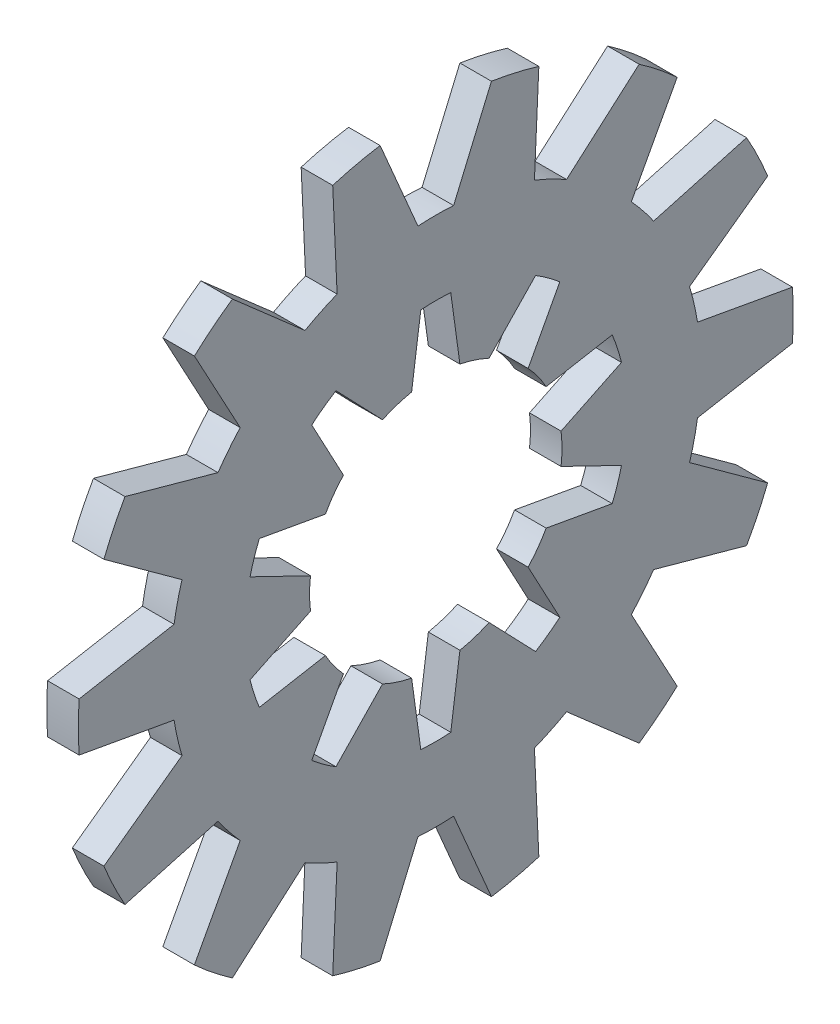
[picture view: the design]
ISO-10303-21;
HEADER;
FILE_DESCRIPTION(('STEP AP214'),'2;1');
FILE_NAME('part.step','',(''),(''),'','','');
FILE_SCHEMA(('AUTOMOTIVE_DESIGN { 1 0 10303 214 1 1 1 1 }'));
ENDSEC;
DATA;
#1=APPLICATION_CONTEXT('core data for automotive mechanical design processes');
#2=APPLICATION_PROTOCOL_DEFINITION('international standard','automotive_design',2000,#1);
#3=PRODUCT_CONTEXT('',#1,'mechanical');
#4=PRODUCT('Part','Part','',(#3));
#5=PRODUCT_RELATED_PRODUCT_CATEGORY('part','',(#4));
#6=PRODUCT_DEFINITION_FORMATION('','',#4);
#7=PRODUCT_DEFINITION_CONTEXT('part definition',#1,'design');
#8=PRODUCT_DEFINITION('design','',#6,#7);
#9=PRODUCT_DEFINITION_SHAPE('','',#8);
#10=(LENGTH_UNIT() NAMED_UNIT(*) SI_UNIT(.MILLI.,.METRE.));
#11=(NAMED_UNIT(*) PLANE_ANGLE_UNIT() SI_UNIT($,.RADIAN.));
#12=(NAMED_UNIT(*) SI_UNIT($,.STERADIAN.) SOLID_ANGLE_UNIT());
#13=UNCERTAINTY_MEASURE_WITH_UNIT(LENGTH_MEASURE(1.E-05),#10,'distance_accuracy_value','');
#14=(GEOMETRIC_REPRESENTATION_CONTEXT(3) GLOBAL_UNCERTAINTY_ASSIGNED_CONTEXT((#13)) GLOBAL_UNIT_ASSIGNED_CONTEXT((#10,
#11,#12)) REPRESENTATION_CONTEXT('',''));
#15=CARTESIAN_POINT('',(0.,0.,0.));
#16=DIRECTION('',(0.,0.,1.));
#17=DIRECTION('',(1.,0.,0.));
#18=AXIS2_PLACEMENT_3D('',#15,#16,#17);
#19=CARTESIAN_POINT('',(-34.9249999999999,0.,0.));
#20=DIRECTION('',(-1.,0.,0.));
#21=DIRECTION('',(0.,0.,1.));
#22=AXIS2_PLACEMENT_3D('',#19,#20,#21);
#23=CYLINDRICAL_SURFACE('',#22,3.2512);
#24=CARTESIAN_POINT('',(-0.812800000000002,0.,0.));
#25=DIRECTION('',(-1.,0.,0.));
#26=DIRECTION('',(0.,0.,1.));
#27=AXIS2_PLACEMENT_3D('',#24,#25,#26);
#28=CIRCLE('',#27,3.2512);
#29=CARTESIAN_POINT('',(-0.812800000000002,-0.394747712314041,3.22714667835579));
#30=VERTEX_POINT('',#29);
#31=CARTESIAN_POINT('',(-0.812800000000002,0.394747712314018,3.2271466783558));
#32=VERTEX_POINT('',#31);
#33=EDGE_CURVE('E1306',#30,#32,#28,.T.);
#34=ORIENTED_EDGE('',*,*,#33,.T.);
#35=DIRECTION('',(-1.,0.,0.));
#36=VECTOR('',#35,1.);
#37=CARTESIAN_POINT('',(-34.9249999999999,0.394747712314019,3.2271466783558));
#38=LINE('',#37,#36);
#39=CARTESIAN_POINT('',(0.,0.394747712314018,3.2271466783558));
#40=VERTEX_POINT('',#39);
#41=EDGE_CURVE('E646',#32,#40,#38,.F.);
#42=ORIENTED_EDGE('',*,*,#41,.T.);
#43=CARTESIAN_POINT('',(0.,0.,0.));
#44=DIRECTION('',(-1.,0.,0.));
#45=DIRECTION('',(0.,0.,1.));
#46=AXIS2_PLACEMENT_3D('',#43,#44,#45);
#47=CIRCLE('',#46,3.2512);
#48=CARTESIAN_POINT('',(0.,-0.394747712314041,3.22714667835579));
#49=VERTEX_POINT('',#48);
#50=EDGE_CURVE('E1313',#49,#40,#47,.T.);
#51=ORIENTED_EDGE('',*,*,#50,.F.);
#52=DIRECTION('',(-1.,0.,0.));
#53=VECTOR('',#52,1.);
#54=CARTESIAN_POINT('',(-34.9249999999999,-0.394747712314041,3.22714667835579));
#55=LINE('',#54,#53);
#56=EDGE_CURVE('E820',#49,#30,#55,.T.);
#57=ORIENTED_EDGE('',*,*,#56,.T.);
#58=EDGE_LOOP('',(#34,#42,#51,#57));
#59=FACE_BOUND('',#58,.T.);
#60=ADVANCED_FACE('F39',(#59),#23,.F.);
#61=CARTESIAN_POINT('',(-0.812800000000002,-2.21622683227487,2.37878962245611));
#62=VERTEX_POINT('',#61);
#63=CARTESIAN_POINT('',(-0.812800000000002,-1.57751161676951,2.84284338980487));
#64=VERTEX_POINT('',#63);
#65=EDGE_CURVE('E1370',#62,#64,#28,.T.);
#66=ORIENTED_EDGE('',*,*,#65,.T.);
#67=DIRECTION('',(-1.,0.,0.));
#68=VECTOR('',#67,1.);
#69=CARTESIAN_POINT('',(-34.9249999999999,-1.57751161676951,2.84284338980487));
#70=LINE('',#69,#68);
#71=CARTESIAN_POINT('',(0.,-1.57751161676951,2.84284338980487));
#72=VERTEX_POINT('',#71);
#73=EDGE_CURVE('E823',#64,#72,#70,.F.);
#74=ORIENTED_EDGE('',*,*,#73,.T.);
#75=CARTESIAN_POINT('',(0.,-2.21622683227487,2.37878962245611));
#76=VERTEX_POINT('',#75);
#77=EDGE_CURVE('E1315',#76,#72,#47,.T.);
#78=ORIENTED_EDGE('',*,*,#77,.F.);
#79=DIRECTION('',(-1.,0.,0.));
#80=VECTOR('',#79,1.);
#81=CARTESIAN_POINT('',(-34.9249999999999,-2.21622683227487,2.37878962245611));
#82=LINE('',#81,#80);
#83=EDGE_CURVE('E814',#76,#62,#82,.T.);
#84=ORIENTED_EDGE('',*,*,#83,.T.);
#85=EDGE_LOOP('',(#66,#74,#78,#84));
#86=FACE_BOUND('',#85,.T.);
#87=ADVANCED_FACE('F1369',(#86),#23,.F.);
#88=CARTESIAN_POINT('',(-0.812800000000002,-3.19118262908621,0.62181578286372));
#89=VERTEX_POINT('',#88);
#90=CARTESIAN_POINT('',(-0.812800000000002,-2.94721512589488,1.37267055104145));
#91=VERTEX_POINT('',#90);
#92=EDGE_CURVE('E1354',#89,#91,#28,.T.);
#93=ORIENTED_EDGE('',*,*,#92,.T.);
#94=DIRECTION('',(-1.,0.,0.));
#95=VECTOR('',#94,1.);
#96=CARTESIAN_POINT('',(-34.9249999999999,-2.94721512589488,1.37267055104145));
#97=LINE('',#96,#95);
#98=CARTESIAN_POINT('',(0.,-2.94721512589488,1.37267055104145));
#99=VERTEX_POINT('',#98);
#100=EDGE_CURVE('E817',#91,#99,#97,.F.);
#101=ORIENTED_EDGE('',*,*,#100,.T.);
#102=CARTESIAN_POINT('',(0.,-3.19118262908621,0.62181578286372));
#103=VERTEX_POINT('',#102);
#104=EDGE_CURVE('E1317',#103,#99,#47,.T.);
#105=ORIENTED_EDGE('',*,*,#104,.F.);
#106=DIRECTION('',(-1.,0.,0.));
#107=VECTOR('',#106,1.);
#108=CARTESIAN_POINT('',(-34.9249999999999,-3.19118262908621,0.62181578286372));
#109=LINE('',#108,#107);
#110=EDGE_CURVE('E808',#103,#89,#109,.T.);
#111=ORIENTED_EDGE('',*,*,#110,.T.);
#112=EDGE_LOOP('',(#93,#101,#105,#111));
#113=FACE_BOUND('',#112,.T.);
#114=ADVANCED_FACE('F1352',(#113),#23,.F.);
#115=CARTESIAN_POINT('',(-0.812800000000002,-2.94721512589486,-1.37267055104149));
#116=VERTEX_POINT('',#115);
#117=CARTESIAN_POINT('',(-0.812800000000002,-3.1911826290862,-0.621815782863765));
#118=VERTEX_POINT('',#117);
#119=EDGE_CURVE('E1374',#116,#118,#28,.T.);
#120=ORIENTED_EDGE('',*,*,#119,.T.);
#121=DIRECTION('',(-1.,0.,0.));
#122=VECTOR('',#121,1.);
#123=CARTESIAN_POINT('',(-34.9249999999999,-3.1911826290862,-0.621815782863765));
#124=LINE('',#123,#122);
#125=CARTESIAN_POINT('',(0.,-3.1911826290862,-0.621815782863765));
#126=VERTEX_POINT('',#125);
#127=EDGE_CURVE('E811',#118,#126,#124,.F.);
#128=ORIENTED_EDGE('',*,*,#127,.T.);
#129=CARTESIAN_POINT('',(0.,-2.94721512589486,-1.37267055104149));
#130=VERTEX_POINT('',#129);
#131=EDGE_CURVE('E1335',#130,#126,#47,.T.);
#132=ORIENTED_EDGE('',*,*,#131,.F.);
#133=DIRECTION('',(-1.,0.,0.));
#134=VECTOR('',#133,1.);
#135=CARTESIAN_POINT('',(-34.9249999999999,-2.94721512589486,-1.37267055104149));
#136=LINE('',#135,#134);
#137=EDGE_CURVE('E802',#130,#116,#136,.T.);
#138=ORIENTED_EDGE('',*,*,#137,.T.);
#139=EDGE_LOOP('',(#120,#128,#132,#138));
#140=FACE_BOUND('',#139,.T.);
#141=ADVANCED_FACE('F1394',(#140),#23,.F.);
#142=CARTESIAN_POINT('',(-0.812800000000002,-1.57751161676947,-2.84284338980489));
#143=VERTEX_POINT('',#142);
#144=CARTESIAN_POINT('',(-0.812800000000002,-2.21622683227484,-2.37878962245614));
#145=VERTEX_POINT('',#144);
#146=EDGE_CURVE('E1385',#143,#145,#28,.T.);
#147=ORIENTED_EDGE('',*,*,#146,.T.);
#148=DIRECTION('',(-1.,0.,0.));
#149=VECTOR('',#148,1.);
#150=CARTESIAN_POINT('',(-34.9249999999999,-2.21622683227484,-2.37878962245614));
#151=LINE('',#150,#149);
#152=CARTESIAN_POINT('',(0.,-2.21622683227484,-2.37878962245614));
#153=VERTEX_POINT('',#152);
#154=EDGE_CURVE('E805',#145,#153,#151,.F.);
#155=ORIENTED_EDGE('',*,*,#154,.T.);
#156=CARTESIAN_POINT('',(0.,-1.57751161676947,-2.84284338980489));
#157=VERTEX_POINT('',#156);
#158=EDGE_CURVE('E1330',#157,#153,#47,.T.);
#159=ORIENTED_EDGE('',*,*,#158,.F.);
#160=DIRECTION('',(-1.,0.,0.));
#161=VECTOR('',#160,1.);
#162=CARTESIAN_POINT('',(-34.9249999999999,-1.57751161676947,-2.84284338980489));
#163=LINE('',#162,#161);
#164=EDGE_CURVE('E796',#157,#143,#163,.T.);
#165=ORIENTED_EDGE('',*,*,#164,.T.);
#166=EDGE_LOOP('',(#147,#155,#159,#165));
#167=FACE_BOUND('',#166,.T.);
#168=ADVANCED_FACE('F1491',(#167),#23,.F.);
#169=CARTESIAN_POINT('',(-0.812800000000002,0.394747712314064,-3.22714667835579));
#170=VERTEX_POINT('',#169);
#171=CARTESIAN_POINT('',(-0.812800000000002,-0.394747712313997,-3.2271466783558));
#172=VERTEX_POINT('',#171);
#173=EDGE_CURVE('E1381',#170,#172,#28,.T.);
#174=ORIENTED_EDGE('',*,*,#173,.T.);
#175=DIRECTION('',(-1.,0.,0.));
#176=VECTOR('',#175,1.);
#177=CARTESIAN_POINT('',(-34.9249999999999,-0.394747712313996,-3.2271466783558));
#178=LINE('',#177,#176);
#179=CARTESIAN_POINT('',(0.,-0.394747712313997,-3.2271466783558));
#180=VERTEX_POINT('',#179);
#181=EDGE_CURVE('E799',#172,#180,#178,.F.);
#182=ORIENTED_EDGE('',*,*,#181,.T.);
#183=CARTESIAN_POINT('',(0.,0.394747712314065,-3.22714667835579));
#184=VERTEX_POINT('',#183);
#185=EDGE_CURVE('E1325',#184,#180,#47,.T.);
#186=ORIENTED_EDGE('',*,*,#185,.F.);
#187=DIRECTION('',(-1.,0.,0.));
#188=VECTOR('',#187,1.);
#189=CARTESIAN_POINT('',(-34.9249999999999,0.394747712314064,-3.22714667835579));
#190=LINE('',#189,#188);
#191=EDGE_CURVE('E790',#184,#170,#190,.T.);
#192=ORIENTED_EDGE('',*,*,#191,.T.);
#193=EDGE_LOOP('',(#174,#182,#186,#192));
#194=FACE_BOUND('',#193,.T.);
#195=ADVANCED_FACE('F1481',(#194),#23,.F.);
#196=CARTESIAN_POINT('',(-0.812800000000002,2.21622683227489,-2.37878962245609));
#197=VERTEX_POINT('',#196);
#198=CARTESIAN_POINT('',(-0.812800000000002,1.57751161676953,-2.84284338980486));
#199=VERTEX_POINT('',#198);
#200=EDGE_CURVE('E1221',#197,#199,#28,.T.);
#201=ORIENTED_EDGE('',*,*,#200,.T.);
#202=DIRECTION('',(-1.,0.,0.));
#203=VECTOR('',#202,1.);
#204=CARTESIAN_POINT('',(-34.9249999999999,1.57751161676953,-2.84284338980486));
#205=LINE('',#204,#203);
#206=CARTESIAN_POINT('',(0.,1.57751161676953,-2.84284338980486));
#207=VERTEX_POINT('',#206);
#208=EDGE_CURVE('E793',#199,#207,#205,.F.);
#209=ORIENTED_EDGE('',*,*,#208,.T.);
#210=CARTESIAN_POINT('',(0.,2.21622683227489,-2.37878962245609));
#211=VERTEX_POINT('',#210);
#212=EDGE_CURVE('E1239',#211,#207,#47,.T.);
#213=ORIENTED_EDGE('',*,*,#212,.F.);
#214=DIRECTION('',(-1.,0.,0.));
#215=VECTOR('',#214,1.);
#216=CARTESIAN_POINT('',(-34.9249999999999,2.21622683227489,-2.37878962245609));
#217=LINE('',#216,#215);
#218=EDGE_CURVE('E639',#211,#197,#217,.T.);
#219=ORIENTED_EDGE('',*,*,#218,.T.);
#220=EDGE_LOOP('',(#201,#209,#213,#219));
#221=FACE_BOUND('',#220,.T.);
#222=ADVANCED_FACE('F1439',(#221),#23,.F.);
#223=CARTESIAN_POINT('',(-0.812800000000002,3.19118262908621,-0.621815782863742));
#224=VERTEX_POINT('',#223);
#225=CARTESIAN_POINT('',(-0.812800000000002,2.94721512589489,-1.37267055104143));
#226=VERTEX_POINT('',#225);
#227=EDGE_CURVE('E1217',#224,#226,#28,.T.);
#228=ORIENTED_EDGE('',*,*,#227,.T.);
#229=DIRECTION('',(-1.,0.,0.));
#230=VECTOR('',#229,1.);
#231=CARTESIAN_POINT('',(-34.9249999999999,2.94721512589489,-1.37267055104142));
#232=LINE('',#231,#230);
#233=CARTESIAN_POINT('',(0.,2.94721512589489,-1.37267055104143));
#234=VERTEX_POINT('',#233);
#235=EDGE_CURVE('E787',#226,#234,#232,.F.);
#236=ORIENTED_EDGE('',*,*,#235,.T.);
#237=CARTESIAN_POINT('',(0.,3.19118262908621,-0.621815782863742));
#238=VERTEX_POINT('',#237);
#239=EDGE_CURVE('E1235',#238,#234,#47,.T.);
#240=ORIENTED_EDGE('',*,*,#239,.F.);
#241=DIRECTION('',(-1.,0.,0.));
#242=VECTOR('',#241,1.);
#243=CARTESIAN_POINT('',(-34.9249999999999,3.19118262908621,-0.621815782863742));
#244=LINE('',#243,#242);
#245=EDGE_CURVE('E872',#238,#224,#244,.T.);
#246=ORIENTED_EDGE('',*,*,#245,.T.);
#247=EDGE_LOOP('',(#228,#236,#240,#246));
#248=FACE_BOUND('',#247,.T.);
#249=ADVANCED_FACE('F1432',(#248),#23,.F.);
#250=CARTESIAN_POINT('',(0.,1.57751161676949,2.84284338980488));
#251=VERTEX_POINT('',#250);
#252=CARTESIAN_POINT('',(0.,2.21622683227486,2.37878962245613));
#253=VERTEX_POINT('',#252);
#254=EDGE_CURVE('E1240',#251,#253,#47,.T.);
#255=ORIENTED_EDGE('',*,*,#254,.F.);
#256=DIRECTION('',(-1.,0.,0.));
#257=VECTOR('',#256,1.);
#258=CARTESIAN_POINT('',(-34.9249999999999,1.57751161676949,2.84284338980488));
#259=LINE('',#258,#257);
#260=CARTESIAN_POINT('',(-0.812800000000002,1.57751161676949,2.84284338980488));
#261=VERTEX_POINT('',#260);
#262=EDGE_CURVE('E826',#251,#261,#259,.T.);
#263=ORIENTED_EDGE('',*,*,#262,.T.);
#264=CARTESIAN_POINT('',(-0.812800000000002,2.21622683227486,2.37878962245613));
#265=VERTEX_POINT('',#264);
#266=EDGE_CURVE('E1222',#261,#265,#28,.T.);
#267=ORIENTED_EDGE('',*,*,#266,.T.);
#268=DIRECTION('',(-1.,0.,0.));
#269=VECTOR('',#268,1.);
#270=CARTESIAN_POINT('',(-34.9249999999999,2.21622683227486,2.37878962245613));
#271=LINE('',#270,#269);
#272=EDGE_CURVE('E852',#265,#253,#271,.F.);
#273=ORIENTED_EDGE('',*,*,#272,.T.);
#274=EDGE_LOOP('',(#255,#263,#267,#273));
#275=FACE_BOUND('',#274,.T.);
#276=ADVANCED_FACE('F1420',(#275),#23,.F.);
#277=CARTESIAN_POINT('',(-34.9249999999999,0.,0.));
#278=DIRECTION('',(-1.,0.,0.));
#279=DIRECTION('',(0.,0.,1.));
#280=AXIS2_PLACEMENT_3D('',#277,#278,#279);
#281=CYLINDRICAL_SURFACE('',#280,9.2075);
#282=CARTESIAN_POINT('',(-0.812800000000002,0.,0.));
#283=DIRECTION('',(-1.,0.,0.));
#284=DIRECTION('',(0.,0.,1.));
#285=AXIS2_PLACEMENT_3D('',#282,#283,#284);
#286=CIRCLE('',#285,9.2075);
#287=CARTESIAN_POINT('',(-0.812800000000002,6.79155829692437,6.2171369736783));
#288=VERTEX_POINT('',#287);
#289=CARTESIAN_POINT('',(-0.812800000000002,7.57252426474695,5.23783662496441));
#290=VERTEX_POINT('',#289);
#291=EDGE_CURVE('E1228',#288,#290,#286,.T.);
#292=ORIENTED_EDGE('',*,*,#291,.F.);
#293=DIRECTION('',(-1.,0.,0.));
#294=VECTOR('',#293,1.);
#295=CARTESIAN_POINT('',(-34.9249999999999,6.79155829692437,6.2171369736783));
#296=LINE('',#295,#294);
#297=CARTESIAN_POINT('',(0.,6.79155829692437,6.2171369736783));
#298=VERTEX_POINT('',#297);
#299=EDGE_CURVE('E1165',#288,#298,#296,.F.);
#300=ORIENTED_EDGE('',*,*,#299,.T.);
#301=CARTESIAN_POINT('',(0.,0.,0.));
#302=DIRECTION('',(-1.,0.,0.));
#303=DIRECTION('',(0.,0.,1.));
#304=AXIS2_PLACEMENT_3D('',#301,#302,#303);
#305=CIRCLE('',#304,9.2075);
#306=CARTESIAN_POINT('',(0.,7.57252426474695,5.23783662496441));
#307=VERTEX_POINT('',#306);
#308=EDGE_CURVE('E1234',#298,#307,#305,.T.);
#309=ORIENTED_EDGE('',*,*,#308,.T.);
#310=DIRECTION('',(-1.,0.,0.));
#311=VECTOR('',#310,1.);
#312=CARTESIAN_POINT('',(-34.9249999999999,7.57252426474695,5.23783662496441));
#313=LINE('',#312,#311);
#314=EDGE_CURVE('E1184',#307,#290,#313,.T.);
#315=ORIENTED_EDGE('',*,*,#314,.T.);
#316=EDGE_LOOP('',(#292,#300,#309,#315));
#317=FACE_BOUND('',#316,.T.);
#318=ADVANCED_FACE('F1431',(#317),#281,.T.);
#319=CARTESIAN_POINT('',(0.,3.42146795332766,8.54819356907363));
#320=VERTEX_POINT('',#319);
#321=CARTESIAN_POINT('',(0.,4.54999647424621,8.00472287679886));
#322=VERTEX_POINT('',#321);
#323=EDGE_CURVE('E1730',#320,#322,#305,.T.);
#324=ORIENTED_EDGE('',*,*,#323,.T.);
#325=DIRECTION('',(-1.,0.,0.));
#326=VECTOR('',#325,1.);
#327=CARTESIAN_POINT('',(-34.9249999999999,4.5499964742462,8.00472287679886));
#328=LINE('',#327,#326);
#329=CARTESIAN_POINT('',(-0.812800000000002,4.54999647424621,8.00472287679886));
#330=VERTEX_POINT('',#329);
#331=EDGE_CURVE('E1162',#322,#330,#328,.T.);
#332=ORIENTED_EDGE('',*,*,#331,.T.);
#333=CARTESIAN_POINT('',(-0.812800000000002,3.42146795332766,8.54819356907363));
#334=VERTEX_POINT('',#333);
#335=EDGE_CURVE('E1783',#334,#330,#286,.T.);
#336=ORIENTED_EDGE('',*,*,#335,.F.);
#337=DIRECTION('',(-1.,0.,0.));
#338=VECTOR('',#337,1.);
#339=CARTESIAN_POINT('',(-34.9249999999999,3.42146795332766,8.54819356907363));
#340=LINE('',#339,#338);
#341=EDGE_CURVE('E1159',#334,#320,#340,.F.);
#342=ORIENTED_EDGE('',*,*,#341,.T.);
#343=EDGE_LOOP('',(#324,#332,#336,#342));
#344=FACE_BOUND('',#343,.T.);
#345=ADVANCED_FACE('F1437',(#344),#281,.T.);
#346=CARTESIAN_POINT('',(0.,-0.626286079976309,9.18617559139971));
#347=VERTEX_POINT('',#346);
#348=CARTESIAN_POINT('',(0.,0.626286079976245,9.18617559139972));
#349=VERTEX_POINT('',#348);
#350=EDGE_CURVE('E1764',#347,#349,#305,.T.);
#351=ORIENTED_EDGE('',*,*,#350,.T.);
#352=DIRECTION('',(-1.,0.,0.));
#353=VECTOR('',#352,1.);
#354=CARTESIAN_POINT('',(-34.9249999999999,0.626286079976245,9.18617559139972));
#355=LINE('',#354,#353);
#356=CARTESIAN_POINT('',(-0.812800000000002,0.626286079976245,9.18617559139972));
#357=VERTEX_POINT('',#356);
#358=EDGE_CURVE('E1156',#349,#357,#355,.T.);
#359=ORIENTED_EDGE('',*,*,#358,.T.);
#360=CARTESIAN_POINT('',(-0.812800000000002,-0.626286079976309,9.18617559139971));
#361=VERTEX_POINT('',#360);
#362=EDGE_CURVE('E1785',#361,#357,#286,.T.);
#363=ORIENTED_EDGE('',*,*,#362,.F.);
#364=DIRECTION('',(-1.,0.,0.));
#365=VECTOR('',#364,1.);
#366=CARTESIAN_POINT('',(-34.9249999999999,-0.626286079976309,9.18617559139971));
#367=LINE('',#366,#365);
#368=EDGE_CURVE('E1153',#361,#347,#367,.F.);
#369=ORIENTED_EDGE('',*,*,#368,.T.);
#370=EDGE_LOOP('',(#351,#359,#363,#369));
#371=FACE_BOUND('',#370,.T.);
#372=ADVANCED_FACE('F1821',(#371),#281,.T.);
#373=CARTESIAN_POINT('',(-0.812800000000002,-9.09522075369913,1.43353259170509));
#374=VERTEX_POINT('',#373);
#375=CARTESIAN_POINT('',(-0.812800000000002,-8.81649722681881,2.65470015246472));
#376=VERTEX_POINT('',#375);
#377=EDGE_CURVE('E1803',#374,#376,#286,.T.);
#378=ORIENTED_EDGE('',*,*,#377,.F.);
#379=DIRECTION('',(-1.,0.,0.));
#380=VECTOR('',#379,1.);
#381=CARTESIAN_POINT('',(-34.9249999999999,-9.09522075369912,1.43353259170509));
#382=LINE('',#381,#380);
#383=CARTESIAN_POINT('',(0.,-9.09522075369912,1.43353259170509));
#384=VERTEX_POINT('',#383);
#385=EDGE_CURVE('E1147',#374,#384,#382,.F.);
#386=ORIENTED_EDGE('',*,*,#385,.T.);
#387=CARTESIAN_POINT('',(0.,-8.81649722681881,2.65470015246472));
#388=VERTEX_POINT('',#387);
#389=EDGE_CURVE('E1752',#384,#388,#305,.T.);
#390=ORIENTED_EDGE('',*,*,#389,.T.);
#391=DIRECTION('',(-1.,0.,0.));
#392=VECTOR('',#391,1.);
#393=CARTESIAN_POINT('',(-34.9249999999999,-8.81649722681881,2.65470015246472));
#394=LINE('',#393,#392);
#395=EDGE_CURVE('E1138',#388,#376,#394,.T.);
#396=ORIENTED_EDGE('',*,*,#395,.T.);
#397=EDGE_LOOP('',(#378,#386,#390,#396));
#398=FACE_BOUND('',#397,.T.);
#399=ADVANCED_FACE('F1825',(#398),#281,.T.);
#400=CARTESIAN_POINT('',(-0.812800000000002,-7.57252426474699,5.23783662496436));
#401=VERTEX_POINT('',#400);
#402=CARTESIAN_POINT('',(-0.812800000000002,-6.79155829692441,6.21713697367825));
#403=VERTEX_POINT('',#402);
#404=EDGE_CURVE('E1806',#401,#403,#286,.T.);
#405=ORIENTED_EDGE('',*,*,#404,.F.);
#406=DIRECTION('',(-1.,0.,0.));
#407=VECTOR('',#406,1.);
#408=CARTESIAN_POINT('',(-34.9249999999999,-7.57252426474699,5.23783662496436));
#409=LINE('',#408,#407);
#410=CARTESIAN_POINT('',(0.,-7.57252426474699,5.23783662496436));
#411=VERTEX_POINT('',#410);
#412=EDGE_CURVE('E1141',#401,#411,#409,.F.);
#413=ORIENTED_EDGE('',*,*,#412,.T.);
#414=CARTESIAN_POINT('',(0.,-6.79155829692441,6.21713697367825));
#415=VERTEX_POINT('',#414);
#416=EDGE_CURVE('E1756',#411,#415,#305,.T.);
#417=ORIENTED_EDGE('',*,*,#416,.T.);
#418=DIRECTION('',(-1.,0.,0.));
#419=VECTOR('',#418,1.);
#420=CARTESIAN_POINT('',(-34.9249999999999,-6.79155829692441,6.21713697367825));
#421=LINE('',#420,#419);
#422=EDGE_CURVE('E1132',#415,#403,#421,.T.);
#423=ORIENTED_EDGE('',*,*,#422,.T.);
#424=EDGE_LOOP('',(#405,#413,#417,#423));
#425=FACE_BOUND('',#424,.T.);
#426=ADVANCED_FACE('F1830',(#425),#281,.T.);
#427=CARTESIAN_POINT('',(0.,-4.54999647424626,8.00472287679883));
#428=VERTEX_POINT('',#427);
#429=CARTESIAN_POINT('',(0.,-3.42146795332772,8.54819356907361));
#430=VERTEX_POINT('',#429);
#431=EDGE_CURVE('E1760',#428,#430,#305,.T.);
#432=ORIENTED_EDGE('',*,*,#431,.T.);
#433=DIRECTION('',(-1.,0.,0.));
#434=VECTOR('',#433,1.);
#435=CARTESIAN_POINT('',(-34.9249999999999,-3.42146795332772,8.54819356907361));
#436=LINE('',#435,#434);
#437=CARTESIAN_POINT('',(-0.812800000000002,-3.42146795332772,8.54819356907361));
#438=VERTEX_POINT('',#437);
#439=EDGE_CURVE('E1150',#430,#438,#436,.T.);
#440=ORIENTED_EDGE('',*,*,#439,.T.);
#441=CARTESIAN_POINT('',(-0.812800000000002,-4.54999647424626,8.00472287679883));
#442=VERTEX_POINT('',#441);
#443=EDGE_CURVE('E1787',#442,#438,#286,.T.);
#444=ORIENTED_EDGE('',*,*,#443,.F.);
#445=DIRECTION('',(-1.,0.,0.));
#446=VECTOR('',#445,1.);
#447=CARTESIAN_POINT('',(-34.9249999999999,-4.54999647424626,8.00472287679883));
#448=LINE('',#447,#446);
#449=EDGE_CURVE('E1135',#442,#428,#448,.F.);
#450=ORIENTED_EDGE('',*,*,#449,.T.);
#451=EDGE_LOOP('',(#432,#440,#444,#450));
#452=FACE_BOUND('',#451,.T.);
#453=ADVANCED_FACE('F1813',(#452),#281,.T.);
#454=CARTESIAN_POINT('',(-0.812800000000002,-3.42146795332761,-8.54819356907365));
#455=VERTEX_POINT('',#454);
#456=CARTESIAN_POINT('',(-0.812800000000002,-4.54999647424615,-8.00472287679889));
#457=VERTEX_POINT('',#456);
#458=EDGE_CURVE('E1794',#455,#457,#286,.T.);
#459=ORIENTED_EDGE('',*,*,#458,.F.);
#460=DIRECTION('',(-1.,0.,0.));
#461=VECTOR('',#460,1.);
#462=CARTESIAN_POINT('',(-34.9249999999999,-3.42146795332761,-8.54819356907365));
#463=LINE('',#462,#461);
#464=CARTESIAN_POINT('',(0.,-3.42146795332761,-8.54819356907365));
#465=VERTEX_POINT('',#464);
#466=EDGE_CURVE('E1129',#455,#465,#463,.F.);
#467=ORIENTED_EDGE('',*,*,#466,.T.);
#468=CARTESIAN_POINT('',(0.,-4.54999647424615,-8.00472287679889));
#469=VERTEX_POINT('',#468);
#470=EDGE_CURVE('E1740',#465,#469,#305,.T.);
#471=ORIENTED_EDGE('',*,*,#470,.T.);
#472=DIRECTION('',(-1.,0.,0.));
#473=VECTOR('',#472,1.);
#474=CARTESIAN_POINT('',(-34.9249999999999,-4.54999647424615,-8.00472287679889));
#475=LINE('',#474,#473);
#476=EDGE_CURVE('E1120',#469,#457,#475,.T.);
#477=ORIENTED_EDGE('',*,*,#476,.T.);
#478=EDGE_LOOP('',(#459,#467,#471,#477));
#479=FACE_BOUND('',#478,.T.);
#480=ADVANCED_FACE('F2410',(#479),#281,.T.);
#481=CARTESIAN_POINT('',(-0.812800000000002,-6.79155829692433,-6.21713697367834));
#482=VERTEX_POINT('',#481);
#483=CARTESIAN_POINT('',(-0.812800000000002,-7.57252426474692,-5.23783662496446));
#484=VERTEX_POINT('',#483);
#485=EDGE_CURVE('E1797',#482,#484,#286,.T.);
#486=ORIENTED_EDGE('',*,*,#485,.F.);
#487=DIRECTION('',(-1.,0.,0.));
#488=VECTOR('',#487,1.);
#489=CARTESIAN_POINT('',(-34.9249999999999,-6.79155829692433,-6.21713697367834));
#490=LINE('',#489,#488);
#491=CARTESIAN_POINT('',(0.,-6.79155829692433,-6.21713697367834));
#492=VERTEX_POINT('',#491);
#493=EDGE_CURVE('E1123',#482,#492,#490,.F.);
#494=ORIENTED_EDGE('',*,*,#493,.T.);
#495=CARTESIAN_POINT('',(0.,-7.57252426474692,-5.23783662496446));
#496=VERTEX_POINT('',#495);
#497=EDGE_CURVE('E1744',#492,#496,#305,.T.);
#498=ORIENTED_EDGE('',*,*,#497,.T.);
#499=DIRECTION('',(-1.,0.,0.));
#500=VECTOR('',#499,1.);
#501=CARTESIAN_POINT('',(-34.9249999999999,-7.57252426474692,-5.23783662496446));
#502=LINE('',#501,#500);
#503=EDGE_CURVE('E1114',#496,#484,#502,.T.);
#504=ORIENTED_EDGE('',*,*,#503,.T.);
#505=EDGE_LOOP('',(#486,#494,#498,#504));
#506=FACE_BOUND('',#505,.T.);
#507=ADVANCED_FACE('F2402',(#506),#281,.T.);
#508=CARTESIAN_POINT('',(0.,-8.81649722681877,-2.65470015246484));
#509=VERTEX_POINT('',#508);
#510=CARTESIAN_POINT('',(0.,-9.0952207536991,-1.43353259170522));
#511=VERTEX_POINT('',#510);
#512=EDGE_CURVE('E1748',#509,#511,#305,.T.);
#513=ORIENTED_EDGE('',*,*,#512,.T.);
#514=DIRECTION('',(-1.,0.,0.));
#515=VECTOR('',#514,1.);
#516=CARTESIAN_POINT('',(-34.9249999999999,-9.0952207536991,-1.43353259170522));
#517=LINE('',#516,#515);
#518=CARTESIAN_POINT('',(-0.812800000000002,-9.0952207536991,-1.43353259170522));
#519=VERTEX_POINT('',#518);
#520=EDGE_CURVE('E1144',#511,#519,#517,.T.);
#521=ORIENTED_EDGE('',*,*,#520,.T.);
#522=CARTESIAN_POINT('',(-0.812800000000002,-8.81649722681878,-2.65470015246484));
#523=VERTEX_POINT('',#522);
#524=EDGE_CURVE('E1800',#523,#519,#286,.T.);
#525=ORIENTED_EDGE('',*,*,#524,.F.);
#526=DIRECTION('',(-1.,0.,0.));
#527=VECTOR('',#526,1.);
#528=CARTESIAN_POINT('',(-34.9249999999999,-8.81649722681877,-2.65470015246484));
#529=LINE('',#528,#527);
#530=EDGE_CURVE('E1117',#523,#509,#529,.F.);
#531=ORIENTED_EDGE('',*,*,#530,.T.);
#532=EDGE_LOOP('',(#513,#521,#525,#531));
#533=FACE_BOUND('',#532,.T.);
#534=ADVANCED_FACE('F2395',(#533),#281,.T.);
#535=CARTESIAN_POINT('',(0.,0.626286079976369,-9.18617559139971));
#536=VERTEX_POINT('',#535);
#537=CARTESIAN_POINT('',(0.,-0.626286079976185,-9.18617559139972));
#538=VERTEX_POINT('',#537);
#539=EDGE_CURVE('E1736',#536,#538,#305,.T.);
#540=ORIENTED_EDGE('',*,*,#539,.T.);
#541=DIRECTION('',(-1.,0.,0.));
#542=VECTOR('',#541,1.);
#543=CARTESIAN_POINT('',(-34.9249999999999,-0.626286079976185,-9.18617559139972));
#544=LINE('',#543,#542);
#545=CARTESIAN_POINT('',(-0.812800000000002,-0.626286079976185,-9.18617559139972));
#546=VERTEX_POINT('',#545);
#547=EDGE_CURVE('E1126',#538,#546,#544,.T.);
#548=ORIENTED_EDGE('',*,*,#547,.T.);
#549=CARTESIAN_POINT('',(-0.812800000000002,0.626286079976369,-9.18617559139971));
#550=VERTEX_POINT('',#549);
#551=EDGE_CURVE('E1791',#550,#546,#286,.T.);
#552=ORIENTED_EDGE('',*,*,#551,.F.);
#553=DIRECTION('',(-1.,0.,0.));
#554=VECTOR('',#553,1.);
#555=CARTESIAN_POINT('',(-34.9249999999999,0.626286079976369,-9.18617559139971));
#556=LINE('',#555,#554);
#557=EDGE_CURVE('E1111',#550,#536,#556,.F.);
#558=ORIENTED_EDGE('',*,*,#557,.T.);
#559=EDGE_LOOP('',(#540,#548,#552,#558));
#560=FACE_BOUND('',#559,.T.);
#561=ADVANCED_FACE('F2387',(#560),#281,.T.);
#562=CARTESIAN_POINT('',(-0.812800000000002,7.57252426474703,-5.2378366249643));
#563=VERTEX_POINT('',#562);
#564=CARTESIAN_POINT('',(-0.812800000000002,6.79155829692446,-6.2171369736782));
#565=VERTEX_POINT('',#564);
#566=EDGE_CURVE('E1227',#563,#565,#286,.T.);
#567=ORIENTED_EDGE('',*,*,#566,.F.);
#568=DIRECTION('',(-1.,0.,0.));
#569=VECTOR('',#568,1.);
#570=CARTESIAN_POINT('',(-34.9249999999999,7.57252426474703,-5.2378366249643));
#571=LINE('',#570,#569);
#572=CARTESIAN_POINT('',(0.,7.57252426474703,-5.2378366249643));
#573=VERTEX_POINT('',#572);
#574=EDGE_CURVE('E1105',#563,#573,#571,.F.);
#575=ORIENTED_EDGE('',*,*,#574,.T.);
#576=CARTESIAN_POINT('',(0.,6.79155829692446,-6.2171369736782));
#577=VERTEX_POINT('',#576);
#578=EDGE_CURVE('E1233',#573,#577,#305,.T.);
#579=ORIENTED_EDGE('',*,*,#578,.T.);
#580=DIRECTION('',(-1.,0.,0.));
#581=VECTOR('',#580,1.);
#582=CARTESIAN_POINT('',(-34.9249999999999,6.79155829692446,-6.2171369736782));
#583=LINE('',#582,#581);
#584=EDGE_CURVE('E898',#577,#565,#583,.T.);
#585=ORIENTED_EDGE('',*,*,#584,.T.);
#586=EDGE_LOOP('',(#567,#575,#579,#585));
#587=FACE_BOUND('',#586,.T.);
#588=ADVANCED_FACE('F2379',(#587),#281,.T.);
#589=CARTESIAN_POINT('',(0.,4.54999647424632,-8.0047228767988));
#590=VERTEX_POINT('',#589);
#591=CARTESIAN_POINT('',(0.,3.42146795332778,-8.54819356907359));
#592=VERTEX_POINT('',#591);
#593=EDGE_CURVE('E1732',#590,#592,#305,.T.);
#594=ORIENTED_EDGE('',*,*,#593,.T.);
#595=DIRECTION('',(-1.,0.,0.));
#596=VECTOR('',#595,1.);
#597=CARTESIAN_POINT('',(-34.9249999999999,3.42146795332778,-8.54819356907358));
#598=LINE('',#597,#596);
#599=CARTESIAN_POINT('',(-0.812800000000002,3.42146795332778,-8.54819356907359));
#600=VERTEX_POINT('',#599);
#601=EDGE_CURVE('E1108',#592,#600,#598,.T.);
#602=ORIENTED_EDGE('',*,*,#601,.T.);
#603=CARTESIAN_POINT('',(-0.812800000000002,4.54999647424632,-8.0047228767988));
#604=VERTEX_POINT('',#603);
#605=EDGE_CURVE('E1789',#604,#600,#286,.T.);
#606=ORIENTED_EDGE('',*,*,#605,.F.);
#607=DIRECTION('',(-1.,0.,0.));
#608=VECTOR('',#607,1.);
#609=CARTESIAN_POINT('',(-34.9249999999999,4.54999647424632,-8.0047228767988));
#610=LINE('',#609,#608);
#611=EDGE_CURVE('E1099',#604,#590,#610,.F.);
#612=ORIENTED_EDGE('',*,*,#611,.T.);
#613=EDGE_LOOP('',(#594,#602,#606,#612));
#614=FACE_BOUND('',#613,.T.);
#615=ADVANCED_FACE('F1428',(#614),#281,.T.);
#616=CARTESIAN_POINT('',(-0.812800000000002,8.81649722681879,2.65470015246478));
#617=VERTEX_POINT('',#616);
#618=CARTESIAN_POINT('',(-0.812800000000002,9.09522075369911,1.43353259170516));
#619=VERTEX_POINT('',#618);
#620=EDGE_CURVE('E1220',#617,#619,#286,.T.);
#621=ORIENTED_EDGE('',*,*,#620,.F.);
#622=DIRECTION('',(-1.,0.,0.));
#623=VECTOR('',#622,1.);
#624=CARTESIAN_POINT('',(-34.9249999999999,8.81649722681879,2.65470015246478));
#625=LINE('',#624,#623);
#626=CARTESIAN_POINT('',(0.,8.81649722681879,2.65470015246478));
#627=VERTEX_POINT('',#626);
#628=EDGE_CURVE('E1189',#617,#627,#625,.F.);
#629=ORIENTED_EDGE('',*,*,#628,.T.);
#630=CARTESIAN_POINT('',(0.,9.09522075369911,1.43353259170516));
#631=VERTEX_POINT('',#630);
#632=EDGE_CURVE('E1226',#627,#631,#305,.T.);
#633=ORIENTED_EDGE('',*,*,#632,.T.);
#634=DIRECTION('',(-1.,0.,0.));
#635=VECTOR('',#634,1.);
#636=CARTESIAN_POINT('',(-34.9249999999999,9.09522075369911,1.43353259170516));
#637=LINE('',#636,#635);
#638=EDGE_CURVE('E1208',#631,#619,#637,.T.);
#639=ORIENTED_EDGE('',*,*,#638,.T.);
#640=EDGE_LOOP('',(#621,#629,#633,#639));
#641=FACE_BOUND('',#640,.T.);
#642=ADVANCED_FACE('F1419',(#641),#281,.T.);
#643=CARTESIAN_POINT('',(0.,2.94721512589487,1.37267055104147));
#644=VERTEX_POINT('',#643);
#645=CARTESIAN_POINT('',(0.,3.19118262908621,0.621815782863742));
#646=VERTEX_POINT('',#645);
#647=EDGE_CURVE('E1232',#644,#646,#47,.T.);
#648=ORIENTED_EDGE('',*,*,#647,.F.);
#649=DIRECTION('',(-1.,0.,0.));
#650=VECTOR('',#649,1.);
#651=CARTESIAN_POINT('',(-34.9249999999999,2.94721512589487,1.37267055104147));
#652=LINE('',#651,#650);
#653=CARTESIAN_POINT('',(-0.812800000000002,2.94721512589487,1.37267055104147));
#654=VERTEX_POINT('',#653);
#655=EDGE_CURVE('E847',#644,#654,#652,.T.);
#656=ORIENTED_EDGE('',*,*,#655,.T.);
#657=CARTESIAN_POINT('',(-0.812800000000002,3.19118262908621,0.621815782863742));
#658=VERTEX_POINT('',#657);
#659=EDGE_CURVE('E1216',#654,#658,#28,.T.);
#660=ORIENTED_EDGE('',*,*,#659,.T.);
#661=DIRECTION('',(-1.,0.,0.));
#662=VECTOR('',#661,1.);
#663=CARTESIAN_POINT('',(-34.9249999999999,3.19118262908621,0.621815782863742));
#664=LINE('',#663,#662);
#665=EDGE_CURVE('E877',#658,#646,#664,.F.);
#666=ORIENTED_EDGE('',*,*,#665,.T.);
#667=EDGE_LOOP('',(#648,#656,#660,#666));
#668=FACE_BOUND('',#667,.T.);
#669=ADVANCED_FACE('F41',(#668),#23,.F.);
#670=CARTESIAN_POINT('',(0.,3.2512,0.));
#671=DIRECTION('',(-1.,0.,0.));
#672=DIRECTION('',(0.,0.,1.));
#673=AXIS2_PLACEMENT_3D('',#670,#671,#672);
#674=PLANE('',#673);
#675=ORIENTED_EDGE('',*,*,#308,.F.);
#676=DIRECTION('',(0.,0.880151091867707,0.474693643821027));
#677=VECTOR('',#676,1.);
#678=CARTESIAN_POINT('',(0.,7.20877524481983,6.44215542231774));
#679=LINE('',#678,#677);
#680=CARTESIAN_POINT('',(0.,4.60461298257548,5.03764739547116));
#681=VERTEX_POINT('',#680);
#682=EDGE_CURVE('E885',#681,#298,#679,.T.);
#683=ORIENTED_EDGE('',*,*,#682,.F.);
#684=CARTESIAN_POINT('',(0.,0.,0.));
#685=DIRECTION('',(-1.,0.,0.));
#686=DIRECTION('',(0.,0.781831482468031,-0.623489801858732));
#687=AXIS2_PLACEMENT_3D('',#684,#685,#686);
#688=CIRCLE('',#687,6.82498);
#689=CARTESIAN_POINT('',(0.,3.88672027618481,5.61014772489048));
#690=VERTEX_POINT('',#689);
#691=EDGE_CURVE('E891',#690,#681,#688,.T.);
#692=ORIENTED_EDGE('',*,*,#691,.F.);
#693=DIRECTION('',(0.,-0.26694004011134,-0.963713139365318));
#694=VECTOR('',#693,1.);
#695=CARTESIAN_POINT('',(0.,4.67653373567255,8.4615506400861));
#696=LINE('',#695,#694);
#697=EDGE_CURVE('E889',#322,#690,#696,.T.);
#698=ORIENTED_EDGE('',*,*,#697,.F.);
#699=ORIENTED_EDGE('',*,*,#323,.F.);
#700=DIRECTION('',(0.,0.587026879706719,0.809567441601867));
#701=VECTOR('',#700,1.);
#702=CARTESIAN_POINT('',(0.,3.69973558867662,8.93195183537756));
#703=LINE('',#702,#701);
#704=CARTESIAN_POINT('',(0.,1.96285965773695,6.53663016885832));
#705=VERTEX_POINT('',#704);
#706=EDGE_CURVE('E905',#705,#320,#703,.T.);
#707=ORIENTED_EDGE('',*,*,#706,.F.);
#708=CARTESIAN_POINT('',(0.,0.,0.));
#709=DIRECTION('',(-1.,0.,0.));
#710=DIRECTION('',(0.,0.974927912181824,-0.222520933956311));
#711=AXIS2_PLACEMENT_3D('',#708,#709,#710);
#712=CIRCLE('',#711,6.82498);
#713=CARTESIAN_POINT('',(0.,1.06766209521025,6.740953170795));
#714=VERTEX_POINT('',#713);
#715=EDGE_CURVE('E911',#714,#705,#712,.T.);
#716=ORIENTED_EDGE('',*,*,#715,.F.);
#717=DIRECTION('',(0.,0.177634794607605,-0.984096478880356));
#718=VECTOR('',#717,1.);
#719=CARTESIAN_POINT('',(0.,0.54208207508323,9.65266564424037));
#720=LINE('',#719,#718);
#721=EDGE_CURVE('E909',#349,#714,#720,.T.);
#722=ORIENTED_EDGE('',*,*,#721,.F.);
#723=ORIENTED_EDGE('',*,*,#350,.F.);
#724=DIRECTION('',(0.,0.177634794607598,0.984096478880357));
#725=VECTOR('',#724,1.);
#726=CARTESIAN_POINT('',(0.,-0.542082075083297,9.65266564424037));
#727=LINE('',#726,#725);
#728=CARTESIAN_POINT('',(0.,-1.0676620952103,6.740953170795));
#729=VERTEX_POINT('',#728);
#730=EDGE_CURVE('E923',#729,#347,#727,.T.);
#731=ORIENTED_EDGE('',*,*,#730,.F.);
#732=CARTESIAN_POINT('',(0.,0.,0.));
#733=DIRECTION('',(-1.,0.,0.));
#734=DIRECTION('',(0.,0.974927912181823,0.222520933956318));
#735=AXIS2_PLACEMENT_3D('',#732,#733,#734);
#736=CIRCLE('',#735,6.82498);
#737=CARTESIAN_POINT('',(0.,-1.962859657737,6.53663016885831));
#738=VERTEX_POINT('',#737);
#739=EDGE_CURVE('E929',#738,#729,#736,.T.);
#740=ORIENTED_EDGE('',*,*,#739,.F.);
#741=DIRECTION('',(0.,0.587026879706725,-0.809567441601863));
#742=VECTOR('',#741,1.);
#743=CARTESIAN_POINT('',(0.,-3.69973558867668,8.93195183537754));
#744=LINE('',#743,#742);
#745=EDGE_CURVE('E927',#430,#738,#744,.T.);
#746=ORIENTED_EDGE('',*,*,#745,.F.);
#747=ORIENTED_EDGE('',*,*,#431,.F.);
#748=DIRECTION('',(0.,-0.266940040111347,0.963713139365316));
#749=VECTOR('',#748,1.);
#750=CARTESIAN_POINT('',(0.,-4.6765337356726,8.46155064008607));
#751=LINE('',#750,#749);
#752=CARTESIAN_POINT('',(0.,-3.88672027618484,5.61014772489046));
#753=VERTEX_POINT('',#752);
#754=EDGE_CURVE('E979',#753,#428,#751,.T.);
#755=ORIENTED_EDGE('',*,*,#754,.F.);
#756=CARTESIAN_POINT('',(0.,0.,0.));
#757=DIRECTION('',(-1.,0.,0.));
#758=DIRECTION('',(0.,0.781831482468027,0.623489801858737));
#759=AXIS2_PLACEMENT_3D('',#756,#757,#758);
#760=CIRCLE('',#759,6.82498);
#761=CARTESIAN_POINT('',(0.,-4.60461298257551,5.03764739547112));
#762=VERTEX_POINT('',#761);
#763=EDGE_CURVE('E984',#762,#753,#760,.T.);
#764=ORIENTED_EDGE('',*,*,#763,.F.);
#765=DIRECTION('',(0.,0.88015109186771,-0.474693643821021));
#766=VECTOR('',#765,1.);
#767=CARTESIAN_POINT('',(0.,-7.20877524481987,6.44215542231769));
#768=LINE('',#767,#766);
#769=EDGE_CURVE('E954',#415,#762,#768,.T.);
#770=ORIENTED_EDGE('',*,*,#769,.F.);
#771=ORIENTED_EDGE('',*,*,#416,.F.);
#772=DIRECTION('',(0.,-0.658644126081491,0.752454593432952));
#773=VECTOR('',#772,1.);
#774=CARTESIAN_POINT('',(0.,-7.88474053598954,5.59452175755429));
#775=LINE('',#774,#773);
#776=CARTESIAN_POINT('',(0.,-5.93596583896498,3.36818371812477));
#777=VERTEX_POINT('',#776);
#778=EDGE_CURVE('E941',#777,#411,#775,.T.);
#779=ORIENTED_EDGE('',*,*,#778,.F.);
#780=CARTESIAN_POINT('',(0.,0.,0.));
#781=DIRECTION('',(-1.,0.,0.));
#782=DIRECTION('',(0.,0.433883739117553,0.900968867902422));
#783=AXIS2_PLACEMENT_3D('',#780,#781,#782);
#784=CIRCLE('',#783,6.82498);
#785=CARTESIAN_POINT('',(0.,-6.33436623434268,2.54089677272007));
#786=VERTEX_POINT('',#785);
#787=EDGE_CURVE('E947',#786,#777,#784,.T.);
#788=ORIENTED_EDGE('',*,*,#787,.F.);
#789=DIRECTION('',(0.,0.998950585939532,-0.0458009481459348));
#790=VECTOR('',#789,1.);
#791=CARTESIAN_POINT('',(0.,-9.29002855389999,2.67641112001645));
#792=LINE('',#791,#790);
#793=EDGE_CURVE('E945',#388,#786,#792,.T.);
#794=ORIENTED_EDGE('',*,*,#793,.F.);
#795=ORIENTED_EDGE('',*,*,#389,.F.);
#796=DIRECTION('',(0.,-0.919895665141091,0.392163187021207));
#797=VECTOR('',#796,1.);
#798=CARTESIAN_POINT('',(0.,-9.531277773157,1.61942922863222));
#799=LINE('',#798,#797);
#800=CARTESIAN_POINT('',(0.,-6.80952056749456,0.459109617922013));
#801=VERTEX_POINT('',#800);
#802=EDGE_CURVE('E961',#801,#384,#799,.T.);
#803=ORIENTED_EDGE('',*,*,#802,.F.);
#804=CARTESIAN_POINT('',(0.,0.,0.));
#805=DIRECTION('',(-1.,0.,0.));
#806=DIRECTION('',(0.,0.,1.));
#807=AXIS2_PLACEMENT_3D('',#804,#805,#806);
#808=CIRCLE('',#807,6.82498);
#809=CARTESIAN_POINT('',(0.,-6.80952056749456,-0.459109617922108));
#810=VERTEX_POINT('',#809);
#811=EDGE_CURVE('E967',#810,#801,#808,.T.);
#812=ORIENTED_EDGE('',*,*,#811,.F.);
#813=DIRECTION('',(0.,0.919895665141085,0.39216318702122));
#814=VECTOR('',#813,1.);
#815=CARTESIAN_POINT('',(0.,-9.53127777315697,-1.61942922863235));
#816=LINE('',#815,#814);
#817=EDGE_CURVE('E965',#511,#810,#816,.T.);
#818=ORIENTED_EDGE('',*,*,#817,.F.);
#819=ORIENTED_EDGE('',*,*,#512,.F.);
#820=DIRECTION('',(0.,-0.998950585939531,-0.0458009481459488));
#821=VECTOR('',#820,1.);
#822=CARTESIAN_POINT('',(0.,-9.29002855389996,-2.67641112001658));
#823=LINE('',#822,#821);
#824=CARTESIAN_POINT('',(0.,-6.33436623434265,-2.54089677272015));
#825=VERTEX_POINT('',#824);
#826=EDGE_CURVE('E1033',#825,#509,#823,.T.);
#827=ORIENTED_EDGE('',*,*,#826,.F.);
#828=CARTESIAN_POINT('',(0.,0.,0.));
#829=DIRECTION('',(-1.,0.,0.));
#830=DIRECTION('',(0.,-0.433883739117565,0.900968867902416));
#831=AXIS2_PLACEMENT_3D('',#828,#829,#830);
#832=CIRCLE('',#831,6.82498);
#833=CARTESIAN_POINT('',(0.,-5.93596583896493,-3.36818371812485));
#834=VERTEX_POINT('',#833);
#835=EDGE_CURVE('E1038',#834,#825,#832,.T.);
#836=ORIENTED_EDGE('',*,*,#835,.F.);
#837=DIRECTION('',(0.,0.658644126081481,0.752454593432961));
#838=VECTOR('',#837,1.);
#839=CARTESIAN_POINT('',(0.,-7.88474053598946,-5.5945217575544));
#840=LINE('',#839,#838);
#841=EDGE_CURVE('E1008',#496,#834,#840,.T.);
#842=ORIENTED_EDGE('',*,*,#841,.F.);
#843=ORIENTED_EDGE('',*,*,#497,.F.);
#844=DIRECTION('',(0.,-0.880151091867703,-0.474693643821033));
#845=VECTOR('',#844,1.);
#846=CARTESIAN_POINT('',(0.,-7.20877524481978,-6.44215542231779));
#847=LINE('',#846,#845);
#848=CARTESIAN_POINT('',(0.,-4.60461298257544,-5.03764739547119));
#849=VERTEX_POINT('',#848);
#850=EDGE_CURVE('E995',#849,#492,#847,.T.);
#851=ORIENTED_EDGE('',*,*,#850,.F.);
#852=CARTESIAN_POINT('',(0.,0.,0.));
#853=DIRECTION('',(-1.,0.,0.));
#854=DIRECTION('',(0.,-0.781831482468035,0.623489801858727));
#855=AXIS2_PLACEMENT_3D('',#852,#853,#854);
#856=CIRCLE('',#855,6.82498);
#857=CARTESIAN_POINT('',(0.,-3.88672027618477,-5.61014772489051));
#858=VERTEX_POINT('',#857);
#859=EDGE_CURVE('E1001',#858,#849,#856,.T.);
#860=ORIENTED_EDGE('',*,*,#859,.F.);
#861=DIRECTION('',(0.,0.266940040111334,0.963713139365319));
#862=VECTOR('',#861,1.);
#863=CARTESIAN_POINT('',(0.,-4.67653373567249,-8.46155064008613));
#864=LINE('',#863,#862);
#865=EDGE_CURVE('E999',#469,#858,#864,.T.);
#866=ORIENTED_EDGE('',*,*,#865,.F.);
#867=ORIENTED_EDGE('',*,*,#470,.F.);
#868=DIRECTION('',(0.,-0.587026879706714,-0.809567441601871));
#869=VECTOR('',#868,1.);
#870=CARTESIAN_POINT('',(0.,-3.69973558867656,-8.93195183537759));
#871=LINE('',#870,#869);
#872=CARTESIAN_POINT('',(0.,-1.96285965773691,-6.53663016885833));
#873=VERTEX_POINT('',#872);
#874=EDGE_CURVE('E1015',#873,#465,#871,.T.);
#875=ORIENTED_EDGE('',*,*,#874,.F.);
#876=CARTESIAN_POINT('',(0.,0.,0.));
#877=DIRECTION('',(-1.,0.,0.));
#878=DIRECTION('',(0.,-0.974927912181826,0.222520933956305));
#879=AXIS2_PLACEMENT_3D('',#876,#877,#878);
#880=CIRCLE('',#879,6.82498);
#881=CARTESIAN_POINT('',(0.,-1.06766209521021,-6.74095317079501));
#882=VERTEX_POINT('',#881);
#883=EDGE_CURVE('E1021',#882,#873,#880,.T.);
#884=ORIENTED_EDGE('',*,*,#883,.F.);
#885=DIRECTION('',(0.,-0.177634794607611,0.984096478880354));
#886=VECTOR('',#885,1.);
#887=CARTESIAN_POINT('',(0.,-0.542082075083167,-9.65266564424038));
#888=LINE('',#887,#886);
#889=EDGE_CURVE('E1019',#538,#882,#888,.T.);
#890=ORIENTED_EDGE('',*,*,#889,.F.);
#891=ORIENTED_EDGE('',*,*,#539,.F.);
#892=DIRECTION('',(0.,-0.177634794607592,-0.984096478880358));
#893=VECTOR('',#892,1.);
#894=CARTESIAN_POINT('',(0.,0.54208207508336,-9.65266564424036));
#895=LINE('',#894,#893);
#896=CARTESIAN_POINT('',(0.,1.06766209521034,-6.74095317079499));
#897=VERTEX_POINT('',#896);
#898=EDGE_CURVE('E1049',#897,#536,#895,.T.);
#899=ORIENTED_EDGE('',*,*,#898,.F.);
#900=CARTESIAN_POINT('',(0.,0.,0.));
#901=DIRECTION('',(-1.,0.,0.));
#902=DIRECTION('',(0.,-0.974927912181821,-0.222520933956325));
#903=AXIS2_PLACEMENT_3D('',#900,#901,#902);
#904=CIRCLE('',#903,6.82498);
#905=CARTESIAN_POINT('',(0.,1.96285965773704,-6.53663016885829));
#906=VERTEX_POINT('',#905);
#907=EDGE_CURVE('E1055',#906,#897,#904,.T.);
#908=ORIENTED_EDGE('',*,*,#907,.F.);
#909=DIRECTION('',(0.,-0.58702687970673,0.809567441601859));
#910=VECTOR('',#909,1.);
#911=CARTESIAN_POINT('',(0.,3.69973558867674,-8.93195183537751));
#912=LINE('',#911,#910);
#913=EDGE_CURVE('E1053',#592,#906,#912,.T.);
#914=ORIENTED_EDGE('',*,*,#913,.F.);
#915=ORIENTED_EDGE('',*,*,#593,.F.);
#916=DIRECTION('',(0.,0.266940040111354,-0.963713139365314));
#917=VECTOR('',#916,1.);
#918=CARTESIAN_POINT('',(0.,4.67653373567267,-8.46155064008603));
#919=LINE('',#918,#917);
#920=CARTESIAN_POINT('',(0.,3.88672027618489,-5.61014772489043));
#921=VERTEX_POINT('',#920);
#922=EDGE_CURVE('E1085',#921,#590,#919,.T.);
#923=ORIENTED_EDGE('',*,*,#922,.F.);
#924=CARTESIAN_POINT('',(0.,0.,0.));
#925=DIRECTION('',(-1.,0.,0.));
#926=DIRECTION('',(0.,-0.781831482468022,-0.623489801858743));
#927=AXIS2_PLACEMENT_3D('',#924,#925,#926);
#928=CIRCLE('',#927,6.82498);
#929=CARTESIAN_POINT('',(0.,4.60461298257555,-5.03764739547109));
#930=VERTEX_POINT('',#929);
#931=EDGE_CURVE('E1090',#930,#921,#928,.T.);
#932=ORIENTED_EDGE('',*,*,#931,.F.);
#933=DIRECTION('',(0.,-0.880151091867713,0.474693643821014));
#934=VECTOR('',#933,1.);
#935=CARTESIAN_POINT('',(0.,7.20877524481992,-6.44215542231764));
#936=LINE('',#935,#934);
#937=EDGE_CURVE('E1078',#577,#930,#936,.T.);
#938=ORIENTED_EDGE('',*,*,#937,.F.);
#939=ORIENTED_EDGE('',*,*,#578,.F.);
#940=DIRECTION('',(0.,0.658644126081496,-0.752454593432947));
#941=VECTOR('',#940,1.);
#942=CARTESIAN_POINT('',(0.,7.88474053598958,-5.59452175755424));
#943=LINE('',#942,#941);
#944=CARTESIAN_POINT('',(0.,5.935965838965,-3.36818371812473));
#945=VERTEX_POINT('',#944);
#946=EDGE_CURVE('E1067',#945,#573,#943,.T.);
#947=ORIENTED_EDGE('',*,*,#946,.F.);
#948=CARTESIAN_POINT('',(0.,0.,0.));
#949=DIRECTION('',(-1.,0.,0.));
#950=DIRECTION('',(0.,-0.433883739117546,-0.900968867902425));
#951=AXIS2_PLACEMENT_3D('',#948,#949,#950);
#952=CIRCLE('',#951,6.82498);
#953=CARTESIAN_POINT('',(0.,6.3343662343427,-2.54089677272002));
#954=VERTEX_POINT('',#953);
#955=EDGE_CURVE('E1072',#954,#945,#952,.T.);
#956=ORIENTED_EDGE('',*,*,#955,.F.);
#957=DIRECTION('',(0.,-0.998950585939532,0.0458009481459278));
#958=VECTOR('',#957,1.);
#959=CARTESIAN_POINT('',(0.,9.29002855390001,-2.67641112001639));
#960=LINE('',#959,#958);
#961=CARTESIAN_POINT('',(0.,8.81649722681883,-2.65470015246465));
#962=VERTEX_POINT('',#961);
#963=EDGE_CURVE('E880',#962,#954,#960,.T.);
#964=ORIENTED_EDGE('',*,*,#963,.F.);
#965=CARTESIAN_POINT('',(0.,9.09522075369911,-1.43353259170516));
#966=VERTEX_POINT('',#965);
#967=EDGE_CURVE('E1229',#966,#962,#305,.T.);
#968=ORIENTED_EDGE('',*,*,#967,.F.);
#969=DIRECTION('',(0.,0.919895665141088,-0.392163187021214));
#970=VECTOR('',#969,1.);
#971=CARTESIAN_POINT('',(0.,9.53127777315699,-1.61942922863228));
#972=LINE('',#971,#970);
#973=CARTESIAN_POINT('',(0.,6.80952056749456,-0.45910961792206));
#974=VERTEX_POINT('',#973);
#975=EDGE_CURVE('E1197',#974,#966,#972,.T.);
#976=ORIENTED_EDGE('',*,*,#975,.F.);
#977=CARTESIAN_POINT('',(0.,0.,0.));
#978=DIRECTION('',(-1.,0.,0.));
#979=DIRECTION('',(0.,0.,-1.));
#980=AXIS2_PLACEMENT_3D('',#977,#978,#979);
#981=CIRCLE('',#980,6.82498);
#982=CARTESIAN_POINT('',(0.,6.80952056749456,0.45910961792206));
#983=VERTEX_POINT('',#982);
#984=EDGE_CURVE('E1202',#983,#974,#981,.T.);
#985=ORIENTED_EDGE('',*,*,#984,.F.);
#986=DIRECTION('',(0.,-0.919895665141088,-0.392163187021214));
#987=VECTOR('',#986,1.);
#988=CARTESIAN_POINT('',(0.,9.53127777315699,1.61942922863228));
#989=LINE('',#988,#987);
#990=EDGE_CURVE('E1192',#631,#983,#989,.T.);
#991=ORIENTED_EDGE('',*,*,#990,.F.);
#992=ORIENTED_EDGE('',*,*,#632,.F.);
#993=DIRECTION('',(0.,0.998950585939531,0.0458009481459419));
#994=VECTOR('',#993,1.);
#995=CARTESIAN_POINT('',(0.,9.29002855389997,2.67641112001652));
#996=LINE('',#995,#994);
#997=CARTESIAN_POINT('',(0.,6.33436623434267,2.54089677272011));
#998=VERTEX_POINT('',#997);
#999=EDGE_CURVE('E1173',#998,#627,#996,.T.);
#1000=ORIENTED_EDGE('',*,*,#999,.F.);
#1001=CARTESIAN_POINT('',(0.,0.,0.));
#1002=DIRECTION('',(-1.,0.,0.));
#1003=DIRECTION('',(0.,0.433883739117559,-0.900968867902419));
#1004=AXIS2_PLACEMENT_3D('',#1001,#1002,#1003);
#1005=CIRCLE('',#1004,6.82498);
#1006=CARTESIAN_POINT('',(0.,5.93596583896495,3.36818371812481));
#1007=VERTEX_POINT('',#1006);
#1008=EDGE_CURVE('E1178',#1007,#998,#1005,.T.);
#1009=ORIENTED_EDGE('',*,*,#1008,.F.);
#1010=DIRECTION('',(0.,-0.658644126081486,-0.752454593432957));
#1011=VECTOR('',#1010,1.);
#1012=CARTESIAN_POINT('',(0.,7.8847405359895,5.59452175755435));
#1013=LINE('',#1012,#1011);
#1014=EDGE_CURVE('E1168',#307,#1007,#1013,.T.);
#1015=ORIENTED_EDGE('',*,*,#1014,.F.);
#1016=EDGE_LOOP('',(#675,#683,#692,#698,#699,#707,#716,#722,#723,#731,#740,#746,#747,#755,#764,
#770,#771,#779,#788,#794,#795,#803,#812,#818,#819,#827,#836,#842,#843,#851,#860,#866,#867,#875,
#884,#890,#891,#899,#908,#914,#915,#923,#932,#938,#939,#947,#956,#964,#968,#976,#985,#991,#992,
#1000,#1009,#1015));
#1017=FACE_BOUND('',#1016,.T.);
#1018=ORIENTED_EDGE('',*,*,#50,.T.);
#1019=DIRECTION('',(0.,-0.435890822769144,-0.899999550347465));
#1020=VECTOR('',#1019,1.);
#1021=CARTESIAN_POINT('',(0.,1.14830934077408,4.78305263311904));
#1022=LINE('',#1021,#1020);
#1023=CARTESIAN_POINT('',(0.,1.14830934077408,4.78305263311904));
#1024=VERTEX_POINT('',#1023);
#1025=EDGE_CURVE('E654',#1024,#40,#1022,.T.);
#1026=ORIENTED_EDGE('',*,*,#1025,.F.);
#1027=CARTESIAN_POINT('',(0.,0.,0.));
#1028=DIRECTION('',(1.,0.,0.));
#1029=DIRECTION('',(0.,0.951056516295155,-0.309016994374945));
#1030=AXIS2_PLACEMENT_3D('',#1027,#1028,#1029);
#1031=CIRCLE('',#1030,4.918964);
#1032=CARTESIAN_POINT('',(0.,1.8824060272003,4.54453016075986));
#1033=VERTEX_POINT('',#1032);
#1034=EDGE_CURVE('E636',#1033,#1024,#1031,.T.);
#1035=ORIENTED_EDGE('',*,*,#1034,.F.);
#1036=DIRECTION('',(0.,0.176363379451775,0.984325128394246));
#1037=VECTOR('',#1036,1.);
#1038=CARTESIAN_POINT('',(0.,1.8824060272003,4.54453016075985));
#1039=LINE('',#1038,#1037);
#1040=EDGE_CURVE('E658',#251,#1033,#1039,.T.);
#1041=ORIENTED_EDGE('',*,*,#1040,.F.);
#1042=ORIENTED_EDGE('',*,*,#254,.T.);
#1043=DIRECTION('',(0.,-0.881649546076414,-0.471904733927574));
#1044=VECTOR('',#1043,1.);
#1045=CARTESIAN_POINT('',(0.,3.74040957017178,3.19461156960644));
#1046=LINE('',#1045,#1044);
#1047=CARTESIAN_POINT('',(0.,3.74040957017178,3.19461156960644));
#1048=VERTEX_POINT('',#1047);
#1049=EDGE_CURVE('E835',#1048,#253,#1046,.T.);
#1050=ORIENTED_EDGE('',*,*,#1049,.F.);
#1051=CARTESIAN_POINT('',(0.,0.,0.));
#1052=DIRECTION('',(1.,0.,0.));
#1053=DIRECTION('',(0.,0.587785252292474,-0.809016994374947));
#1054=AXIS2_PLACEMENT_3D('',#1051,#1052,#1053);
#1055=CIRCLE('',#1054,4.918964);
#1056=CARTESIAN_POINT('',(0.,4.19410627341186,2.57015162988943));
#1057=VERTEX_POINT('',#1056);
#1058=EDGE_CURVE('E840',#1057,#1048,#1055,.T.);
#1059=ORIENTED_EDGE('',*,*,#1058,.F.);
#1060=DIRECTION('',(0.,0.721252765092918,0.692671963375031));
#1061=VECTOR('',#1060,1.);
#1062=CARTESIAN_POINT('',(0.,4.19410627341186,2.57015162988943));
#1063=LINE('',#1062,#1061);
#1064=EDGE_CURVE('E830',#644,#1057,#1063,.T.);
#1065=ORIENTED_EDGE('',*,*,#1064,.F.);
#1066=ORIENTED_EDGE('',*,*,#647,.T.);
#1067=DIRECTION('',(0.,-0.990648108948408,0.136441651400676));
#1068=VECTOR('',#1067,1.);
#1069=CARTESIAN_POINT('',(0.,4.90380047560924,0.385937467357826));
#1070=LINE('',#1069,#1068);
#1071=CARTESIAN_POINT('',(0.,4.90380047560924,0.385937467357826));
#1072=VERTEX_POINT('',#1071);
#1073=EDGE_CURVE('E860',#1072,#646,#1070,.T.);
#1074=ORIENTED_EDGE('',*,*,#1073,.F.);
#1075=CARTESIAN_POINT('',(0.,0.,0.));
#1076=DIRECTION('',(1.,0.,0.));
#1077=DIRECTION('',(0.,0.,-1.));
#1078=AXIS2_PLACEMENT_3D('',#1075,#1076,#1077);
#1079=CIRCLE('',#1078,4.918964);
#1080=CARTESIAN_POINT('',(0.,4.90380047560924,-0.385937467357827));
#1081=VERTEX_POINT('',#1080);
#1082=EDGE_CURVE('E865',#1081,#1072,#1079,.T.);
#1083=ORIENTED_EDGE('',*,*,#1082,.F.);
#1084=DIRECTION('',(0.,0.990648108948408,0.136441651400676));
#1085=VECTOR('',#1084,1.);
#1086=CARTESIAN_POINT('',(0.,4.90380047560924,-0.385937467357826));
#1087=LINE('',#1086,#1085);
#1088=EDGE_CURVE('E855',#238,#1081,#1087,.T.);
#1089=ORIENTED_EDGE('',*,*,#1088,.F.);
#1090=ORIENTED_EDGE('',*,*,#239,.T.);
#1091=DIRECTION('',(0.,-0.721252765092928,0.692671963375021));
#1092=VECTOR('',#1091,1.);
#1093=CARTESIAN_POINT('',(0.,4.1941062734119,-2.57015162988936));
#1094=LINE('',#1093,#1092);
#1095=CARTESIAN_POINT('',(0.,4.1941062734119,-2.57015162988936));
#1096=VERTEX_POINT('',#1095);
#1097=EDGE_CURVE('E772',#1096,#234,#1094,.T.);
#1098=ORIENTED_EDGE('',*,*,#1097,.F.);
#1099=CARTESIAN_POINT('',(0.,0.,0.));
#1100=DIRECTION('',(1.,0.,0.));
#1101=DIRECTION('',(0.,-0.587785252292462,-0.809016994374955));
#1102=AXIS2_PLACEMENT_3D('',#1099,#1100,#1101);
#1103=CIRCLE('',#1102,4.918964);
#1104=CARTESIAN_POINT('',(0.,3.74040957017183,-3.19461156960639));
#1105=VERTEX_POINT('',#1104);
#1106=EDGE_CURVE('E778',#1105,#1096,#1103,.T.);
#1107=ORIENTED_EDGE('',*,*,#1106,.F.);
#1108=DIRECTION('',(0.,0.88164954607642,-0.471904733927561));
#1109=VECTOR('',#1108,1.);
#1110=CARTESIAN_POINT('',(0.,3.74040957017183,-3.19461156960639));
#1111=LINE('',#1110,#1109);
#1112=EDGE_CURVE('E776',#211,#1105,#1111,.T.);
#1113=ORIENTED_EDGE('',*,*,#1112,.F.);
#1114=ORIENTED_EDGE('',*,*,#212,.T.);
#1115=DIRECTION('',(0.,-0.176363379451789,0.984325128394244));
#1116=VECTOR('',#1115,1.);
#1117=CARTESIAN_POINT('',(0.,1.88240602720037,-4.54453016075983));
#1118=LINE('',#1117,#1116);
#1119=CARTESIAN_POINT('',(0.,1.88240602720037,-4.54453016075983));
#1120=VERTEX_POINT('',#1119);
#1121=EDGE_CURVE('E754',#1120,#207,#1118,.T.);
#1122=ORIENTED_EDGE('',*,*,#1121,.F.);
#1123=CARTESIAN_POINT('',(0.,0.,0.));
#1124=DIRECTION('',(1.,0.,0.));
#1125=DIRECTION('',(0.,-0.95105651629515,-0.309016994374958));
#1126=AXIS2_PLACEMENT_3D('',#1123,#1124,#1125);
#1127=CIRCLE('',#1126,4.918964);
#1128=CARTESIAN_POINT('',(0.,1.14830934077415,-4.78305263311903));
#1129=VERTEX_POINT('',#1128);
#1130=EDGE_CURVE('E760',#1129,#1120,#1127,.T.);
#1131=ORIENTED_EDGE('',*,*,#1130,.F.);
#1132=DIRECTION('',(0.,0.435890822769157,-0.899999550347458));
#1133=VECTOR('',#1132,1.);
#1134=CARTESIAN_POINT('',(0.,1.14830934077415,-4.78305263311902));
#1135=LINE('',#1134,#1133);
#1136=EDGE_CURVE('E758',#184,#1129,#1135,.T.);
#1137=ORIENTED_EDGE('',*,*,#1136,.F.);
#1138=ORIENTED_EDGE('',*,*,#185,.T.);
#1139=DIRECTION('',(0.,0.435890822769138,0.899999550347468));
#1140=VECTOR('',#1139,1.);
#1141=CARTESIAN_POINT('',(0.,-1.14830934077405,-4.78305263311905));
#1142=LINE('',#1141,#1140);
#1143=CARTESIAN_POINT('',(0.,-1.14830934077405,-4.78305263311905));
#1144=VERTEX_POINT('',#1143);
#1145=EDGE_CURVE('E736',#1144,#180,#1142,.T.);
#1146=ORIENTED_EDGE('',*,*,#1145,.F.);
#1147=CARTESIAN_POINT('',(0.,0.,0.));
#1148=DIRECTION('',(1.,0.,0.));
#1149=DIRECTION('',(0.,-0.951056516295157,0.309016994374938));
#1150=AXIS2_PLACEMENT_3D('',#1147,#1148,#1149);
#1151=CIRCLE('',#1150,4.918964);
#1152=CARTESIAN_POINT('',(0.,-1.88240602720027,-4.54453016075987));
#1153=VERTEX_POINT('',#1152);
#1154=EDGE_CURVE('E742',#1153,#1144,#1151,.T.);
#1155=ORIENTED_EDGE('',*,*,#1154,.F.);
#1156=DIRECTION('',(0.,-0.176363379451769,-0.984325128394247));
#1157=VECTOR('',#1156,1.);
#1158=CARTESIAN_POINT('',(0.,-1.88240602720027,-4.54453016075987));
#1159=LINE('',#1158,#1157);
#1160=EDGE_CURVE('E740',#157,#1153,#1159,.T.);
#1161=ORIENTED_EDGE('',*,*,#1160,.F.);
#1162=ORIENTED_EDGE('',*,*,#158,.T.);
#1163=DIRECTION('',(0.,0.88164954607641,0.47190473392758));
#1164=VECTOR('',#1163,1.);
#1165=CARTESIAN_POINT('',(0.,-3.74040957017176,-3.19461156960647));
#1166=LINE('',#1165,#1164);
#1167=CARTESIAN_POINT('',(0.,-3.74040957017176,-3.19461156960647));
#1168=VERTEX_POINT('',#1167);
#1169=EDGE_CURVE('E718',#1168,#153,#1166,.T.);
#1170=ORIENTED_EDGE('',*,*,#1169,.F.);
#1171=CARTESIAN_POINT('',(0.,0.,0.));
#1172=DIRECTION('',(1.,0.,0.));
#1173=DIRECTION('',(0.,-0.58778525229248,0.809016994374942));
#1174=AXIS2_PLACEMENT_3D('',#1171,#1172,#1173);
#1175=CIRCLE('',#1174,4.918964);
#1176=CARTESIAN_POINT('',(0.,-4.19410627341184,-2.57015162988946));
#1177=VERTEX_POINT('',#1176);
#1178=EDGE_CURVE('E724',#1177,#1168,#1175,.T.);
#1179=ORIENTED_EDGE('',*,*,#1178,.F.);
#1180=DIRECTION('',(0.,-0.721252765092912,-0.692671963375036));
#1181=VECTOR('',#1180,1.);
#1182=CARTESIAN_POINT('',(0.,-4.19410627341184,-2.57015162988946));
#1183=LINE('',#1182,#1181);
#1184=EDGE_CURVE('E722',#130,#1177,#1183,.T.);
#1185=ORIENTED_EDGE('',*,*,#1184,.F.);
#1186=ORIENTED_EDGE('',*,*,#131,.T.);
#1187=DIRECTION('',(0.,0.990648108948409,-0.136441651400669));
#1188=VECTOR('',#1187,1.);
#1189=CARTESIAN_POINT('',(0.,-4.90380047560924,-0.385937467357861));
#1190=LINE('',#1189,#1188);
#1191=CARTESIAN_POINT('',(0.,-4.90380047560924,-0.385937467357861));
#1192=VERTEX_POINT('',#1191);
#1193=EDGE_CURVE('E700',#1192,#126,#1190,.T.);
#1194=ORIENTED_EDGE('',*,*,#1193,.F.);
#1195=CARTESIAN_POINT('',(0.,0.,0.));
#1196=DIRECTION('',(1.,0.,0.));
#1197=DIRECTION('',(0.,0.,1.));
#1198=AXIS2_PLACEMENT_3D('',#1195,#1196,#1197);
#1199=CIRCLE('',#1198,4.918964);
#1200=CARTESIAN_POINT('',(0.,-4.90380047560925,0.385937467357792));
#1201=VERTEX_POINT('',#1200);
#1202=EDGE_CURVE('E706',#1201,#1192,#1199,.T.);
#1203=ORIENTED_EDGE('',*,*,#1202,.F.);
#1204=DIRECTION('',(0.,-0.990648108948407,-0.136441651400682));
#1205=VECTOR('',#1204,1.);
#1206=CARTESIAN_POINT('',(0.,-4.90380047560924,0.385937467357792));
#1207=LINE('',#1206,#1205);
#1208=EDGE_CURVE('E704',#103,#1201,#1207,.T.);
#1209=ORIENTED_EDGE('',*,*,#1208,.F.);
#1210=ORIENTED_EDGE('',*,*,#104,.T.);
#1211=DIRECTION('',(0.,0.721252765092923,-0.692671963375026));
#1212=VECTOR('',#1211,1.);
#1213=CARTESIAN_POINT('',(0.,-4.19410627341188,2.5701516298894));
#1214=LINE('',#1213,#1212);
#1215=CARTESIAN_POINT('',(0.,-4.19410627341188,2.5701516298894));
#1216=VERTEX_POINT('',#1215);
#1217=EDGE_CURVE('E682',#1216,#99,#1214,.T.);
#1218=ORIENTED_EDGE('',*,*,#1217,.F.);
#1219=CARTESIAN_POINT('',(0.,0.,0.));
#1220=DIRECTION('',(1.,0.,0.));
#1221=DIRECTION('',(0.,0.587785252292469,0.809016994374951));
#1222=AXIS2_PLACEMENT_3D('',#1219,#1220,#1221);
#1223=CIRCLE('',#1222,4.918964);
#1224=CARTESIAN_POINT('',(0.,-3.74040957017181,3.19461156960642));
#1225=VERTEX_POINT('',#1224);
#1226=EDGE_CURVE('E688',#1225,#1216,#1223,.T.);
#1227=ORIENTED_EDGE('',*,*,#1226,.F.);
#1228=DIRECTION('',(0.,-0.881649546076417,0.471904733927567));
#1229=VECTOR('',#1228,1.);
#1230=CARTESIAN_POINT('',(0.,-3.74040957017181,3.19461156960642));
#1231=LINE('',#1230,#1229);
#1232=EDGE_CURVE('E686',#76,#1225,#1231,.T.);
#1233=ORIENTED_EDGE('',*,*,#1232,.F.);
#1234=ORIENTED_EDGE('',*,*,#77,.T.);
#1235=DIRECTION('',(0.,0.176363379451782,-0.984325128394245));
#1236=VECTOR('',#1235,1.);
#1237=CARTESIAN_POINT('',(0.,-1.88240602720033,4.54453016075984));
#1238=LINE('',#1237,#1236);
#1239=CARTESIAN_POINT('',(0.,-1.88240602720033,4.54453016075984));
#1240=VERTEX_POINT('',#1239);
#1241=EDGE_CURVE('E665',#1240,#72,#1238,.T.);
#1242=ORIENTED_EDGE('',*,*,#1241,.F.);
#1243=CARTESIAN_POINT('',(0.,0.,0.));
#1244=DIRECTION('',(1.,0.,0.));
#1245=DIRECTION('',(0.,0.951056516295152,0.309016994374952));
#1246=AXIS2_PLACEMENT_3D('',#1243,#1244,#1245);
#1247=CIRCLE('',#1246,4.918964);
#1248=CARTESIAN_POINT('',(0.,-1.14830934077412,4.78305263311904));
#1249=VERTEX_POINT('',#1248);
#1250=EDGE_CURVE('E671',#1249,#1240,#1247,.T.);
#1251=ORIENTED_EDGE('',*,*,#1250,.F.);
#1252=DIRECTION('',(0.,-0.435890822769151,0.899999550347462));
#1253=VECTOR('',#1252,1.);
#1254=CARTESIAN_POINT('',(0.,-1.14830934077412,4.78305263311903));
#1255=LINE('',#1254,#1253);
#1256=EDGE_CURVE('E669',#49,#1249,#1255,.T.);
#1257=ORIENTED_EDGE('',*,*,#1256,.F.);
#1258=EDGE_LOOP('',(#1018,#1026,#1035,#1041,#1042,#1050,#1059,#1065,#1066,#1074,#1083,#1089,
#1090,#1098,#1107,#1113,#1114,#1122,#1131,#1137,#1138,#1146,#1155,#1161,#1162,#1170,#1179,#1185,
#1186,#1194,#1203,#1209,#1210,#1218,#1227,#1233,#1234,#1242,#1251,#1257));
#1259=FACE_BOUND('',#1258,.T.);
#1260=ADVANCED_FACE('F1347',(#1017,#1259),#674,.F.);
#1261=ORIENTED_EDGE('',*,*,#967,.T.);
#1262=DIRECTION('',(-1.,0.,0.));
#1263=VECTOR('',#1262,1.);
#1264=CARTESIAN_POINT('',(-34.9249999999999,8.81649722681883,-2.65470015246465));
#1265=LINE('',#1264,#1263);
#1266=CARTESIAN_POINT('',(-0.812800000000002,8.81649722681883,-2.65470015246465));
#1267=VERTEX_POINT('',#1266);
#1268=EDGE_CURVE('E1102',#962,#1267,#1265,.T.);
#1269=ORIENTED_EDGE('',*,*,#1268,.T.);
#1270=CARTESIAN_POINT('',(-0.812800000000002,9.09522075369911,-1.43353259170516));
#1271=VERTEX_POINT('',#1270);
#1272=EDGE_CURVE('E1223',#1271,#1267,#286,.T.);
#1273=ORIENTED_EDGE('',*,*,#1272,.F.);
#1274=DIRECTION('',(-1.,0.,0.));
#1275=VECTOR('',#1274,1.);
#1276=CARTESIAN_POINT('',(-34.9249999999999,9.09522075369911,-1.43353259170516));
#1277=LINE('',#1276,#1275);
#1278=EDGE_CURVE('E1213',#1271,#966,#1277,.F.);
#1279=ORIENTED_EDGE('',*,*,#1278,.T.);
#1280=EDGE_LOOP('',(#1261,#1269,#1273,#1279));
#1281=FACE_BOUND('',#1280,.T.);
#1282=ADVANCED_FACE('F1425',(#1281),#281,.T.);
#1283=CARTESIAN_POINT('',(-0.812800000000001,9.2075,0.));
#1284=DIRECTION('',(1.,0.,0.));
#1285=DIRECTION('',(0.,0.,-1.));
#1286=AXIS2_PLACEMENT_3D('',#1283,#1284,#1285);
#1287=PLANE('',#1286);
#1288=CARTESIAN_POINT('',(-0.812800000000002,0.,0.));
#1289=DIRECTION('',(1.,0.,0.));
#1290=DIRECTION('',(0.,0.951056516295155,-0.309016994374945));
#1291=AXIS2_PLACEMENT_3D('',#1288,#1289,#1290);
#1292=CIRCLE('',#1291,4.918964);
#1293=CARTESIAN_POINT('',(-0.812800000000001,1.8824060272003,4.54453016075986));
#1294=VERTEX_POINT('',#1293);
#1295=CARTESIAN_POINT('',(-0.812800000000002,1.14830934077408,4.78305263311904));
#1296=VERTEX_POINT('',#1295);
#1297=EDGE_CURVE('E54',#1294,#1296,#1292,.T.);
#1298=ORIENTED_EDGE('',*,*,#1297,.T.);
#1299=DIRECTION('',(0.,-0.435890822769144,-0.899999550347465));
#1300=VECTOR('',#1299,1.);
#1301=CARTESIAN_POINT('',(-0.812800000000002,1.14830934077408,4.78305263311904));
#1302=LINE('',#1301,#1300);
#1303=EDGE_CURVE('E643',#1296,#32,#1302,.T.);
#1304=ORIENTED_EDGE('',*,*,#1303,.T.);
#1305=ORIENTED_EDGE('',*,*,#33,.F.);
#1306=DIRECTION('',(0.,-0.435890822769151,0.899999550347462));
#1307=VECTOR('',#1306,1.);
#1308=CARTESIAN_POINT('',(-0.812800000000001,2.69570175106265,-3.15381612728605));
#1309=LINE('',#1308,#1307);
#1310=CARTESIAN_POINT('',(-0.812800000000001,-1.14830934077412,4.78305263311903));
#1311=VERTEX_POINT('',#1310);
#1312=EDGE_CURVE('E47',#30,#1311,#1309,.T.);
#1313=ORIENTED_EDGE('',*,*,#1312,.T.);
#1314=CARTESIAN_POINT('',(-0.812800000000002,0.,0.));
#1315=DIRECTION('',(1.,0.,0.));
#1316=DIRECTION('',(0.,0.951056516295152,0.309016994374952));
#1317=AXIS2_PLACEMENT_3D('',#1314,#1315,#1316);
#1318=CIRCLE('',#1317,4.918964);
#1319=CARTESIAN_POINT('',(-0.812800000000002,-1.88240602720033,4.54453016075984));
#1320=VERTEX_POINT('',#1319);
#1321=EDGE_CURVE('E62',#1311,#1320,#1318,.T.);
#1322=ORIENTED_EDGE('',*,*,#1321,.T.);
#1323=DIRECTION('',(0.,0.176363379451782,-0.984325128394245));
#1324=VECTOR('',#1323,1.);
#1325=CARTESIAN_POINT('',(-0.812800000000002,-1.88240602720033,4.54453016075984));
#1326=LINE('',#1325,#1324);
#1327=EDGE_CURVE('E664',#1320,#64,#1326,.T.);
#1328=ORIENTED_EDGE('',*,*,#1327,.T.);
#1329=ORIENTED_EDGE('',*,*,#65,.F.);
#1330=DIRECTION('',(0.,-0.881649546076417,0.471904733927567));
#1331=VECTOR('',#1330,1.);
#1332=CARTESIAN_POINT('',(-0.812800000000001,7.65321003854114,-2.90384677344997));
#1333=LINE('',#1332,#1331);
#1334=CARTESIAN_POINT('',(-0.812800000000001,-3.74040957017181,3.19461156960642));
#1335=VERTEX_POINT('',#1334);
#1336=EDGE_CURVE('E1303',#62,#1335,#1333,.T.);
#1337=ORIENTED_EDGE('',*,*,#1336,.T.);
#1338=CARTESIAN_POINT('',(-0.812800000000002,0.,0.));
#1339=DIRECTION('',(1.,0.,0.));
#1340=DIRECTION('',(0.,0.587785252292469,0.809016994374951));
#1341=AXIS2_PLACEMENT_3D('',#1338,#1339,#1340);
#1342=CIRCLE('',#1341,4.918964);
#1343=CARTESIAN_POINT('',(-0.812800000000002,-4.19410627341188,2.5701516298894));
#1344=VERTEX_POINT('',#1343);
#1345=EDGE_CURVE('E678',#1335,#1344,#1342,.T.);
#1346=ORIENTED_EDGE('',*,*,#1345,.T.);
#1347=DIRECTION('',(0.,0.721252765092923,-0.692671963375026));
#1348=VECTOR('',#1347,1.);
#1349=CARTESIAN_POINT('',(-0.812800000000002,-4.19410627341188,2.5701516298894));
#1350=LINE('',#1349,#1348);
#1351=EDGE_CURVE('E681',#1344,#91,#1350,.T.);
#1352=ORIENTED_EDGE('',*,*,#1351,.T.);
#1353=ORIENTED_EDGE('',*,*,#92,.F.);
#1354=DIRECTION('',(0.,-0.990648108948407,-0.136441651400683));
#1355=VECTOR('',#1354,1.);
#1356=CARTESIAN_POINT('',(-0.812800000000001,8.89263396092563,2.28611602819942));
#1357=LINE('',#1356,#1355);
#1358=CARTESIAN_POINT('',(-0.812800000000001,-4.90380047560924,0.385937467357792));
#1359=VERTEX_POINT('',#1358);
#1360=EDGE_CURVE('E1300',#89,#1359,#1357,.T.);
#1361=ORIENTED_EDGE('',*,*,#1360,.T.);
#1362=CARTESIAN_POINT('',(-0.812800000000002,0.,0.));
#1363=DIRECTION('',(1.,0.,0.));
#1364=DIRECTION('',(0.,0.,1.));
#1365=AXIS2_PLACEMENT_3D('',#1362,#1363,#1364);
#1366=CIRCLE('',#1365,4.918964);
#1367=CARTESIAN_POINT('',(-0.812800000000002,-4.90380047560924,-0.385937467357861));
#1368=VERTEX_POINT('',#1367);
#1369=EDGE_CURVE('E696',#1359,#1368,#1366,.T.);
#1370=ORIENTED_EDGE('',*,*,#1369,.T.);
#1371=DIRECTION('',(0.,0.990648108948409,-0.136441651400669));
#1372=VECTOR('',#1371,1.);
#1373=CARTESIAN_POINT('',(-0.812800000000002,-4.90380047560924,-0.385937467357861));
#1374=LINE('',#1373,#1372);
#1375=EDGE_CURVE('E699',#1368,#118,#1374,.T.);
#1376=ORIENTED_EDGE('',*,*,#1375,.T.);
#1377=ORIENTED_EDGE('',*,*,#119,.F.);
#1378=DIRECTION('',(0.,-0.721252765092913,-0.692671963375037));
#1379=VECTOR('',#1378,1.);
#1380=CARTESIAN_POINT('',(-0.812800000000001,4.06150978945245,5.35832235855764));
#1381=LINE('',#1380,#1379);
#1382=CARTESIAN_POINT('',(-0.812800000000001,-4.19410627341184,-2.57015162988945));
#1383=VERTEX_POINT('',#1382);
#1384=EDGE_CURVE('E1297',#116,#1383,#1381,.T.);
#1385=ORIENTED_EDGE('',*,*,#1384,.T.);
#1386=CARTESIAN_POINT('',(-0.812800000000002,0.,0.));
#1387=DIRECTION('',(1.,0.,0.));
#1388=DIRECTION('',(0.,-0.58778525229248,0.809016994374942));
#1389=AXIS2_PLACEMENT_3D('',#1386,#1387,#1388);
#1390=CIRCLE('',#1389,4.918964);
#1391=CARTESIAN_POINT('',(-0.812800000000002,-3.74040957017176,-3.19461156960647));
#1392=VERTEX_POINT('',#1391);
#1393=EDGE_CURVE('E714',#1383,#1392,#1390,.T.);
#1394=ORIENTED_EDGE('',*,*,#1393,.T.);
#1395=DIRECTION('',(0.,0.88164954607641,0.47190473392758));
#1396=VECTOR('',#1395,1.);
#1397=CARTESIAN_POINT('',(-0.812800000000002,-3.74040957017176,-3.19461156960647));
#1398=LINE('',#1397,#1396);
#1399=EDGE_CURVE('E717',#1392,#145,#1398,.T.);
#1400=ORIENTED_EDGE('',*,*,#1399,.T.);
#1401=ORIENTED_EDGE('',*,*,#146,.F.);
#1402=DIRECTION('',(0.,-0.176363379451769,-0.984325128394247));
#1403=VECTOR('',#1402,1.);
#1404=CARTESIAN_POINT('',(-0.812800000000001,-0.748539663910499,1.78384230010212));
#1405=LINE('',#1404,#1403);
#1406=CARTESIAN_POINT('',(-0.812800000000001,-1.88240602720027,-4.54453016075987));
#1407=VERTEX_POINT('',#1406);
#1408=EDGE_CURVE('E1294',#143,#1407,#1405,.T.);
#1409=ORIENTED_EDGE('',*,*,#1408,.T.);
#1410=CARTESIAN_POINT('',(-0.812800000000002,0.,0.));
#1411=DIRECTION('',(1.,0.,0.));
#1412=DIRECTION('',(0.,-0.951056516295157,0.309016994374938));
#1413=AXIS2_PLACEMENT_3D('',#1410,#1411,#1412);
#1414=CIRCLE('',#1413,4.918964);
#1415=CARTESIAN_POINT('',(-0.812800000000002,-1.14830934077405,-4.78305263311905));
#1416=VERTEX_POINT('',#1415);
#1417=EDGE_CURVE('E732',#1407,#1416,#1414,.T.);
#1418=ORIENTED_EDGE('',*,*,#1417,.T.);
#1419=DIRECTION('',(0.,0.435890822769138,0.899999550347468));
#1420=VECTOR('',#1419,1.);
#1421=CARTESIAN_POINT('',(-0.812800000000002,-1.14830934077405,-4.78305263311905));
#1422=LINE('',#1421,#1420);
#1423=EDGE_CURVE('E735',#1416,#172,#1422,.T.);
#1424=ORIENTED_EDGE('',*,*,#1423,.T.);
#1425=ORIENTED_EDGE('',*,*,#173,.F.);
#1426=DIRECTION('',(0.,0.435890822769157,-0.899999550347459));
#1427=VECTOR('',#1426,1.);
#1428=CARTESIAN_POINT('',(-0.812800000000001,0.803163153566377,-4.07041681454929));
#1429=LINE('',#1428,#1427);
#1430=CARTESIAN_POINT('',(-0.812800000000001,1.14830934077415,-4.78305263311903));
#1431=VERTEX_POINT('',#1430);
#1432=EDGE_CURVE('E1291',#170,#1431,#1429,.T.);
#1433=ORIENTED_EDGE('',*,*,#1432,.T.);
#1434=CARTESIAN_POINT('',(-0.812800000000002,0.,0.));
#1435=DIRECTION('',(1.,0.,0.));
#1436=DIRECTION('',(0.,-0.95105651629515,-0.309016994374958));
#1437=AXIS2_PLACEMENT_3D('',#1434,#1435,#1436);
#1438=CIRCLE('',#1437,4.918964);
#1439=CARTESIAN_POINT('',(-0.812800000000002,1.88240602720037,-4.54453016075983));
#1440=VERTEX_POINT('',#1439);
#1441=EDGE_CURVE('E750',#1431,#1440,#1438,.T.);
#1442=ORIENTED_EDGE('',*,*,#1441,.T.);
#1443=DIRECTION('',(0.,-0.176363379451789,0.984325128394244));
#1444=VECTOR('',#1443,1.);
#1445=CARTESIAN_POINT('',(-0.812800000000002,1.88240602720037,-4.54453016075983));
#1446=LINE('',#1445,#1444);
#1447=EDGE_CURVE('E753',#1440,#199,#1446,.T.);
#1448=ORIENTED_EDGE('',*,*,#1447,.T.);
#1449=ORIENTED_EDGE('',*,*,#200,.F.);
#1450=DIRECTION('',(0.,0.88164954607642,-0.471904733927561));
#1451=VECTOR('',#1450,1.);
#1452=CARTESIAN_POINT('',(-0.812800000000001,6.6608785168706,-4.75779858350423));
#1453=LINE('',#1452,#1451);
#1454=CARTESIAN_POINT('',(-0.812800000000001,3.74040957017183,-3.19461156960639));
#1455=VERTEX_POINT('',#1454);
#1456=EDGE_CURVE('E1288',#197,#1455,#1453,.T.);
#1457=ORIENTED_EDGE('',*,*,#1456,.T.);
#1458=CARTESIAN_POINT('',(-0.812800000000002,0.,0.));
#1459=DIRECTION('',(1.,0.,0.));
#1460=DIRECTION('',(0.,-0.587785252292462,-0.809016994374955));
#1461=AXIS2_PLACEMENT_3D('',#1458,#1459,#1460);
#1462=CIRCLE('',#1461,4.918964);
#1463=CARTESIAN_POINT('',(-0.812800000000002,4.1941062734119,-2.57015162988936));
#1464=VERTEX_POINT('',#1463);
#1465=EDGE_CURVE('E768',#1455,#1464,#1462,.T.);
#1466=ORIENTED_EDGE('',*,*,#1465,.T.);
#1467=DIRECTION('',(0.,-0.721252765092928,0.692671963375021));
#1468=VECTOR('',#1467,1.);
#1469=CARTESIAN_POINT('',(-0.812800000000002,4.1941062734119,-2.57015162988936));
#1470=LINE('',#1469,#1468);
#1471=EDGE_CURVE('E771',#1464,#226,#1470,.T.);
#1472=ORIENTED_EDGE('',*,*,#1471,.T.);
#1473=ORIENTED_EDGE('',*,*,#227,.F.);
#1474=DIRECTION('',(0.,0.990648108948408,0.136441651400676));
#1475=VECTOR('',#1474,1.);
#1476=CARTESIAN_POINT('',(-0.812800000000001,9.17954642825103,0.202959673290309));
#1477=LINE('',#1476,#1475);
#1478=CARTESIAN_POINT('',(-0.812800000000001,4.90380047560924,-0.385937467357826));
#1479=VERTEX_POINT('',#1478);
#1480=EDGE_CURVE('E1282',#224,#1479,#1477,.T.);
#1481=ORIENTED_EDGE('',*,*,#1480,.T.);
#1482=CARTESIAN_POINT('',(-0.812800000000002,0.,0.));
#1483=DIRECTION('',(1.,0.,0.));
#1484=DIRECTION('',(0.,0.,-1.));
#1485=AXIS2_PLACEMENT_3D('',#1482,#1483,#1484);
#1486=CIRCLE('',#1485,4.918964);
#1487=CARTESIAN_POINT('',(-0.812800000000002,4.90380047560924,0.385937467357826));
#1488=VERTEX_POINT('',#1487);
#1489=EDGE_CURVE('E856',#1479,#1488,#1486,.T.);
#1490=ORIENTED_EDGE('',*,*,#1489,.T.);
#1491=DIRECTION('',(0.,-0.990648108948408,0.136441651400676));
#1492=VECTOR('',#1491,1.);
#1493=CARTESIAN_POINT('',(-0.812800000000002,4.90380047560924,0.385937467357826));
#1494=LINE('',#1493,#1492);
#1495=EDGE_CURVE('E859',#1488,#658,#1494,.T.);
#1496=ORIENTED_EDGE('',*,*,#1495,.T.);
#1497=ORIENTED_EDGE('',*,*,#659,.F.);
#1498=DIRECTION('',(0.,0.721252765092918,0.692671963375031));
#1499=VECTOR('',#1498,1.);
#1500=CARTESIAN_POINT('',(-0.812800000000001,5.51807543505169,3.84165638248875));
#1501=LINE('',#1500,#1499);
#1502=CARTESIAN_POINT('',(-0.812800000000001,4.19410627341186,2.57015162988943));
#1503=VERTEX_POINT('',#1502);
#1504=EDGE_CURVE('E1285',#654,#1503,#1501,.T.);
#1505=ORIENTED_EDGE('',*,*,#1504,.T.);
#1506=CARTESIAN_POINT('',(-0.812800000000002,0.,0.));
#1507=DIRECTION('',(1.,0.,0.));
#1508=DIRECTION('',(0.,0.587785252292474,-0.809016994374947));
#1509=AXIS2_PLACEMENT_3D('',#1506,#1507,#1508);
#1510=CIRCLE('',#1509,4.918964);
#1511=CARTESIAN_POINT('',(-0.812800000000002,3.74040957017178,3.19461156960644));
#1512=VERTEX_POINT('',#1511);
#1513=EDGE_CURVE('E831',#1503,#1512,#1510,.T.);
#1514=ORIENTED_EDGE('',*,*,#1513,.T.);
#1515=DIRECTION('',(0.,-0.881649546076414,-0.471904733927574));
#1516=VECTOR('',#1515,1.);
#1517=CARTESIAN_POINT('',(-0.812800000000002,3.74040957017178,3.19461156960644));
#1518=LINE('',#1517,#1516);
#1519=EDGE_CURVE('E834',#1512,#265,#1518,.T.);
#1520=ORIENTED_EDGE('',*,*,#1519,.T.);
#1521=ORIENTED_EDGE('',*,*,#266,.F.);
#1522=DIRECTION('',(0.,0.176363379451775,0.984325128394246));
#1523=VECTOR('',#1522,1.);
#1524=CARTESIAN_POINT('',(-0.812800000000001,1.32132059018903,1.41298155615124));
#1525=LINE('',#1524,#1523);
#1526=EDGE_CURVE('E11',#261,#1294,#1525,.T.);
#1527=ORIENTED_EDGE('',*,*,#1526,.T.);
#1528=EDGE_LOOP('',(#1298,#1304,#1305,#1313,#1322,#1328,#1329,#1337,#1346,#1352,#1353,#1361,
#1370,#1376,#1377,#1385,#1394,#1400,#1401,#1409,#1418,#1424,#1425,#1433,#1442,#1448,#1449,#1457,
#1466,#1472,#1473,#1481,#1490,#1496,#1497,#1505,#1514,#1520,#1521,#1527));
#1529=FACE_BOUND('',#1528,.T.);
#1530=CARTESIAN_POINT('',(-0.812800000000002,0.,0.));
#1531=DIRECTION('',(-1.,0.,0.));
#1532=DIRECTION('',(0.,0.781831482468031,-0.623489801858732));
#1533=AXIS2_PLACEMENT_3D('',#1530,#1531,#1532);
#1534=CIRCLE('',#1533,6.82498);
#1535=CARTESIAN_POINT('',(-0.812800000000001,3.88672027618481,5.61014772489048));
#1536=VERTEX_POINT('',#1535);
#1537=CARTESIAN_POINT('',(-0.812800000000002,4.60461298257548,5.03764739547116));
#1538=VERTEX_POINT('',#1537);
#1539=EDGE_CURVE('E881',#1536,#1538,#1534,.T.);
#1540=ORIENTED_EDGE('',*,*,#1539,.T.);
#1541=DIRECTION('',(0.,0.880151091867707,0.474693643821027));
#1542=VECTOR('',#1541,1.);
#1543=CARTESIAN_POINT('',(-0.812800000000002,7.20877524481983,6.44215542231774));
#1544=LINE('',#1543,#1542);
#1545=EDGE_CURVE('E884',#1538,#288,#1544,.T.);
#1546=ORIENTED_EDGE('',*,*,#1545,.T.);
#1547=ORIENTED_EDGE('',*,*,#291,.T.);
#1548=DIRECTION('',(0.,-0.658644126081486,-0.752454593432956));
#1549=VECTOR('',#1548,1.);
#1550=CARTESIAN_POINT('',(-0.812800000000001,5.68592572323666,3.08253047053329));
#1551=LINE('',#1550,#1549);
#1552=CARTESIAN_POINT('',(-0.812800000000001,5.93596583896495,3.36818371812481));
#1553=VERTEX_POINT('',#1552);
#1554=EDGE_CURVE('E1243',#290,#1553,#1551,.T.);
#1555=ORIENTED_EDGE('',*,*,#1554,.T.);
#1556=CARTESIAN_POINT('',(-0.812800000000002,0.,0.));
#1557=DIRECTION('',(-1.,0.,0.));
#1558=DIRECTION('',(0.,0.433883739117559,-0.900968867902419));
#1559=AXIS2_PLACEMENT_3D('',#1556,#1557,#1558);
#1560=CIRCLE('',#1559,6.82498);
#1561=CARTESIAN_POINT('',(-0.812800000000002,6.33436623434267,2.54089677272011));
#1562=VERTEX_POINT('',#1561);
#1563=EDGE_CURVE('E1169',#1553,#1562,#1560,.T.);
#1564=ORIENTED_EDGE('',*,*,#1563,.T.);
#1565=DIRECTION('',(0.,0.998950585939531,0.0458009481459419));
#1566=VECTOR('',#1565,1.);
#1567=CARTESIAN_POINT('',(-0.812800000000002,9.29002855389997,2.67641112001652));
#1568=LINE('',#1567,#1566);
#1569=EDGE_CURVE('E1172',#1562,#617,#1568,.T.);
#1570=ORIENTED_EDGE('',*,*,#1569,.T.);
#1571=ORIENTED_EDGE('',*,*,#620,.T.);
#1572=DIRECTION('',(0.,-0.919895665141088,-0.392163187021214));
#1573=VECTOR('',#1572,1.);
#1574=CARTESIAN_POINT('',(-0.812800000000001,8.67308659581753,1.2535714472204));
#1575=LINE('',#1574,#1573);
#1576=CARTESIAN_POINT('',(-0.812800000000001,6.80952056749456,0.45910961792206));
#1577=VERTEX_POINT('',#1576);
#1578=EDGE_CURVE('E1238',#619,#1577,#1575,.T.);
#1579=ORIENTED_EDGE('',*,*,#1578,.T.);
#1580=CARTESIAN_POINT('',(-0.812800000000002,0.,0.));
#1581=DIRECTION('',(-1.,0.,0.));
#1582=DIRECTION('',(0.,0.,-1.));
#1583=AXIS2_PLACEMENT_3D('',#1580,#1581,#1582);
#1584=CIRCLE('',#1583,6.82498);
#1585=CARTESIAN_POINT('',(-0.812800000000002,6.80952056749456,-0.45910961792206));
#1586=VERTEX_POINT('',#1585);
#1587=EDGE_CURVE('E1193',#1577,#1586,#1584,.T.);
#1588=ORIENTED_EDGE('',*,*,#1587,.T.);
#1589=DIRECTION('',(0.,0.919895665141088,-0.392163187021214));
#1590=VECTOR('',#1589,1.);
#1591=CARTESIAN_POINT('',(-0.812800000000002,9.53127777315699,-1.61942922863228));
#1592=LINE('',#1591,#1590);
#1593=EDGE_CURVE('E1196',#1586,#1271,#1592,.T.);
#1594=ORIENTED_EDGE('',*,*,#1593,.T.);
#1595=ORIENTED_EDGE('',*,*,#1272,.T.);
#1596=DIRECTION('',(0.,-0.998950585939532,0.0458009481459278));
#1597=VECTOR('',#1596,1.);
#1598=CARTESIAN_POINT('',(-0.812800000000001,9.08521959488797,-2.66702082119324));
#1599=LINE('',#1598,#1597);
#1600=CARTESIAN_POINT('',(-0.812800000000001,6.3343662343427,-2.54089677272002));
#1601=VERTEX_POINT('',#1600);
#1602=EDGE_CURVE('E1249',#1267,#1601,#1599,.T.);
#1603=ORIENTED_EDGE('',*,*,#1602,.T.);
#1604=CARTESIAN_POINT('',(-0.812800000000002,0.,0.));
#1605=DIRECTION('',(-1.,0.,0.));
#1606=DIRECTION('',(0.,-0.433883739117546,-0.900968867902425));
#1607=AXIS2_PLACEMENT_3D('',#1604,#1605,#1606);
#1608=CIRCLE('',#1607,6.82498);
#1609=CARTESIAN_POINT('',(-0.812800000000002,5.935965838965,-3.36818371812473));
#1610=VERTEX_POINT('',#1609);
#1611=EDGE_CURVE('E1063',#1601,#1610,#1608,.T.);
#1612=ORIENTED_EDGE('',*,*,#1611,.T.);
#1613=DIRECTION('',(0.,0.658644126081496,-0.752454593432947));
#1614=VECTOR('',#1613,1.);
#1615=CARTESIAN_POINT('',(-0.812800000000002,7.88474053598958,-5.59452175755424));
#1616=LINE('',#1615,#1614);
#1617=EDGE_CURVE('E1066',#1610,#563,#1616,.T.);
#1618=ORIENTED_EDGE('',*,*,#1617,.T.);
#1619=ORIENTED_EDGE('',*,*,#566,.T.);
#1620=DIRECTION('',(0.,-0.880151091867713,0.474693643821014));
#1621=VECTOR('',#1620,1.);
#1622=CARTESIAN_POINT('',(-0.812800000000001,6.06557299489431,-5.82558987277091));
#1623=LINE('',#1622,#1621);
#1624=CARTESIAN_POINT('',(-0.812800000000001,4.60461298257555,-5.03764739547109));
#1625=VERTEX_POINT('',#1624);
#1626=EDGE_CURVE('E1246',#565,#1625,#1623,.T.);
#1627=ORIENTED_EDGE('',*,*,#1626,.T.);
#1628=CARTESIAN_POINT('',(-0.812800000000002,0.,0.));
#1629=DIRECTION('',(-1.,0.,0.));
#1630=DIRECTION('',(0.,-0.781831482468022,-0.623489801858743));
#1631=AXIS2_PLACEMENT_3D('',#1628,#1629,#1630);
#1632=CIRCLE('',#1631,6.82498);
#1633=CARTESIAN_POINT('',(-0.812800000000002,3.88672027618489,-5.61014772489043));
#1634=VERTEX_POINT('',#1633);
#1635=EDGE_CURVE('E1081',#1625,#1634,#1632,.T.);
#1636=ORIENTED_EDGE('',*,*,#1635,.T.);
#1637=DIRECTION('',(0.,0.266940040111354,-0.963713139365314));
#1638=VECTOR('',#1637,1.);
#1639=CARTESIAN_POINT('',(-0.812800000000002,4.67653373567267,-8.46155064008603));
#1640=LINE('',#1639,#1638);
#1641=EDGE_CURVE('E1084',#1634,#604,#1640,.T.);
#1642=ORIENTED_EDGE('',*,*,#1641,.T.);
#1643=ORIENTED_EDGE('',*,*,#605,.T.);
#1644=DIRECTION('',(0.,-0.58702687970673,0.80956744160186));
#1645=VECTOR('',#1644,1.);
#1646=CARTESIAN_POINT('',(-0.812800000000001,1.35291269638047,-5.69545369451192));
#1647=LINE('',#1646,#1645);
#1648=CARTESIAN_POINT('',(-0.812800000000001,1.96285965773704,-6.53663016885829));
#1649=VERTEX_POINT('',#1648);
#1650=EDGE_CURVE('E1252',#600,#1649,#1647,.T.);
#1651=ORIENTED_EDGE('',*,*,#1650,.T.);
#1652=CARTESIAN_POINT('',(-0.812800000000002,0.,0.));
#1653=DIRECTION('',(-1.,0.,0.));
#1654=DIRECTION('',(0.,-0.974927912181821,-0.222520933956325));
#1655=AXIS2_PLACEMENT_3D('',#1652,#1653,#1654);
#1656=CIRCLE('',#1655,6.82498);
#1657=CARTESIAN_POINT('',(-0.812800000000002,1.06766209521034,-6.74095317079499));
#1658=VERTEX_POINT('',#1657);
#1659=EDGE_CURVE('E1045',#1649,#1658,#1656,.T.);
#1660=ORIENTED_EDGE('',*,*,#1659,.T.);
#1661=DIRECTION('',(0.,-0.177634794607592,-0.984096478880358));
#1662=VECTOR('',#1661,1.);
#1663=CARTESIAN_POINT('',(-0.812800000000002,0.54208207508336,-9.65266564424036));
#1664=LINE('',#1663,#1662);
#1665=EDGE_CURVE('E1048',#1658,#550,#1664,.T.);
#1666=ORIENTED_EDGE('',*,*,#1665,.T.);
#1667=ORIENTED_EDGE('',*,*,#551,.T.);
#1668=DIRECTION('',(0.,-0.177634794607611,0.984096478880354));
#1669=VECTOR('',#1668,1.);
#1670=CARTESIAN_POINT('',(-0.812800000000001,-1.92182290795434,-2.00890363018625));
#1671=LINE('',#1670,#1669);
#1672=CARTESIAN_POINT('',(-0.812800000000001,-1.06766209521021,-6.74095317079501));
#1673=VERTEX_POINT('',#1672);
#1674=EDGE_CURVE('E1261',#546,#1673,#1671,.T.);
#1675=ORIENTED_EDGE('',*,*,#1674,.T.);
#1676=CARTESIAN_POINT('',(-0.812800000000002,0.,0.));
#1677=DIRECTION('',(-1.,0.,0.));
#1678=DIRECTION('',(0.,-0.974927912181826,0.222520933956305));
#1679=AXIS2_PLACEMENT_3D('',#1676,#1677,#1678);
#1680=CIRCLE('',#1679,6.82498);
#1681=CARTESIAN_POINT('',(-0.812800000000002,-1.96285965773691,-6.53663016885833));
#1682=VERTEX_POINT('',#1681);
#1683=EDGE_CURVE('E1011',#1673,#1682,#1680,.T.);
#1684=ORIENTED_EDGE('',*,*,#1683,.T.);
#1685=DIRECTION('',(0.,-0.587026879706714,-0.809567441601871));
#1686=VECTOR('',#1685,1.);
#1687=CARTESIAN_POINT('',(-0.812800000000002,-3.69973558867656,-8.93195183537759));
#1688=LINE('',#1687,#1686);
#1689=EDGE_CURVE('E1014',#1682,#455,#1688,.T.);
#1690=ORIENTED_EDGE('',*,*,#1689,.T.);
#1691=ORIENTED_EDGE('',*,*,#458,.T.);
#1692=DIRECTION('',(0.,0.266940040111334,0.963713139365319));
#1693=VECTOR('',#1692,1.);
#1694=CARTESIAN_POINT('',(-0.812800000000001,-1.51043478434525,2.96877340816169));
#1695=LINE('',#1694,#1693);
#1696=CARTESIAN_POINT('',(-0.812800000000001,-3.88672027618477,-5.61014772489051));
#1697=VERTEX_POINT('',#1696);
#1698=EDGE_CURVE('E1258',#457,#1697,#1695,.T.);
#1699=ORIENTED_EDGE('',*,*,#1698,.T.);
#1700=CARTESIAN_POINT('',(-0.812800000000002,0.,0.));
#1701=DIRECTION('',(-1.,0.,0.));
#1702=DIRECTION('',(0.,-0.781831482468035,0.623489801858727));
#1703=AXIS2_PLACEMENT_3D('',#1700,#1701,#1702);
#1704=CIRCLE('',#1703,6.82498);
#1705=CARTESIAN_POINT('',(-0.812800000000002,-4.60461298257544,-5.03764739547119));
#1706=VERTEX_POINT('',#1705);
#1707=EDGE_CURVE('E991',#1697,#1706,#1704,.T.);
#1708=ORIENTED_EDGE('',*,*,#1707,.T.);
#1709=DIRECTION('',(0.,-0.880151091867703,-0.474693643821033));
#1710=VECTOR('',#1709,1.);
#1711=CARTESIAN_POINT('',(-0.812800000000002,-7.20877524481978,-6.44215542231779));
#1712=LINE('',#1711,#1710);
#1713=EDGE_CURVE('E994',#1706,#482,#1712,.T.);
#1714=ORIENTED_EDGE('',*,*,#1713,.T.);
#1715=ORIENTED_EDGE('',*,*,#485,.T.);
#1716=DIRECTION('',(0.,0.658644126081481,0.752454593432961));
#1717=VECTOR('',#1716,1.);
#1718=CARTESIAN_POINT('',(-0.812800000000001,2.30272381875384,6.04393981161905));
#1719=LINE('',#1718,#1717);
#1720=CARTESIAN_POINT('',(-0.812800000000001,-5.93596583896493,-3.36818371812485));
#1721=VERTEX_POINT('',#1720);
#1722=EDGE_CURVE('E1255',#484,#1721,#1719,.T.);
#1723=ORIENTED_EDGE('',*,*,#1722,.T.);
#1724=CARTESIAN_POINT('',(-0.812800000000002,0.,0.));
#1725=DIRECTION('',(-1.,0.,0.));
#1726=DIRECTION('',(0.,-0.433883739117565,0.900968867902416));
#1727=AXIS2_PLACEMENT_3D('',#1724,#1725,#1726);
#1728=CIRCLE('',#1727,6.82498);
#1729=CARTESIAN_POINT('',(-0.812800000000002,-6.33436623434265,-2.54089677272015));
#1730=VERTEX_POINT('',#1729);
#1731=EDGE_CURVE('E1029',#1721,#1730,#1728,.T.);
#1732=ORIENTED_EDGE('',*,*,#1731,.T.);
#1733=DIRECTION('',(0.,-0.998950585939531,-0.0458009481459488));
#1734=VECTOR('',#1733,1.);
#1735=CARTESIAN_POINT('',(-0.812800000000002,-9.29002855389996,-2.67641112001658));
#1736=LINE('',#1735,#1734);
#1737=EDGE_CURVE('E1032',#1730,#523,#1736,.T.);
#1738=ORIENTED_EDGE('',*,*,#1737,.T.);
#1739=ORIENTED_EDGE('',*,*,#524,.T.);
#1740=DIRECTION('',(0.,0.919895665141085,0.39216318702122));
#1741=VECTOR('',#1740,1.);
#1742=CARTESIAN_POINT('',(-0.812800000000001,6.9098343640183,5.38962536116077));
#1743=LINE('',#1742,#1741);
#1744=CARTESIAN_POINT('',(-0.812800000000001,-6.80952056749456,-0.459109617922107));
#1745=VERTEX_POINT('',#1744);
#1746=EDGE_CURVE('E1270',#519,#1745,#1743,.T.);
#1747=ORIENTED_EDGE('',*,*,#1746,.T.);
#1748=CARTESIAN_POINT('',(-0.812800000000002,0.,0.));
#1749=DIRECTION('',(-1.,0.,0.));
#1750=DIRECTION('',(0.,0.,1.));
#1751=AXIS2_PLACEMENT_3D('',#1748,#1749,#1750);
#1752=CIRCLE('',#1751,6.82498);
#1753=CARTESIAN_POINT('',(-0.812800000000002,-6.80952056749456,0.459109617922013));
#1754=VERTEX_POINT('',#1753);
#1755=EDGE_CURVE('E957',#1745,#1754,#1752,.T.);
#1756=ORIENTED_EDGE('',*,*,#1755,.T.);
#1757=DIRECTION('',(0.,-0.919895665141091,0.392163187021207));
#1758=VECTOR('',#1757,1.);
#1759=CARTESIAN_POINT('',(-0.812800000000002,-9.531277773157,1.61942922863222));
#1760=LINE('',#1759,#1758);
#1761=EDGE_CURVE('E960',#1754,#374,#1760,.T.);
#1762=ORIENTED_EDGE('',*,*,#1761,.T.);
#1763=ORIENTED_EDGE('',*,*,#377,.T.);
#1764=DIRECTION('',(0.,0.998950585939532,-0.0458009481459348));
#1765=VECTOR('',#1764,1.);
#1766=CARTESIAN_POINT('',(-0.812800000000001,9.29115076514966,1.82448146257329));
#1767=LINE('',#1766,#1765);
#1768=CARTESIAN_POINT('',(-0.812800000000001,-6.33436623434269,2.54089677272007));
#1769=VERTEX_POINT('',#1768);
#1770=EDGE_CURVE('E1267',#376,#1769,#1767,.T.);
#1771=ORIENTED_EDGE('',*,*,#1770,.T.);
#1772=CARTESIAN_POINT('',(-0.812800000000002,0.,0.));
#1773=DIRECTION('',(-1.,0.,0.));
#1774=DIRECTION('',(0.,0.433883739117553,0.900968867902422));
#1775=AXIS2_PLACEMENT_3D('',#1772,#1773,#1774);
#1776=CIRCLE('',#1775,6.82498);
#1777=CARTESIAN_POINT('',(-0.812800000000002,-5.93596583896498,3.36818371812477));
#1778=VERTEX_POINT('',#1777);
#1779=EDGE_CURVE('E937',#1769,#1778,#1776,.T.);
#1780=ORIENTED_EDGE('',*,*,#1779,.T.);
#1781=DIRECTION('',(0.,-0.658644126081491,0.752454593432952));
#1782=VECTOR('',#1781,1.);
#1783=CARTESIAN_POINT('',(-0.812800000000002,-7.88474053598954,5.59452175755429));
#1784=LINE('',#1783,#1782);
#1785=EDGE_CURVE('E940',#1778,#401,#1784,.T.);
#1786=ORIENTED_EDGE('',*,*,#1785,.T.);
#1787=ORIENTED_EDGE('',*,*,#404,.T.);
#1788=DIRECTION('',(0.,0.88015109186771,-0.474693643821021));
#1789=VECTOR('',#1788,1.);
#1790=CARTESIAN_POINT('',(-0.812800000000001,8.19990037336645,-1.86823633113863));
#1791=LINE('',#1790,#1789);
#1792=CARTESIAN_POINT('',(-0.812800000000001,-4.60461298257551,5.03764739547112));
#1793=VERTEX_POINT('',#1792);
#1794=EDGE_CURVE('E1264',#403,#1793,#1791,.T.);
#1795=ORIENTED_EDGE('',*,*,#1794,.T.);
#1796=CARTESIAN_POINT('',(-0.812800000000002,0.,0.));
#1797=DIRECTION('',(-1.,0.,0.));
#1798=DIRECTION('',(0.,0.781831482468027,0.623489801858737));
#1799=AXIS2_PLACEMENT_3D('',#1796,#1797,#1798);
#1800=CIRCLE('',#1799,6.82498);
#1801=CARTESIAN_POINT('',(-0.812800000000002,-3.88672027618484,5.61014772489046));
#1802=VERTEX_POINT('',#1801);
#1803=EDGE_CURVE('E975',#1793,#1802,#1800,.T.);
#1804=ORIENTED_EDGE('',*,*,#1803,.T.);
#1805=DIRECTION('',(0.,-0.266940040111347,0.963713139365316));
#1806=VECTOR('',#1805,1.);
#1807=CARTESIAN_POINT('',(-0.812800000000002,-4.6765337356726,8.46155064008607));
#1808=LINE('',#1807,#1806);
#1809=EDGE_CURVE('E978',#1802,#442,#1808,.T.);
#1810=ORIENTED_EDGE('',*,*,#1809,.T.);
#1811=ORIENTED_EDGE('',*,*,#443,.T.);
#1812=DIRECTION('',(0.,0.587026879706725,-0.809567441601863));
#1813=VECTOR('',#1812,1.);
#1814=CARTESIAN_POINT('',(-0.812800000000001,4.9929065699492,-3.05605129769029));
#1815=LINE('',#1814,#1813);
#1816=CARTESIAN_POINT('',(-0.812800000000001,-1.962859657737,6.53663016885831));
#1817=VERTEX_POINT('',#1816);
#1818=EDGE_CURVE('E1273',#438,#1817,#1815,.T.);
#1819=ORIENTED_EDGE('',*,*,#1818,.T.);
#1820=CARTESIAN_POINT('',(-0.812800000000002,0.,0.));
#1821=DIRECTION('',(-1.,0.,0.));
#1822=DIRECTION('',(0.,0.974927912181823,0.222520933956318));
#1823=AXIS2_PLACEMENT_3D('',#1820,#1821,#1822);
#1824=CIRCLE('',#1823,6.82498);
#1825=CARTESIAN_POINT('',(-0.812800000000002,-1.0676620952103,6.740953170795));
#1826=VERTEX_POINT('',#1825);
#1827=EDGE_CURVE('E919',#1817,#1826,#1824,.T.);
#1828=ORIENTED_EDGE('',*,*,#1827,.T.);
#1829=DIRECTION('',(0.,0.177634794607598,0.984096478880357));
#1830=VECTOR('',#1829,1.);
#1831=CARTESIAN_POINT('',(-0.812800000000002,-0.542082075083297,9.65266564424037));
#1832=LINE('',#1831,#1830);
#1833=EDGE_CURVE('E922',#1826,#361,#1832,.T.);
#1834=ORIENTED_EDGE('',*,*,#1833,.T.);
#1835=ORIENTED_EDGE('',*,*,#362,.T.);
#1836=DIRECTION('',(0.,0.177634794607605,-0.984096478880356));
#1837=VECTOR('',#1836,1.);
#1838=CARTESIAN_POINT('',(-0.812800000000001,2.50289203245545,-1.21021839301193));
#1839=LINE('',#1838,#1837);
#1840=CARTESIAN_POINT('',(-0.812800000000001,1.06766209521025,6.740953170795));
#1841=VERTEX_POINT('',#1840);
#1842=EDGE_CURVE('E1276',#357,#1841,#1839,.T.);
#1843=ORIENTED_EDGE('',*,*,#1842,.T.);
#1844=CARTESIAN_POINT('',(-0.812800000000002,0.,0.));
#1845=DIRECTION('',(-1.,0.,0.));
#1846=DIRECTION('',(0.,0.974927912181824,-0.222520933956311));
#1847=AXIS2_PLACEMENT_3D('',#1844,#1845,#1846);
#1848=CIRCLE('',#1847,6.82498);
#1849=CARTESIAN_POINT('',(-0.812800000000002,1.96285965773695,6.53663016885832));
#1850=VERTEX_POINT('',#1849);
#1851=EDGE_CURVE('E901',#1841,#1850,#1848,.T.);
#1852=ORIENTED_EDGE('',*,*,#1851,.T.);
#1853=DIRECTION('',(0.,0.587026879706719,0.809567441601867));
#1854=VECTOR('',#1853,1.);
#1855=CARTESIAN_POINT('',(-0.812800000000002,3.69973558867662,8.93195183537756));
#1856=LINE('',#1855,#1854);
#1857=EDGE_CURVE('E904',#1850,#334,#1856,.T.);
#1858=ORIENTED_EDGE('',*,*,#1857,.T.);
#1859=ORIENTED_EDGE('',*,*,#335,.T.);
#1860=DIRECTION('',(0.,-0.26694004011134,-0.963713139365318));
#1861=VECTOR('',#1860,1.);
#1862=CARTESIAN_POINT('',(-0.812800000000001,2.82263216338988,1.76855207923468));
#1863=LINE('',#1862,#1861);
#1864=EDGE_CURVE('E1279',#330,#1536,#1863,.T.);
#1865=ORIENTED_EDGE('',*,*,#1864,.T.);
#1866=EDGE_LOOP('',(#1540,#1546,#1547,#1555,#1564,#1570,#1571,#1579,#1588,#1594,#1595,#1603,
#1612,#1618,#1619,#1627,#1636,#1642,#1643,#1651,#1660,#1666,#1667,#1675,#1684,#1690,#1691,#1699,
#1708,#1714,#1715,#1723,#1732,#1738,#1739,#1747,#1756,#1762,#1763,#1771,#1780,#1786,#1787,#1795,
#1804,#1810,#1811,#1819,#1828,#1834,#1835,#1843,#1852,#1858,#1859,#1865));
#1867=FACE_BOUND('',#1866,.T.);
#1868=ADVANCED_FACE('F651',(#1529,#1867),#1287,.F.);
#1869=CARTESIAN_POINT('',(-0.812800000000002,9.53127777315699,-1.61942922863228));
#1870=DIRECTION('',(0.,-0.392163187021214,-0.919895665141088));
#1871=DIRECTION('',(0.,0.919895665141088,-0.392163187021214));
#1872=AXIS2_PLACEMENT_3D('',#1869,#1870,#1871);
#1873=PLANE('',#1872);
#1874=ORIENTED_EDGE('',*,*,#1593,.F.);
#1875=DIRECTION('',(1.,0.,0.));
#1876=VECTOR('',#1875,1.);
#1877=CARTESIAN_POINT('',(-0.812800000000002,6.80952056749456,-0.45910961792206));
#1878=LINE('',#1877,#1876);
#1879=EDGE_CURVE('E1206',#1586,#974,#1878,.T.);
#1880=ORIENTED_EDGE('',*,*,#1879,.T.);
#1881=ORIENTED_EDGE('',*,*,#975,.T.);
#1882=ORIENTED_EDGE('',*,*,#1278,.F.);
#1883=EDGE_LOOP('',(#1874,#1880,#1881,#1882));
#1884=FACE_BOUND('',#1883,.T.);
#1885=ADVANCED_FACE('F1694',(#1884),#1873,.F.);
#1886=CARTESIAN_POINT('',(-0.812800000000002,9.53127777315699,1.61942922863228));
#1887=DIRECTION('',(0.,-0.392163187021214,0.919895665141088));
#1888=DIRECTION('',(0.,-0.919895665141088,-0.392163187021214));
#1889=AXIS2_PLACEMENT_3D('',#1886,#1887,#1888);
#1890=PLANE('',#1889);
#1891=ORIENTED_EDGE('',*,*,#990,.T.);
#1892=DIRECTION('',(1.,0.,0.));
#1893=VECTOR('',#1892,1.);
#1894=CARTESIAN_POINT('',(-0.812800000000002,6.80952056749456,0.45910961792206));
#1895=LINE('',#1894,#1893);
#1896=EDGE_CURVE('E1200',#1577,#983,#1895,.T.);
#1897=ORIENTED_EDGE('',*,*,#1896,.F.);
#1898=ORIENTED_EDGE('',*,*,#1578,.F.);
#1899=ORIENTED_EDGE('',*,*,#638,.F.);
#1900=EDGE_LOOP('',(#1891,#1897,#1898,#1899));
#1901=FACE_BOUND('',#1900,.T.);
#1902=ADVANCED_FACE('F1697',(#1901),#1890,.F.);
#1903=CARTESIAN_POINT('',(-0.812800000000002,0.,0.));
#1904=DIRECTION('',(1.,0.,0.));
#1905=DIRECTION('',(0.,0.,-1.));
#1906=AXIS2_PLACEMENT_3D('',#1903,#1904,#1905);
#1907=CYLINDRICAL_SURFACE('',#1906,6.82498);
#1908=ORIENTED_EDGE('',*,*,#984,.T.);
#1909=ORIENTED_EDGE('',*,*,#1879,.F.);
#1910=ORIENTED_EDGE('',*,*,#1587,.F.);
#1911=ORIENTED_EDGE('',*,*,#1896,.T.);
#1912=EDGE_LOOP('',(#1908,#1909,#1910,#1911));
#1913=FACE_BOUND('',#1912,.T.);
#1914=ADVANCED_FACE('F1686',(#1913),#1907,.T.);
#1915=CARTESIAN_POINT('',(-0.812800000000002,9.29002855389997,2.67641112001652));
#1916=DIRECTION('',(0.,0.0458009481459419,-0.998950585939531));
#1917=DIRECTION('',(0.,0.998950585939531,0.0458009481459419));
#1918=AXIS2_PLACEMENT_3D('',#1915,#1916,#1917);
#1919=PLANE('',#1918);
#1920=ORIENTED_EDGE('',*,*,#1569,.F.);
#1921=DIRECTION('',(1.,0.,0.));
#1922=VECTOR('',#1921,1.);
#1923=CARTESIAN_POINT('',(-0.812800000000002,6.33436623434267,2.54089677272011));
#1924=LINE('',#1923,#1922);
#1925=EDGE_CURVE('E1182',#1562,#998,#1924,.T.);
#1926=ORIENTED_EDGE('',*,*,#1925,.T.);
#1927=ORIENTED_EDGE('',*,*,#999,.T.);
#1928=ORIENTED_EDGE('',*,*,#628,.F.);
#1929=EDGE_LOOP('',(#1920,#1926,#1927,#1928));
#1930=FACE_BOUND('',#1929,.T.);
#1931=ADVANCED_FACE('F1682',(#1930),#1919,.F.);
#1932=CARTESIAN_POINT('',(-0.812800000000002,7.8847405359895,5.59452175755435));
#1933=DIRECTION('',(0.,-0.752454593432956,0.658644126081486));
#1934=DIRECTION('',(0.,-0.658644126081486,-0.752454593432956));
#1935=AXIS2_PLACEMENT_3D('',#1932,#1933,#1934);
#1936=PLANE('',#1935);
#1937=ORIENTED_EDGE('',*,*,#1014,.T.);
#1938=DIRECTION('',(1.,0.,0.));
#1939=VECTOR('',#1938,1.);
#1940=CARTESIAN_POINT('',(-0.812800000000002,5.93596583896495,3.36818371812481));
#1941=LINE('',#1940,#1939);
#1942=EDGE_CURVE('E1176',#1553,#1007,#1941,.T.);
#1943=ORIENTED_EDGE('',*,*,#1942,.F.);
#1944=ORIENTED_EDGE('',*,*,#1554,.F.);
#1945=ORIENTED_EDGE('',*,*,#314,.F.);
#1946=EDGE_LOOP('',(#1937,#1943,#1944,#1945));
#1947=FACE_BOUND('',#1946,.T.);
#1948=ADVANCED_FACE('F1685',(#1947),#1936,.F.);
#1949=CARTESIAN_POINT('',(-0.812800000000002,0.,0.));
#1950=DIRECTION('',(1.,0.,0.));
#1951=DIRECTION('',(0.,0.,-1.));
#1952=AXIS2_PLACEMENT_3D('',#1949,#1950,#1951);
#1953=CYLINDRICAL_SURFACE('',#1952,6.82498);
#1954=ORIENTED_EDGE('',*,*,#1008,.T.);
#1955=ORIENTED_EDGE('',*,*,#1925,.F.);
#1956=ORIENTED_EDGE('',*,*,#1563,.F.);
#1957=ORIENTED_EDGE('',*,*,#1942,.T.);
#1958=EDGE_LOOP('',(#1954,#1955,#1956,#1957));
#1959=FACE_BOUND('',#1958,.T.);
#1960=ADVANCED_FACE('F1674',(#1959),#1953,.T.);
#1961=CARTESIAN_POINT('',(-0.812800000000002,4.67653373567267,-8.46155064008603));
#1962=DIRECTION('',(0.,-0.963713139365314,-0.266940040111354));
#1963=DIRECTION('',(0.,0.266940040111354,-0.963713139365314));
#1964=AXIS2_PLACEMENT_3D('',#1961,#1962,#1963);
#1965=PLANE('',#1964);
#1966=ORIENTED_EDGE('',*,*,#1641,.F.);
#1967=DIRECTION('',(1.,0.,0.));
#1968=VECTOR('',#1967,1.);
#1969=CARTESIAN_POINT('',(-0.812800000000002,3.88672027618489,-5.61014772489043));
#1970=LINE('',#1969,#1968);
#1971=EDGE_CURVE('E1056',#1634,#921,#1970,.T.);
#1972=ORIENTED_EDGE('',*,*,#1971,.T.);
#1973=ORIENTED_EDGE('',*,*,#922,.T.);
#1974=ORIENTED_EDGE('',*,*,#611,.F.);
#1975=EDGE_LOOP('',(#1966,#1972,#1973,#1974));
#1976=FACE_BOUND('',#1975,.T.);
#1977=ADVANCED_FACE('F1670',(#1976),#1965,.F.);
#1978=CARTESIAN_POINT('',(-0.812800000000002,7.20877524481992,-6.44215542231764));
#1979=DIRECTION('',(0.,0.474693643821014,0.880151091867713));
#1980=DIRECTION('',(0.,-0.880151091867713,0.474693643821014));
#1981=AXIS2_PLACEMENT_3D('',#1978,#1979,#1980);
#1982=PLANE('',#1981);
#1983=ORIENTED_EDGE('',*,*,#937,.T.);
#1984=DIRECTION('',(1.,0.,0.));
#1985=VECTOR('',#1984,1.);
#1986=CARTESIAN_POINT('',(-0.812800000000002,4.60461298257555,-5.03764739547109));
#1987=LINE('',#1986,#1985);
#1988=EDGE_CURVE('E1088',#1625,#930,#1987,.T.);
#1989=ORIENTED_EDGE('',*,*,#1988,.F.);
#1990=ORIENTED_EDGE('',*,*,#1626,.F.);
#1991=ORIENTED_EDGE('',*,*,#584,.F.);
#1992=EDGE_LOOP('',(#1983,#1989,#1990,#1991));
#1993=FACE_BOUND('',#1992,.T.);
#1994=ADVANCED_FACE('F1673',(#1993),#1982,.F.);
#1995=CARTESIAN_POINT('',(-0.812800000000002,0.,0.));
#1996=DIRECTION('',(1.,0.,0.));
#1997=DIRECTION('',(0.,0.,-1.));
#1998=AXIS2_PLACEMENT_3D('',#1995,#1996,#1997);
#1999=CYLINDRICAL_SURFACE('',#1998,6.82498);
#2000=ORIENTED_EDGE('',*,*,#931,.T.);
#2001=ORIENTED_EDGE('',*,*,#1971,.F.);
#2002=ORIENTED_EDGE('',*,*,#1635,.F.);
#2003=ORIENTED_EDGE('',*,*,#1988,.T.);
#2004=EDGE_LOOP('',(#2000,#2001,#2002,#2003));
#2005=FACE_BOUND('',#2004,.T.);
#2006=ADVANCED_FACE('F1662',(#2005),#1999,.T.);
#2007=CARTESIAN_POINT('',(-0.812800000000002,7.88474053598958,-5.59452175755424));
#2008=DIRECTION('',(0.,-0.752454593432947,-0.658644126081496));
#2009=DIRECTION('',(0.,0.658644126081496,-0.752454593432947));
#2010=AXIS2_PLACEMENT_3D('',#2007,#2008,#2009);
#2011=PLANE('',#2010);
#2012=ORIENTED_EDGE('',*,*,#1617,.F.);
#2013=DIRECTION('',(1.,0.,0.));
#2014=VECTOR('',#2013,1.);
#2015=CARTESIAN_POINT('',(-0.812800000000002,5.935965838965,-3.36818371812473));
#2016=LINE('',#2015,#2014);
#2017=EDGE_CURVE('E1076',#1610,#945,#2016,.T.);
#2018=ORIENTED_EDGE('',*,*,#2017,.T.);
#2019=ORIENTED_EDGE('',*,*,#946,.T.);
#2020=ORIENTED_EDGE('',*,*,#574,.F.);
#2021=EDGE_LOOP('',(#2012,#2018,#2019,#2020));
#2022=FACE_BOUND('',#2021,.T.);
#2023=ADVANCED_FACE('F1658',(#2022),#2011,.F.);
#2024=CARTESIAN_POINT('',(-0.812800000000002,9.29002855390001,-2.67641112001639));
#2025=DIRECTION('',(0.,0.0458009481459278,0.998950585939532));
#2026=DIRECTION('',(0.,-0.998950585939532,0.0458009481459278));
#2027=AXIS2_PLACEMENT_3D('',#2024,#2025,#2026);
#2028=PLANE('',#2027);
#2029=ORIENTED_EDGE('',*,*,#963,.T.);
#2030=DIRECTION('',(1.,0.,0.));
#2031=VECTOR('',#2030,1.);
#2032=CARTESIAN_POINT('',(-0.812800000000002,6.3343662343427,-2.54089677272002));
#2033=LINE('',#2032,#2031);
#2034=EDGE_CURVE('E1070',#1601,#954,#2033,.T.);
#2035=ORIENTED_EDGE('',*,*,#2034,.F.);
#2036=ORIENTED_EDGE('',*,*,#1602,.F.);
#2037=ORIENTED_EDGE('',*,*,#1268,.F.);
#2038=EDGE_LOOP('',(#2029,#2035,#2036,#2037));
#2039=FACE_BOUND('',#2038,.T.);
#2040=ADVANCED_FACE('F1661',(#2039),#2028,.F.);
#2041=CARTESIAN_POINT('',(-0.812800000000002,0.,0.));
#2042=DIRECTION('',(1.,0.,0.));
#2043=DIRECTION('',(0.,0.,-1.));
#2044=AXIS2_PLACEMENT_3D('',#2041,#2042,#2043);
#2045=CYLINDRICAL_SURFACE('',#2044,6.82498);
#2046=ORIENTED_EDGE('',*,*,#955,.T.);
#2047=ORIENTED_EDGE('',*,*,#2017,.F.);
#2048=ORIENTED_EDGE('',*,*,#1611,.F.);
#2049=ORIENTED_EDGE('',*,*,#2034,.T.);
#2050=EDGE_LOOP('',(#2046,#2047,#2048,#2049));
#2051=FACE_BOUND('',#2050,.T.);
#2052=ADVANCED_FACE('F1650',(#2051),#2045,.T.);
#2053=CARTESIAN_POINT('',(-0.812800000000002,0.54208207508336,-9.65266564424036));
#2054=DIRECTION('',(0.,-0.984096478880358,0.177634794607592));
#2055=DIRECTION('',(0.,-0.177634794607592,-0.984096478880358));
#2056=AXIS2_PLACEMENT_3D('',#2053,#2054,#2055);
#2057=PLANE('',#2056);
#2058=ORIENTED_EDGE('',*,*,#1665,.F.);
#2059=DIRECTION('',(1.,0.,0.));
#2060=VECTOR('',#2059,1.);
#2061=CARTESIAN_POINT('',(-0.812800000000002,1.06766209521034,-6.74095317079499));
#2062=LINE('',#2061,#2060);
#2063=EDGE_CURVE('E1022',#1658,#897,#2062,.T.);
#2064=ORIENTED_EDGE('',*,*,#2063,.T.);
#2065=ORIENTED_EDGE('',*,*,#898,.T.);
#2066=ORIENTED_EDGE('',*,*,#557,.F.);
#2067=EDGE_LOOP('',(#2058,#2064,#2065,#2066));
#2068=FACE_BOUND('',#2067,.T.);
#2069=ADVANCED_FACE('F1646',(#2068),#2057,.F.);
#2070=CARTESIAN_POINT('',(-0.812800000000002,3.69973558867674,-8.93195183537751));
#2071=DIRECTION('',(0.,0.809567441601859,0.58702687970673));
#2072=DIRECTION('',(0.,-0.58702687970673,0.80956744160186));
#2073=AXIS2_PLACEMENT_3D('',#2070,#2071,#2072);
#2074=PLANE('',#2073);
#2075=ORIENTED_EDGE('',*,*,#913,.T.);
#2076=DIRECTION('',(1.,0.,0.));
#2077=VECTOR('',#2076,1.);
#2078=CARTESIAN_POINT('',(-0.812800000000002,1.96285965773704,-6.53663016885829));
#2079=LINE('',#2078,#2077);
#2080=EDGE_CURVE('E1052',#1649,#906,#2079,.T.);
#2081=ORIENTED_EDGE('',*,*,#2080,.F.);
#2082=ORIENTED_EDGE('',*,*,#1650,.F.);
#2083=ORIENTED_EDGE('',*,*,#601,.F.);
#2084=EDGE_LOOP('',(#2075,#2081,#2082,#2083));
#2085=FACE_BOUND('',#2084,.T.);
#2086=ADVANCED_FACE('F1649',(#2085),#2074,.F.);
#2087=CARTESIAN_POINT('',(-0.812800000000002,0.,0.));
#2088=DIRECTION('',(1.,0.,0.));
#2089=DIRECTION('',(0.,0.,-1.));
#2090=AXIS2_PLACEMENT_3D('',#2087,#2088,#2089);
#2091=CYLINDRICAL_SURFACE('',#2090,6.82498);
#2092=ORIENTED_EDGE('',*,*,#907,.T.);
#2093=ORIENTED_EDGE('',*,*,#2063,.F.);
#2094=ORIENTED_EDGE('',*,*,#1659,.F.);
#2095=ORIENTED_EDGE('',*,*,#2080,.T.);
#2096=EDGE_LOOP('',(#2092,#2093,#2094,#2095));
#2097=FACE_BOUND('',#2096,.T.);
#2098=ADVANCED_FACE('F1638',(#2097),#2091,.T.);
#2099=CARTESIAN_POINT('',(-0.812800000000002,-9.29002855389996,-2.67641112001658));
#2100=DIRECTION('',(0.,-0.0458009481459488,0.998950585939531));
#2101=DIRECTION('',(0.,-0.998950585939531,-0.0458009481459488));
#2102=AXIS2_PLACEMENT_3D('',#2099,#2100,#2101);
#2103=PLANE('',#2102);
#2104=ORIENTED_EDGE('',*,*,#1737,.F.);
#2105=DIRECTION('',(1.,0.,0.));
#2106=VECTOR('',#2105,1.);
#2107=CARTESIAN_POINT('',(-0.812800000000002,-6.33436623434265,-2.54089677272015));
#2108=LINE('',#2107,#2106);
#2109=EDGE_CURVE('E968',#1730,#825,#2108,.T.);
#2110=ORIENTED_EDGE('',*,*,#2109,.T.);
#2111=ORIENTED_EDGE('',*,*,#826,.T.);
#2112=ORIENTED_EDGE('',*,*,#530,.F.);
#2113=EDGE_LOOP('',(#2104,#2110,#2111,#2112));
#2114=FACE_BOUND('',#2113,.T.);
#2115=ADVANCED_FACE('F1634',(#2114),#2103,.F.);
#2116=CARTESIAN_POINT('',(-0.812800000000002,-7.88474053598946,-5.5945217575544));
#2117=DIRECTION('',(0.,0.752454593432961,-0.658644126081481));
#2118=DIRECTION('',(0.,0.658644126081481,0.752454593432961));
#2119=AXIS2_PLACEMENT_3D('',#2116,#2117,#2118);
#2120=PLANE('',#2119);
#2121=ORIENTED_EDGE('',*,*,#841,.T.);
#2122=DIRECTION('',(1.,0.,0.));
#2123=VECTOR('',#2122,1.);
#2124=CARTESIAN_POINT('',(-0.812800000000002,-5.93596583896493,-3.36818371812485));
#2125=LINE('',#2124,#2123);
#2126=EDGE_CURVE('E1036',#1721,#834,#2125,.T.);
#2127=ORIENTED_EDGE('',*,*,#2126,.F.);
#2128=ORIENTED_EDGE('',*,*,#1722,.F.);
#2129=ORIENTED_EDGE('',*,*,#503,.F.);
#2130=EDGE_LOOP('',(#2121,#2127,#2128,#2129));
#2131=FACE_BOUND('',#2130,.T.);
#2132=ADVANCED_FACE('F1637',(#2131),#2120,.F.);
#2133=CARTESIAN_POINT('',(-0.812800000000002,0.,0.));
#2134=DIRECTION('',(1.,0.,0.));
#2135=DIRECTION('',(0.,0.,-1.));
#2136=AXIS2_PLACEMENT_3D('',#2133,#2134,#2135);
#2137=CYLINDRICAL_SURFACE('',#2136,6.82498);
#2138=ORIENTED_EDGE('',*,*,#835,.T.);
#2139=ORIENTED_EDGE('',*,*,#2109,.F.);
#2140=ORIENTED_EDGE('',*,*,#1731,.F.);
#2141=ORIENTED_EDGE('',*,*,#2126,.T.);
#2142=EDGE_LOOP('',(#2138,#2139,#2140,#2141));
#2143=FACE_BOUND('',#2142,.T.);
#2144=ADVANCED_FACE('F1614',(#2143),#2137,.T.);
#2145=CARTESIAN_POINT('',(-0.812800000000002,-7.20877524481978,-6.44215542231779));
#2146=DIRECTION('',(0.,-0.474693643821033,0.880151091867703));
#2147=DIRECTION('',(0.,-0.880151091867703,-0.474693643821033));
#2148=AXIS2_PLACEMENT_3D('',#2145,#2146,#2147);
#2149=PLANE('',#2148);
#2150=ORIENTED_EDGE('',*,*,#1713,.F.);
#2151=DIRECTION('',(1.,0.,0.));
#2152=VECTOR('',#2151,1.);
#2153=CARTESIAN_POINT('',(-0.812800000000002,-4.60461298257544,-5.03764739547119));
#2154=LINE('',#2153,#2152);
#2155=EDGE_CURVE('E1006',#1706,#849,#2154,.T.);
#2156=ORIENTED_EDGE('',*,*,#2155,.T.);
#2157=ORIENTED_EDGE('',*,*,#850,.T.);
#2158=ORIENTED_EDGE('',*,*,#493,.F.);
#2159=EDGE_LOOP('',(#2150,#2156,#2157,#2158));
#2160=FACE_BOUND('',#2159,.T.);
#2161=ADVANCED_FACE('F1610',(#2160),#2149,.F.);
#2162=CARTESIAN_POINT('',(-0.812800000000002,-4.67653373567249,-8.46155064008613));
#2163=DIRECTION('',(0.,0.963713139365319,-0.266940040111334));
#2164=DIRECTION('',(0.,0.266940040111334,0.963713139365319));
#2165=AXIS2_PLACEMENT_3D('',#2162,#2163,#2164);
#2166=PLANE('',#2165);
#2167=ORIENTED_EDGE('',*,*,#865,.T.);
#2168=DIRECTION('',(1.,0.,0.));
#2169=VECTOR('',#2168,1.);
#2170=CARTESIAN_POINT('',(-0.812800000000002,-3.88672027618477,-5.61014772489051));
#2171=LINE('',#2170,#2169);
#2172=EDGE_CURVE('E998',#1697,#858,#2171,.T.);
#2173=ORIENTED_EDGE('',*,*,#2172,.F.);
#2174=ORIENTED_EDGE('',*,*,#1698,.F.);
#2175=ORIENTED_EDGE('',*,*,#476,.F.);
#2176=EDGE_LOOP('',(#2167,#2173,#2174,#2175));
#2177=FACE_BOUND('',#2176,.T.);
#2178=ADVANCED_FACE('F1613',(#2177),#2166,.F.);
#2179=CARTESIAN_POINT('',(-0.812800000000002,0.,0.));
#2180=DIRECTION('',(1.,0.,0.));
#2181=DIRECTION('',(0.,0.,-1.));
#2182=AXIS2_PLACEMENT_3D('',#2179,#2180,#2181);
#2183=CYLINDRICAL_SURFACE('',#2182,6.82498);
#2184=ORIENTED_EDGE('',*,*,#859,.T.);
#2185=ORIENTED_EDGE('',*,*,#2155,.F.);
#2186=ORIENTED_EDGE('',*,*,#1707,.F.);
#2187=ORIENTED_EDGE('',*,*,#2172,.T.);
#2188=EDGE_LOOP('',(#2184,#2185,#2186,#2187));
#2189=FACE_BOUND('',#2188,.T.);
#2190=ADVANCED_FACE('F1616',(#2189),#2183,.T.);
#2191=CARTESIAN_POINT('',(-0.812800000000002,-3.69973558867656,-8.93195183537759));
#2192=DIRECTION('',(0.,-0.809567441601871,0.587026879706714));
#2193=DIRECTION('',(0.,-0.587026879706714,-0.809567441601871));
#2194=AXIS2_PLACEMENT_3D('',#2191,#2192,#2193);
#2195=PLANE('',#2194);
#2196=ORIENTED_EDGE('',*,*,#1689,.F.);
#2197=DIRECTION('',(1.,0.,0.));
#2198=VECTOR('',#2197,1.);
#2199=CARTESIAN_POINT('',(-0.812800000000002,-1.96285965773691,-6.53663016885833));
#2200=LINE('',#2199,#2198);
#2201=EDGE_CURVE('E1002',#1682,#873,#2200,.T.);
#2202=ORIENTED_EDGE('',*,*,#2201,.T.);
#2203=ORIENTED_EDGE('',*,*,#874,.T.);
#2204=ORIENTED_EDGE('',*,*,#466,.F.);
#2205=EDGE_LOOP('',(#2196,#2202,#2203,#2204));
#2206=FACE_BOUND('',#2205,.T.);
#2207=ADVANCED_FACE('F1619',(#2206),#2195,.F.);
#2208=CARTESIAN_POINT('',(-0.812800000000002,-0.542082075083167,-9.65266564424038));
#2209=DIRECTION('',(0.,0.984096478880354,0.177634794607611));
#2210=DIRECTION('',(0.,-0.177634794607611,0.984096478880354));
#2211=AXIS2_PLACEMENT_3D('',#2208,#2209,#2210);
#2212=PLANE('',#2211);
#2213=ORIENTED_EDGE('',*,*,#889,.T.);
#2214=DIRECTION('',(1.,0.,0.));
#2215=VECTOR('',#2214,1.);
#2216=CARTESIAN_POINT('',(-0.812800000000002,-1.06766209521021,-6.74095317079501));
#2217=LINE('',#2216,#2215);
#2218=EDGE_CURVE('E1018',#1673,#882,#2217,.T.);
#2219=ORIENTED_EDGE('',*,*,#2218,.F.);
#2220=ORIENTED_EDGE('',*,*,#1674,.F.);
#2221=ORIENTED_EDGE('',*,*,#547,.F.);
#2222=EDGE_LOOP('',(#2213,#2219,#2220,#2221));
#2223=FACE_BOUND('',#2222,.T.);
#2224=ADVANCED_FACE('F1626',(#2223),#2212,.F.);
#2225=CARTESIAN_POINT('',(-0.812800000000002,0.,0.));
#2226=DIRECTION('',(1.,0.,0.));
#2227=DIRECTION('',(0.,0.,-1.));
#2228=AXIS2_PLACEMENT_3D('',#2225,#2226,#2227);
#2229=CYLINDRICAL_SURFACE('',#2228,6.82498);
#2230=ORIENTED_EDGE('',*,*,#883,.T.);
#2231=ORIENTED_EDGE('',*,*,#2201,.F.);
#2232=ORIENTED_EDGE('',*,*,#1683,.F.);
#2233=ORIENTED_EDGE('',*,*,#2218,.T.);
#2234=EDGE_LOOP('',(#2230,#2231,#2232,#2233));
#2235=FACE_BOUND('',#2234,.T.);
#2236=ADVANCED_FACE('F1602',(#2235),#2229,.T.);
#2237=CARTESIAN_POINT('',(-0.812800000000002,-4.6765337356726,8.46155064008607));
#2238=DIRECTION('',(0.,0.963713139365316,0.266940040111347));
#2239=DIRECTION('',(0.,-0.266940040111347,0.963713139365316));
#2240=AXIS2_PLACEMENT_3D('',#2237,#2238,#2239);
#2241=PLANE('',#2240);
#2242=ORIENTED_EDGE('',*,*,#1809,.F.);
#2243=DIRECTION('',(1.,0.,0.));
#2244=VECTOR('',#2243,1.);
#2245=CARTESIAN_POINT('',(-0.812800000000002,-3.88672027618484,5.61014772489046));
#2246=LINE('',#2245,#2244);
#2247=EDGE_CURVE('E930',#1802,#753,#2246,.T.);
#2248=ORIENTED_EDGE('',*,*,#2247,.T.);
#2249=ORIENTED_EDGE('',*,*,#754,.T.);
#2250=ORIENTED_EDGE('',*,*,#449,.F.);
#2251=EDGE_LOOP('',(#2242,#2248,#2249,#2250));
#2252=FACE_BOUND('',#2251,.T.);
#2253=ADVANCED_FACE('F1598',(#2252),#2241,.F.);
#2254=CARTESIAN_POINT('',(-0.812800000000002,-7.20877524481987,6.44215542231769));
#2255=DIRECTION('',(0.,-0.474693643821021,-0.88015109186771));
#2256=DIRECTION('',(0.,0.88015109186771,-0.474693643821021));
#2257=AXIS2_PLACEMENT_3D('',#2254,#2255,#2256);
#2258=PLANE('',#2257);
#2259=ORIENTED_EDGE('',*,*,#769,.T.);
#2260=DIRECTION('',(1.,0.,0.));
#2261=VECTOR('',#2260,1.);
#2262=CARTESIAN_POINT('',(-0.812800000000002,-4.60461298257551,5.03764739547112));
#2263=LINE('',#2262,#2261);
#2264=EDGE_CURVE('E982',#1793,#762,#2263,.T.);
#2265=ORIENTED_EDGE('',*,*,#2264,.F.);
#2266=ORIENTED_EDGE('',*,*,#1794,.F.);
#2267=ORIENTED_EDGE('',*,*,#422,.F.);
#2268=EDGE_LOOP('',(#2259,#2265,#2266,#2267));
#2269=FACE_BOUND('',#2268,.T.);
#2270=ADVANCED_FACE('F1601',(#2269),#2258,.F.);
#2271=CARTESIAN_POINT('',(-0.812800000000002,0.,0.));
#2272=DIRECTION('',(1.,0.,0.));
#2273=DIRECTION('',(0.,0.,-1.));
#2274=AXIS2_PLACEMENT_3D('',#2271,#2272,#2273);
#2275=CYLINDRICAL_SURFACE('',#2274,6.82498);
#2276=ORIENTED_EDGE('',*,*,#763,.T.);
#2277=ORIENTED_EDGE('',*,*,#2247,.F.);
#2278=ORIENTED_EDGE('',*,*,#1803,.F.);
#2279=ORIENTED_EDGE('',*,*,#2264,.T.);
#2280=EDGE_LOOP('',(#2276,#2277,#2278,#2279));
#2281=FACE_BOUND('',#2280,.T.);
#2282=ADVANCED_FACE('F1578',(#2281),#2275,.T.);
#2283=CARTESIAN_POINT('',(-0.812800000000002,-7.88474053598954,5.59452175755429));
#2284=DIRECTION('',(0.,0.752454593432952,0.658644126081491));
#2285=DIRECTION('',(0.,-0.658644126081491,0.752454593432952));
#2286=AXIS2_PLACEMENT_3D('',#2283,#2284,#2285);
#2287=PLANE('',#2286);
#2288=ORIENTED_EDGE('',*,*,#1785,.F.);
#2289=DIRECTION('',(1.,0.,0.));
#2290=VECTOR('',#2289,1.);
#2291=CARTESIAN_POINT('',(-0.812800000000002,-5.93596583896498,3.36818371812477));
#2292=LINE('',#2291,#2290);
#2293=EDGE_CURVE('E952',#1778,#777,#2292,.T.);
#2294=ORIENTED_EDGE('',*,*,#2293,.T.);
#2295=ORIENTED_EDGE('',*,*,#778,.T.);
#2296=ORIENTED_EDGE('',*,*,#412,.F.);
#2297=EDGE_LOOP('',(#2288,#2294,#2295,#2296));
#2298=FACE_BOUND('',#2297,.T.);
#2299=ADVANCED_FACE('F1574',(#2298),#2287,.F.);
#2300=CARTESIAN_POINT('',(-0.812800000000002,-9.29002855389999,2.67641112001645));
#2301=DIRECTION('',(0.,-0.0458009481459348,-0.998950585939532));
#2302=DIRECTION('',(0.,0.998950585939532,-0.0458009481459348));
#2303=AXIS2_PLACEMENT_3D('',#2300,#2301,#2302);
#2304=PLANE('',#2303);
#2305=ORIENTED_EDGE('',*,*,#793,.T.);
#2306=DIRECTION('',(1.,0.,0.));
#2307=VECTOR('',#2306,1.);
#2308=CARTESIAN_POINT('',(-0.812800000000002,-6.33436623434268,2.54089677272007));
#2309=LINE('',#2308,#2307);
#2310=EDGE_CURVE('E944',#1769,#786,#2309,.T.);
#2311=ORIENTED_EDGE('',*,*,#2310,.F.);
#2312=ORIENTED_EDGE('',*,*,#1770,.F.);
#2313=ORIENTED_EDGE('',*,*,#395,.F.);
#2314=EDGE_LOOP('',(#2305,#2311,#2312,#2313));
#2315=FACE_BOUND('',#2314,.T.);
#2316=ADVANCED_FACE('F1577',(#2315),#2304,.F.);
#2317=CARTESIAN_POINT('',(-0.812800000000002,0.,0.));
#2318=DIRECTION('',(1.,0.,0.));
#2319=DIRECTION('',(0.,0.,-1.));
#2320=AXIS2_PLACEMENT_3D('',#2317,#2318,#2319);
#2321=CYLINDRICAL_SURFACE('',#2320,6.82498);
#2322=ORIENTED_EDGE('',*,*,#787,.T.);
#2323=ORIENTED_EDGE('',*,*,#2293,.F.);
#2324=ORIENTED_EDGE('',*,*,#1779,.F.);
#2325=ORIENTED_EDGE('',*,*,#2310,.T.);
#2326=EDGE_LOOP('',(#2322,#2323,#2324,#2325));
#2327=FACE_BOUND('',#2326,.T.);
#2328=ADVANCED_FACE('F1580',(#2327),#2321,.T.);
#2329=CARTESIAN_POINT('',(-0.812800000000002,-9.531277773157,1.61942922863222));
#2330=DIRECTION('',(0.,0.392163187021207,0.919895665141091));
#2331=DIRECTION('',(0.,-0.919895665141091,0.392163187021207));
#2332=AXIS2_PLACEMENT_3D('',#2329,#2330,#2331);
#2333=PLANE('',#2332);
#2334=ORIENTED_EDGE('',*,*,#1761,.F.);
#2335=DIRECTION('',(1.,0.,0.));
#2336=VECTOR('',#2335,1.);
#2337=CARTESIAN_POINT('',(-0.812800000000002,-6.80952056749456,0.459109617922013));
#2338=LINE('',#2337,#2336);
#2339=EDGE_CURVE('E948',#1754,#801,#2338,.T.);
#2340=ORIENTED_EDGE('',*,*,#2339,.T.);
#2341=ORIENTED_EDGE('',*,*,#802,.T.);
#2342=ORIENTED_EDGE('',*,*,#385,.F.);
#2343=EDGE_LOOP('',(#2334,#2340,#2341,#2342));
#2344=FACE_BOUND('',#2343,.T.);
#2345=ADVANCED_FACE('F1583',(#2344),#2333,.F.);
#2346=CARTESIAN_POINT('',(-0.812800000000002,-9.53127777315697,-1.61942922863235));
#2347=DIRECTION('',(0.,0.39216318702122,-0.919895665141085));
#2348=DIRECTION('',(0.,0.919895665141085,0.39216318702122));
#2349=AXIS2_PLACEMENT_3D('',#2346,#2347,#2348);
#2350=PLANE('',#2349);
#2351=ORIENTED_EDGE('',*,*,#817,.T.);
#2352=DIRECTION('',(1.,0.,0.));
#2353=VECTOR('',#2352,1.);
#2354=CARTESIAN_POINT('',(-0.812800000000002,-6.80952056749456,-0.459109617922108));
#2355=LINE('',#2354,#2353);
#2356=EDGE_CURVE('E964',#1745,#810,#2355,.T.);
#2357=ORIENTED_EDGE('',*,*,#2356,.F.);
#2358=ORIENTED_EDGE('',*,*,#1746,.F.);
#2359=ORIENTED_EDGE('',*,*,#520,.F.);
#2360=EDGE_LOOP('',(#2351,#2357,#2358,#2359));
#2361=FACE_BOUND('',#2360,.T.);
#2362=ADVANCED_FACE('F1590',(#2361),#2350,.F.);
#2363=CARTESIAN_POINT('',(-0.812800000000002,0.,0.));
#2364=DIRECTION('',(1.,0.,0.));
#2365=DIRECTION('',(0.,0.,-1.));
#2366=AXIS2_PLACEMENT_3D('',#2363,#2364,#2365);
#2367=CYLINDRICAL_SURFACE('',#2366,6.82498);
#2368=ORIENTED_EDGE('',*,*,#811,.T.);
#2369=ORIENTED_EDGE('',*,*,#2339,.F.);
#2370=ORIENTED_EDGE('',*,*,#1755,.F.);
#2371=ORIENTED_EDGE('',*,*,#2356,.T.);
#2372=EDGE_LOOP('',(#2368,#2369,#2370,#2371));
#2373=FACE_BOUND('',#2372,.T.);
#2374=ADVANCED_FACE('F1566',(#2373),#2367,.T.);
#2375=CARTESIAN_POINT('',(-0.812800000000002,-0.542082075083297,9.65266564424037));
#2376=DIRECTION('',(0.,0.984096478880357,-0.177634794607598));
#2377=DIRECTION('',(0.,0.177634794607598,0.984096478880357));
#2378=AXIS2_PLACEMENT_3D('',#2375,#2376,#2377);
#2379=PLANE('',#2378);
#2380=ORIENTED_EDGE('',*,*,#1833,.F.);
#2381=DIRECTION('',(1.,0.,0.));
#2382=VECTOR('',#2381,1.);
#2383=CARTESIAN_POINT('',(-0.812800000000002,-1.0676620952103,6.740953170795));
#2384=LINE('',#2383,#2382);
#2385=EDGE_CURVE('E912',#1826,#729,#2384,.T.);
#2386=ORIENTED_EDGE('',*,*,#2385,.T.);
#2387=ORIENTED_EDGE('',*,*,#730,.T.);
#2388=ORIENTED_EDGE('',*,*,#368,.F.);
#2389=EDGE_LOOP('',(#2380,#2386,#2387,#2388));
#2390=FACE_BOUND('',#2389,.T.);
#2391=ADVANCED_FACE('F1562',(#2390),#2379,.F.);
#2392=CARTESIAN_POINT('',(-0.812800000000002,-3.69973558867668,8.93195183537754));
#2393=DIRECTION('',(0.,-0.809567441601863,-0.587026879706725));
#2394=DIRECTION('',(0.,0.587026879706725,-0.809567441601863));
#2395=AXIS2_PLACEMENT_3D('',#2392,#2393,#2394);
#2396=PLANE('',#2395);
#2397=ORIENTED_EDGE('',*,*,#745,.T.);
#2398=DIRECTION('',(1.,0.,0.));
#2399=VECTOR('',#2398,1.);
#2400=CARTESIAN_POINT('',(-0.812800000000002,-1.962859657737,6.53663016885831));
#2401=LINE('',#2400,#2399);
#2402=EDGE_CURVE('E926',#1817,#738,#2401,.T.);
#2403=ORIENTED_EDGE('',*,*,#2402,.F.);
#2404=ORIENTED_EDGE('',*,*,#1818,.F.);
#2405=ORIENTED_EDGE('',*,*,#439,.F.);
#2406=EDGE_LOOP('',(#2397,#2403,#2404,#2405));
#2407=FACE_BOUND('',#2406,.T.);
#2408=ADVANCED_FACE('F1565',(#2407),#2396,.F.);
#2409=CARTESIAN_POINT('',(-0.812800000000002,0.,0.));
#2410=DIRECTION('',(1.,0.,0.));
#2411=DIRECTION('',(0.,0.,-1.));
#2412=AXIS2_PLACEMENT_3D('',#2409,#2410,#2411);
#2413=CYLINDRICAL_SURFACE('',#2412,6.82498);
#2414=ORIENTED_EDGE('',*,*,#739,.T.);
#2415=ORIENTED_EDGE('',*,*,#2385,.F.);
#2416=ORIENTED_EDGE('',*,*,#1827,.F.);
#2417=ORIENTED_EDGE('',*,*,#2402,.T.);
#2418=EDGE_LOOP('',(#2414,#2415,#2416,#2417));
#2419=FACE_BOUND('',#2418,.T.);
#2420=ADVANCED_FACE('F1554',(#2419),#2413,.T.);
#2421=CARTESIAN_POINT('',(-0.812800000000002,3.69973558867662,8.93195183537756));
#2422=DIRECTION('',(0.,0.809567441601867,-0.587026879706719));
#2423=DIRECTION('',(0.,0.587026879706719,0.809567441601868));
#2424=AXIS2_PLACEMENT_3D('',#2421,#2422,#2423);
#2425=PLANE('',#2424);
#2426=ORIENTED_EDGE('',*,*,#1857,.F.);
#2427=DIRECTION('',(1.,0.,0.));
#2428=VECTOR('',#2427,1.);
#2429=CARTESIAN_POINT('',(-0.812800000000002,1.96285965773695,6.53663016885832));
#2430=LINE('',#2429,#2428);
#2431=EDGE_CURVE('E892',#1850,#705,#2430,.T.);
#2432=ORIENTED_EDGE('',*,*,#2431,.T.);
#2433=ORIENTED_EDGE('',*,*,#706,.T.);
#2434=ORIENTED_EDGE('',*,*,#341,.F.);
#2435=EDGE_LOOP('',(#2426,#2432,#2433,#2434));
#2436=FACE_BOUND('',#2435,.T.);
#2437=ADVANCED_FACE('F1550',(#2436),#2425,.F.);
#2438=CARTESIAN_POINT('',(-0.812800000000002,0.54208207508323,9.65266564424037));
#2439=DIRECTION('',(0.,-0.984096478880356,-0.177634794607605));
#2440=DIRECTION('',(0.,0.177634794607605,-0.984096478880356));
#2441=AXIS2_PLACEMENT_3D('',#2438,#2439,#2440);
#2442=PLANE('',#2441);
#2443=ORIENTED_EDGE('',*,*,#721,.T.);
#2444=DIRECTION('',(1.,0.,0.));
#2445=VECTOR('',#2444,1.);
#2446=CARTESIAN_POINT('',(-0.812800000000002,1.06766209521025,6.740953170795));
#2447=LINE('',#2446,#2445);
#2448=EDGE_CURVE('E908',#1841,#714,#2447,.T.);
#2449=ORIENTED_EDGE('',*,*,#2448,.F.);
#2450=ORIENTED_EDGE('',*,*,#1842,.F.);
#2451=ORIENTED_EDGE('',*,*,#358,.F.);
#2452=EDGE_LOOP('',(#2443,#2449,#2450,#2451));
#2453=FACE_BOUND('',#2452,.T.);
#2454=ADVANCED_FACE('F1553',(#2453),#2442,.F.);
#2455=CARTESIAN_POINT('',(-0.812800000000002,0.,0.));
#2456=DIRECTION('',(1.,0.,0.));
#2457=DIRECTION('',(0.,0.,-1.));
#2458=AXIS2_PLACEMENT_3D('',#2455,#2456,#2457);
#2459=CYLINDRICAL_SURFACE('',#2458,6.82498);
#2460=ORIENTED_EDGE('',*,*,#715,.T.);
#2461=ORIENTED_EDGE('',*,*,#2431,.F.);
#2462=ORIENTED_EDGE('',*,*,#1851,.F.);
#2463=ORIENTED_EDGE('',*,*,#2448,.T.);
#2464=EDGE_LOOP('',(#2460,#2461,#2462,#2463));
#2465=FACE_BOUND('',#2464,.T.);
#2466=ADVANCED_FACE('F1542',(#2465),#2459,.T.);
#2467=CARTESIAN_POINT('',(-0.812800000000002,7.20877524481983,6.44215542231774));
#2468=DIRECTION('',(0.,0.474693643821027,-0.880151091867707));
#2469=DIRECTION('',(0.,0.880151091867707,0.474693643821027));
#2470=AXIS2_PLACEMENT_3D('',#2467,#2468,#2469);
#2471=PLANE('',#2470);
#2472=ORIENTED_EDGE('',*,*,#1545,.F.);
#2473=DIRECTION('',(1.,0.,0.));
#2474=VECTOR('',#2473,1.);
#2475=CARTESIAN_POINT('',(-0.812800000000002,4.60461298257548,5.03764739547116));
#2476=LINE('',#2475,#2474);
#2477=EDGE_CURVE('E896',#1538,#681,#2476,.T.);
#2478=ORIENTED_EDGE('',*,*,#2477,.T.);
#2479=ORIENTED_EDGE('',*,*,#682,.T.);
#2480=ORIENTED_EDGE('',*,*,#299,.F.);
#2481=EDGE_LOOP('',(#2472,#2478,#2479,#2480));
#2482=FACE_BOUND('',#2481,.T.);
#2483=ADVANCED_FACE('F1538',(#2482),#2471,.F.);
#2484=CARTESIAN_POINT('',(-0.812800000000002,4.67653373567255,8.4615506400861));
#2485=DIRECTION('',(0.,-0.963713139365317,0.26694004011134));
#2486=DIRECTION('',(0.,-0.26694004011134,-0.963713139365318));
#2487=AXIS2_PLACEMENT_3D('',#2484,#2485,#2486);
#2488=PLANE('',#2487);
#2489=ORIENTED_EDGE('',*,*,#697,.T.);
#2490=DIRECTION('',(1.,0.,0.));
#2491=VECTOR('',#2490,1.);
#2492=CARTESIAN_POINT('',(-0.812800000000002,3.88672027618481,5.61014772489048));
#2493=LINE('',#2492,#2491);
#2494=EDGE_CURVE('E888',#1536,#690,#2493,.T.);
#2495=ORIENTED_EDGE('',*,*,#2494,.F.);
#2496=ORIENTED_EDGE('',*,*,#1864,.F.);
#2497=ORIENTED_EDGE('',*,*,#331,.F.);
#2498=EDGE_LOOP('',(#2489,#2495,#2496,#2497));
#2499=FACE_BOUND('',#2498,.T.);
#2500=ADVANCED_FACE('F1541',(#2499),#2488,.F.);
#2501=CARTESIAN_POINT('',(-0.812800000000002,0.,0.));
#2502=DIRECTION('',(1.,0.,0.));
#2503=DIRECTION('',(0.,0.,-1.));
#2504=AXIS2_PLACEMENT_3D('',#2501,#2502,#2503);
#2505=CYLINDRICAL_SURFACE('',#2504,6.82498);
#2506=ORIENTED_EDGE('',*,*,#691,.T.);
#2507=ORIENTED_EDGE('',*,*,#2477,.F.);
#2508=ORIENTED_EDGE('',*,*,#1539,.F.);
#2509=ORIENTED_EDGE('',*,*,#2494,.T.);
#2510=EDGE_LOOP('',(#2506,#2507,#2508,#2509));
#2511=FACE_BOUND('',#2510,.T.);
#2512=ADVANCED_FACE('F1534',(#2511),#2505,.T.);
#2513=CARTESIAN_POINT('',(-0.812800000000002,4.90380047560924,0.385937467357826));
#2514=DIRECTION('',(0.,0.136441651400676,0.990648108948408));
#2515=DIRECTION('',(0.,-0.990648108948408,0.136441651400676));
#2516=AXIS2_PLACEMENT_3D('',#2513,#2514,#2515);
#2517=PLANE('',#2516);
#2518=ORIENTED_EDGE('',*,*,#1495,.F.);
#2519=DIRECTION('',(1.,0.,0.));
#2520=VECTOR('',#2519,1.);
#2521=CARTESIAN_POINT('',(-0.812800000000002,4.90380047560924,0.385937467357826));
#2522=LINE('',#2521,#2520);
#2523=EDGE_CURVE('E870',#1488,#1072,#2522,.T.);
#2524=ORIENTED_EDGE('',*,*,#2523,.T.);
#2525=ORIENTED_EDGE('',*,*,#1073,.T.);
#2526=ORIENTED_EDGE('',*,*,#665,.F.);
#2527=EDGE_LOOP('',(#2518,#2524,#2525,#2526));
#2528=FACE_BOUND('',#2527,.T.);
#2529=ADVANCED_FACE('F1452',(#2528),#2517,.F.);
#2530=CARTESIAN_POINT('',(-0.812800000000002,4.90380047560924,-0.385937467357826));
#2531=DIRECTION('',(0.,0.136441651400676,-0.990648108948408));
#2532=DIRECTION('',(0.,0.990648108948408,0.136441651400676));
#2533=AXIS2_PLACEMENT_3D('',#2530,#2531,#2532);
#2534=PLANE('',#2533);
#2535=ORIENTED_EDGE('',*,*,#1088,.T.);
#2536=DIRECTION('',(1.,0.,0.));
#2537=VECTOR('',#2536,1.);
#2538=CARTESIAN_POINT('',(-0.812800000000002,4.90380047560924,-0.385937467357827));
#2539=LINE('',#2538,#2537);
#2540=EDGE_CURVE('E863',#1479,#1081,#2539,.T.);
#2541=ORIENTED_EDGE('',*,*,#2540,.F.);
#2542=ORIENTED_EDGE('',*,*,#1480,.F.);
#2543=ORIENTED_EDGE('',*,*,#245,.F.);
#2544=EDGE_LOOP('',(#2535,#2541,#2542,#2543));
#2545=FACE_BOUND('',#2544,.T.);
#2546=ADVANCED_FACE('F1459',(#2545),#2534,.F.);
#2547=CARTESIAN_POINT('',(-0.812800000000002,0.,0.));
#2548=DIRECTION('',(1.,0.,0.));
#2549=DIRECTION('',(0.,0.,-1.));
#2550=AXIS2_PLACEMENT_3D('',#2547,#2548,#2549);
#2551=CYLINDRICAL_SURFACE('',#2550,4.918964);
#2552=ORIENTED_EDGE('',*,*,#1082,.T.);
#2553=ORIENTED_EDGE('',*,*,#2523,.F.);
#2554=ORIENTED_EDGE('',*,*,#1489,.F.);
#2555=ORIENTED_EDGE('',*,*,#2540,.T.);
#2556=EDGE_LOOP('',(#2552,#2553,#2554,#2555));
#2557=FACE_BOUND('',#2556,.T.);
#2558=ADVANCED_FACE('F1456',(#2557),#2551,.F.);
#2559=CARTESIAN_POINT('',(-0.812800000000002,3.74040957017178,3.19461156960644));
#2560=DIRECTION('',(0.,-0.471904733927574,0.881649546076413));
#2561=DIRECTION('',(0.,-0.881649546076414,-0.471904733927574));
#2562=AXIS2_PLACEMENT_3D('',#2559,#2560,#2561);
#2563=PLANE('',#2562);
#2564=ORIENTED_EDGE('',*,*,#1519,.F.);
#2565=DIRECTION('',(1.,0.,0.));
#2566=VECTOR('',#2565,1.);
#2567=CARTESIAN_POINT('',(-0.812800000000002,3.74040957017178,3.19461156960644));
#2568=LINE('',#2567,#2566);
#2569=EDGE_CURVE('E845',#1512,#1048,#2568,.T.);
#2570=ORIENTED_EDGE('',*,*,#2569,.T.);
#2571=ORIENTED_EDGE('',*,*,#1049,.T.);
#2572=ORIENTED_EDGE('',*,*,#272,.F.);
#2573=EDGE_LOOP('',(#2564,#2570,#2571,#2572));
#2574=FACE_BOUND('',#2573,.T.);
#2575=ADVANCED_FACE('F1443',(#2574),#2563,.F.);
#2576=CARTESIAN_POINT('',(-0.812800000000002,4.19410627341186,2.57015162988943));
#2577=DIRECTION('',(0.,0.692671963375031,-0.721252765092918));
#2578=DIRECTION('',(0.,0.721252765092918,0.692671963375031));
#2579=AXIS2_PLACEMENT_3D('',#2576,#2577,#2578);
#2580=PLANE('',#2579);
#2581=ORIENTED_EDGE('',*,*,#1064,.T.);
#2582=DIRECTION('',(1.,0.,0.));
#2583=VECTOR('',#2582,1.);
#2584=CARTESIAN_POINT('',(-0.812800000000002,4.19410627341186,2.57015162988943));
#2585=LINE('',#2584,#2583);
#2586=EDGE_CURVE('E838',#1503,#1057,#2585,.T.);
#2587=ORIENTED_EDGE('',*,*,#2586,.F.);
#2588=ORIENTED_EDGE('',*,*,#1504,.F.);
#2589=ORIENTED_EDGE('',*,*,#655,.F.);
#2590=EDGE_LOOP('',(#2581,#2587,#2588,#2589));
#2591=FACE_BOUND('',#2590,.T.);
#2592=ADVANCED_FACE('F1449',(#2591),#2580,.F.);
#2593=CARTESIAN_POINT('',(-0.812800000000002,0.,0.));
#2594=DIRECTION('',(1.,0.,0.));
#2595=DIRECTION('',(0.,0.,-1.));
#2596=AXIS2_PLACEMENT_3D('',#2593,#2594,#2595);
#2597=CYLINDRICAL_SURFACE('',#2596,4.918964);
#2598=ORIENTED_EDGE('',*,*,#1058,.T.);
#2599=ORIENTED_EDGE('',*,*,#2569,.F.);
#2600=ORIENTED_EDGE('',*,*,#1513,.F.);
#2601=ORIENTED_EDGE('',*,*,#2586,.T.);
#2602=EDGE_LOOP('',(#2598,#2599,#2600,#2601));
#2603=FACE_BOUND('',#2602,.T.);
#2604=ADVANCED_FACE('F1446',(#2603),#2597,.F.);
#2605=CARTESIAN_POINT('',(-0.812800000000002,4.1941062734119,-2.57015162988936));
#2606=DIRECTION('',(0.,0.692671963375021,0.721252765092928));
#2607=DIRECTION('',(0.,-0.721252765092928,0.692671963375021));
#2608=AXIS2_PLACEMENT_3D('',#2605,#2606,#2607);
#2609=PLANE('',#2608);
#2610=ORIENTED_EDGE('',*,*,#1471,.F.);
#2611=DIRECTION('',(1.,0.,0.));
#2612=VECTOR('',#2611,1.);
#2613=CARTESIAN_POINT('',(-0.812800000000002,4.1941062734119,-2.57015162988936));
#2614=LINE('',#2613,#2612);
#2615=EDGE_CURVE('E761',#1464,#1096,#2614,.T.);
#2616=ORIENTED_EDGE('',*,*,#2615,.T.);
#2617=ORIENTED_EDGE('',*,*,#1097,.T.);
#2618=ORIENTED_EDGE('',*,*,#235,.F.);
#2619=EDGE_LOOP('',(#2610,#2616,#2617,#2618));
#2620=FACE_BOUND('',#2619,.T.);
#2621=ADVANCED_FACE('F1465',(#2620),#2609,.F.);
#2622=CARTESIAN_POINT('',(-0.812800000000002,3.74040957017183,-3.19461156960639));
#2623=DIRECTION('',(0.,-0.471904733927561,-0.88164954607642));
#2624=DIRECTION('',(0.,0.88164954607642,-0.471904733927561));
#2625=AXIS2_PLACEMENT_3D('',#2622,#2623,#2624);
#2626=PLANE('',#2625);
#2627=ORIENTED_EDGE('',*,*,#1112,.T.);
#2628=DIRECTION('',(1.,0.,0.));
#2629=VECTOR('',#2628,1.);
#2630=CARTESIAN_POINT('',(-0.812800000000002,3.74040957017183,-3.19461156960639));
#2631=LINE('',#2630,#2629);
#2632=EDGE_CURVE('E775',#1455,#1105,#2631,.T.);
#2633=ORIENTED_EDGE('',*,*,#2632,.F.);
#2634=ORIENTED_EDGE('',*,*,#1456,.F.);
#2635=ORIENTED_EDGE('',*,*,#218,.F.);
#2636=EDGE_LOOP('',(#2627,#2633,#2634,#2635));
#2637=FACE_BOUND('',#2636,.T.);
#2638=ADVANCED_FACE('F1471',(#2637),#2626,.F.);
#2639=CARTESIAN_POINT('',(-0.812800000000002,0.,0.));
#2640=DIRECTION('',(1.,0.,0.));
#2641=DIRECTION('',(0.,0.,-1.));
#2642=AXIS2_PLACEMENT_3D('',#2639,#2640,#2641);
#2643=CYLINDRICAL_SURFACE('',#2642,4.918964);
#2644=ORIENTED_EDGE('',*,*,#1106,.T.);
#2645=ORIENTED_EDGE('',*,*,#2615,.F.);
#2646=ORIENTED_EDGE('',*,*,#1465,.F.);
#2647=ORIENTED_EDGE('',*,*,#2632,.T.);
#2648=EDGE_LOOP('',(#2644,#2645,#2646,#2647));
#2649=FACE_BOUND('',#2648,.T.);
#2650=ADVANCED_FACE('F1468',(#2649),#2643,.F.);
#2651=CARTESIAN_POINT('',(-0.812800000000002,1.88240602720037,-4.54453016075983));
#2652=DIRECTION('',(0.,0.984325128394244,0.176363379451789));
#2653=DIRECTION('',(0.,-0.176363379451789,0.984325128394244));
#2654=AXIS2_PLACEMENT_3D('',#2651,#2652,#2653);
#2655=PLANE('',#2654);
#2656=ORIENTED_EDGE('',*,*,#1447,.F.);
#2657=DIRECTION('',(1.,0.,0.));
#2658=VECTOR('',#2657,1.);
#2659=CARTESIAN_POINT('',(-0.812800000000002,1.88240602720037,-4.54453016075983));
#2660=LINE('',#2659,#2658);
#2661=EDGE_CURVE('E743',#1440,#1120,#2660,.T.);
#2662=ORIENTED_EDGE('',*,*,#2661,.T.);
#2663=ORIENTED_EDGE('',*,*,#1121,.T.);
#2664=ORIENTED_EDGE('',*,*,#208,.F.);
#2665=EDGE_LOOP('',(#2656,#2662,#2663,#2664));
#2666=FACE_BOUND('',#2665,.T.);
#2667=ADVANCED_FACE('F1474',(#2666),#2655,.F.);
#2668=CARTESIAN_POINT('',(-0.812800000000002,1.14830934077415,-4.78305263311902));
#2669=DIRECTION('',(0.,-0.899999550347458,-0.435890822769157));
#2670=DIRECTION('',(0.,0.435890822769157,-0.899999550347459));
#2671=AXIS2_PLACEMENT_3D('',#2668,#2669,#2670);
#2672=PLANE('',#2671);
#2673=ORIENTED_EDGE('',*,*,#1136,.T.);
#2674=DIRECTION('',(1.,0.,0.));
#2675=VECTOR('',#2674,1.);
#2676=CARTESIAN_POINT('',(-0.812800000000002,1.14830934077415,-4.78305263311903));
#2677=LINE('',#2676,#2675);
#2678=EDGE_CURVE('E757',#1431,#1129,#2677,.T.);
#2679=ORIENTED_EDGE('',*,*,#2678,.F.);
#2680=ORIENTED_EDGE('',*,*,#1432,.F.);
#2681=ORIENTED_EDGE('',*,*,#191,.F.);
#2682=EDGE_LOOP('',(#2673,#2679,#2680,#2681));
#2683=FACE_BOUND('',#2682,.T.);
#2684=ADVANCED_FACE('F1480',(#2683),#2672,.F.);
#2685=CARTESIAN_POINT('',(-0.812800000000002,0.,0.));
#2686=DIRECTION('',(1.,0.,0.));
#2687=DIRECTION('',(0.,0.,-1.));
#2688=AXIS2_PLACEMENT_3D('',#2685,#2686,#2687);
#2689=CYLINDRICAL_SURFACE('',#2688,4.918964);
#2690=ORIENTED_EDGE('',*,*,#1130,.T.);
#2691=ORIENTED_EDGE('',*,*,#2661,.F.);
#2692=ORIENTED_EDGE('',*,*,#1441,.F.);
#2693=ORIENTED_EDGE('',*,*,#2678,.T.);
#2694=EDGE_LOOP('',(#2690,#2691,#2692,#2693));
#2695=FACE_BOUND('',#2694,.T.);
#2696=ADVANCED_FACE('F1477',(#2695),#2689,.F.);
#2697=CARTESIAN_POINT('',(-0.812800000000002,-1.14830934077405,-4.78305263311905));
#2698=DIRECTION('',(0.,0.899999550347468,-0.435890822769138));
#2699=DIRECTION('',(0.,0.435890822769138,0.899999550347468));
#2700=AXIS2_PLACEMENT_3D('',#2697,#2698,#2699);
#2701=PLANE('',#2700);
#2702=ORIENTED_EDGE('',*,*,#1423,.F.);
#2703=DIRECTION('',(1.,0.,0.));
#2704=VECTOR('',#2703,1.);
#2705=CARTESIAN_POINT('',(-0.812800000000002,-1.14830934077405,-4.78305263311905));
#2706=LINE('',#2705,#2704);
#2707=EDGE_CURVE('E725',#1416,#1144,#2706,.T.);
#2708=ORIENTED_EDGE('',*,*,#2707,.T.);
#2709=ORIENTED_EDGE('',*,*,#1145,.T.);
#2710=ORIENTED_EDGE('',*,*,#181,.F.);
#2711=EDGE_LOOP('',(#2702,#2708,#2709,#2710));
#2712=FACE_BOUND('',#2711,.T.);
#2713=ADVANCED_FACE('F1484',(#2712),#2701,.F.);
#2714=CARTESIAN_POINT('',(-0.812800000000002,-1.88240602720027,-4.54453016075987));
#2715=DIRECTION('',(0.,-0.984325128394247,0.176363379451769));
#2716=DIRECTION('',(0.,-0.176363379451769,-0.984325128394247));
#2717=AXIS2_PLACEMENT_3D('',#2714,#2715,#2716);
#2718=PLANE('',#2717);
#2719=ORIENTED_EDGE('',*,*,#1160,.T.);
#2720=DIRECTION('',(1.,0.,0.));
#2721=VECTOR('',#2720,1.);
#2722=CARTESIAN_POINT('',(-0.812800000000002,-1.88240602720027,-4.54453016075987));
#2723=LINE('',#2722,#2721);
#2724=EDGE_CURVE('E739',#1407,#1153,#2723,.T.);
#2725=ORIENTED_EDGE('',*,*,#2724,.F.);
#2726=ORIENTED_EDGE('',*,*,#1408,.F.);
#2727=ORIENTED_EDGE('',*,*,#164,.F.);
#2728=EDGE_LOOP('',(#2719,#2725,#2726,#2727));
#2729=FACE_BOUND('',#2728,.T.);
#2730=ADVANCED_FACE('F1490',(#2729),#2718,.F.);
#2731=CARTESIAN_POINT('',(-0.812800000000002,0.,0.));
#2732=DIRECTION('',(1.,0.,0.));
#2733=DIRECTION('',(0.,0.,-1.));
#2734=AXIS2_PLACEMENT_3D('',#2731,#2732,#2733);
#2735=CYLINDRICAL_SURFACE('',#2734,4.918964);
#2736=ORIENTED_EDGE('',*,*,#1154,.T.);
#2737=ORIENTED_EDGE('',*,*,#2707,.F.);
#2738=ORIENTED_EDGE('',*,*,#1417,.F.);
#2739=ORIENTED_EDGE('',*,*,#2724,.T.);
#2740=EDGE_LOOP('',(#2736,#2737,#2738,#2739));
#2741=FACE_BOUND('',#2740,.T.);
#2742=ADVANCED_FACE('F1487',(#2741),#2735,.F.);
#2743=CARTESIAN_POINT('',(-0.812800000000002,-3.74040957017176,-3.19461156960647));
#2744=DIRECTION('',(0.,0.47190473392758,-0.88164954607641));
#2745=DIRECTION('',(0.,0.88164954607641,0.47190473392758));
#2746=AXIS2_PLACEMENT_3D('',#2743,#2744,#2745);
#2747=PLANE('',#2746);
#2748=ORIENTED_EDGE('',*,*,#1399,.F.);
#2749=DIRECTION('',(1.,0.,0.));
#2750=VECTOR('',#2749,1.);
#2751=CARTESIAN_POINT('',(-0.812800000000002,-3.74040957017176,-3.19461156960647));
#2752=LINE('',#2751,#2750);
#2753=EDGE_CURVE('E707',#1392,#1168,#2752,.T.);
#2754=ORIENTED_EDGE('',*,*,#2753,.T.);
#2755=ORIENTED_EDGE('',*,*,#1169,.T.);
#2756=ORIENTED_EDGE('',*,*,#154,.F.);
#2757=EDGE_LOOP('',(#2748,#2754,#2755,#2756));
#2758=FACE_BOUND('',#2757,.T.);
#2759=ADVANCED_FACE('F1494',(#2758),#2747,.F.);
#2760=CARTESIAN_POINT('',(-0.812800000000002,-4.19410627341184,-2.57015162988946));
#2761=DIRECTION('',(0.,-0.692671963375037,0.721252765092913));
#2762=DIRECTION('',(0.,-0.721252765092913,-0.692671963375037));
#2763=AXIS2_PLACEMENT_3D('',#2760,#2761,#2762);
#2764=PLANE('',#2763);
#2765=ORIENTED_EDGE('',*,*,#1184,.T.);
#2766=DIRECTION('',(1.,0.,0.));
#2767=VECTOR('',#2766,1.);
#2768=CARTESIAN_POINT('',(-0.812800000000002,-4.19410627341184,-2.57015162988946));
#2769=LINE('',#2768,#2767);
#2770=EDGE_CURVE('E721',#1383,#1177,#2769,.T.);
#2771=ORIENTED_EDGE('',*,*,#2770,.F.);
#2772=ORIENTED_EDGE('',*,*,#1384,.F.);
#2773=ORIENTED_EDGE('',*,*,#137,.F.);
#2774=EDGE_LOOP('',(#2765,#2771,#2772,#2773));
#2775=FACE_BOUND('',#2774,.T.);
#2776=ADVANCED_FACE('F1499',(#2775),#2764,.F.);
#2777=CARTESIAN_POINT('',(-0.812800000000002,0.,0.));
#2778=DIRECTION('',(1.,0.,0.));
#2779=DIRECTION('',(0.,0.,-1.));
#2780=AXIS2_PLACEMENT_3D('',#2777,#2778,#2779);
#2781=CYLINDRICAL_SURFACE('',#2780,4.918964);
#2782=ORIENTED_EDGE('',*,*,#1178,.T.);
#2783=ORIENTED_EDGE('',*,*,#2753,.F.);
#2784=ORIENTED_EDGE('',*,*,#1393,.F.);
#2785=ORIENTED_EDGE('',*,*,#2770,.T.);
#2786=EDGE_LOOP('',(#2782,#2783,#2784,#2785));
#2787=FACE_BOUND('',#2786,.T.);
#2788=ADVANCED_FACE('F1410',(#2787),#2781,.F.);
#2789=CARTESIAN_POINT('',(-0.812800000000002,-4.90380047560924,-0.385937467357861));
#2790=DIRECTION('',(0.,-0.136441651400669,-0.990648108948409));
#2791=DIRECTION('',(0.,0.990648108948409,-0.136441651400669));
#2792=AXIS2_PLACEMENT_3D('',#2789,#2790,#2791);
#2793=PLANE('',#2792);
#2794=ORIENTED_EDGE('',*,*,#1375,.F.);
#2795=DIRECTION('',(1.,0.,0.));
#2796=VECTOR('',#2795,1.);
#2797=CARTESIAN_POINT('',(-0.812800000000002,-4.90380047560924,-0.385937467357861));
#2798=LINE('',#2797,#2796);
#2799=EDGE_CURVE('E689',#1368,#1192,#2798,.T.);
#2800=ORIENTED_EDGE('',*,*,#2799,.T.);
#2801=ORIENTED_EDGE('',*,*,#1193,.T.);
#2802=ORIENTED_EDGE('',*,*,#127,.F.);
#2803=EDGE_LOOP('',(#2794,#2800,#2801,#2802));
#2804=FACE_BOUND('',#2803,.T.);
#2805=ADVANCED_FACE('F1397',(#2804),#2793,.F.);
#2806=CARTESIAN_POINT('',(-0.812800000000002,-4.90380047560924,0.385937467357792));
#2807=DIRECTION('',(0.,-0.136441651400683,0.990648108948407));
#2808=DIRECTION('',(0.,-0.990648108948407,-0.136441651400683));
#2809=AXIS2_PLACEMENT_3D('',#2806,#2807,#2808);
#2810=PLANE('',#2809);
#2811=ORIENTED_EDGE('',*,*,#1208,.T.);
#2812=DIRECTION('',(1.,0.,0.));
#2813=VECTOR('',#2812,1.);
#2814=CARTESIAN_POINT('',(-0.812800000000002,-4.90380047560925,0.385937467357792));
#2815=LINE('',#2814,#2813);
#2816=EDGE_CURVE('E703',#1359,#1201,#2815,.T.);
#2817=ORIENTED_EDGE('',*,*,#2816,.F.);
#2818=ORIENTED_EDGE('',*,*,#1360,.F.);
#2819=ORIENTED_EDGE('',*,*,#110,.F.);
#2820=EDGE_LOOP('',(#2811,#2817,#2818,#2819));
#2821=FACE_BOUND('',#2820,.T.);
#2822=ADVANCED_FACE('F1402',(#2821),#2810,.F.);
#2823=CARTESIAN_POINT('',(-0.812800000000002,0.,0.));
#2824=DIRECTION('',(1.,0.,0.));
#2825=DIRECTION('',(0.,0.,-1.));
#2826=AXIS2_PLACEMENT_3D('',#2823,#2824,#2825);
#2827=CYLINDRICAL_SURFACE('',#2826,4.918964);
#2828=ORIENTED_EDGE('',*,*,#1202,.T.);
#2829=ORIENTED_EDGE('',*,*,#2799,.F.);
#2830=ORIENTED_EDGE('',*,*,#1369,.F.);
#2831=ORIENTED_EDGE('',*,*,#2816,.T.);
#2832=EDGE_LOOP('',(#2828,#2829,#2830,#2831));
#2833=FACE_BOUND('',#2832,.T.);
#2834=ADVANCED_FACE('F1399',(#2833),#2827,.F.);
#2835=CARTESIAN_POINT('',(-0.812800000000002,-4.19410627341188,2.5701516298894));
#2836=DIRECTION('',(0.,-0.692671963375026,-0.721252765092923));
#2837=DIRECTION('',(0.,0.721252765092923,-0.692671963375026));
#2838=AXIS2_PLACEMENT_3D('',#2835,#2836,#2837);
#2839=PLANE('',#2838);
#2840=ORIENTED_EDGE('',*,*,#1351,.F.);
#2841=DIRECTION('',(1.,0.,0.));
#2842=VECTOR('',#2841,1.);
#2843=CARTESIAN_POINT('',(-0.812800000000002,-4.19410627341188,2.5701516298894));
#2844=LINE('',#2843,#2842);
#2845=EDGE_CURVE('E672',#1344,#1216,#2844,.T.);
#2846=ORIENTED_EDGE('',*,*,#2845,.T.);
#2847=ORIENTED_EDGE('',*,*,#1217,.T.);
#2848=ORIENTED_EDGE('',*,*,#100,.F.);
#2849=EDGE_LOOP('',(#2840,#2846,#2847,#2848));
#2850=FACE_BOUND('',#2849,.T.);
#2851=ADVANCED_FACE('F1357',(#2850),#2839,.F.);
#2852=CARTESIAN_POINT('',(-0.812800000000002,-3.74040957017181,3.19461156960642));
#2853=DIRECTION('',(0.,0.471904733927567,0.881649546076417));
#2854=DIRECTION('',(0.,-0.881649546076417,0.471904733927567));
#2855=AXIS2_PLACEMENT_3D('',#2852,#2853,#2854);
#2856=PLANE('',#2855);
#2857=ORIENTED_EDGE('',*,*,#1232,.T.);
#2858=DIRECTION('',(1.,0.,0.));
#2859=VECTOR('',#2858,1.);
#2860=CARTESIAN_POINT('',(-0.812800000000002,-3.74040957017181,3.19461156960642));
#2861=LINE('',#2860,#2859);
#2862=EDGE_CURVE('E685',#1335,#1225,#2861,.T.);
#2863=ORIENTED_EDGE('',*,*,#2862,.F.);
#2864=ORIENTED_EDGE('',*,*,#1336,.F.);
#2865=ORIENTED_EDGE('',*,*,#83,.F.);
#2866=EDGE_LOOP('',(#2857,#2863,#2864,#2865));
#2867=FACE_BOUND('',#2866,.T.);
#2868=ADVANCED_FACE('F1363',(#2867),#2856,.F.);
#2869=CARTESIAN_POINT('',(-0.812800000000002,0.,0.));
#2870=DIRECTION('',(1.,0.,0.));
#2871=DIRECTION('',(0.,0.,-1.));
#2872=AXIS2_PLACEMENT_3D('',#2869,#2870,#2871);
#2873=CYLINDRICAL_SURFACE('',#2872,4.918964);
#2874=ORIENTED_EDGE('',*,*,#1226,.T.);
#2875=ORIENTED_EDGE('',*,*,#2845,.F.);
#2876=ORIENTED_EDGE('',*,*,#1345,.F.);
#2877=ORIENTED_EDGE('',*,*,#2862,.T.);
#2878=EDGE_LOOP('',(#2874,#2875,#2876,#2877));
#2879=FACE_BOUND('',#2878,.T.);
#2880=ADVANCED_FACE('F1361',(#2879),#2873,.F.);
#2881=CARTESIAN_POINT('',(-0.812800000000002,-1.88240602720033,4.54453016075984));
#2882=DIRECTION('',(0.,-0.984325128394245,-0.176363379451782));
#2883=DIRECTION('',(0.,0.176363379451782,-0.984325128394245));
#2884=AXIS2_PLACEMENT_3D('',#2881,#2882,#2883);
#2885=PLANE('',#2884);
#2886=ORIENTED_EDGE('',*,*,#1327,.F.);
#2887=DIRECTION('',(1.,0.,0.));
#2888=VECTOR('',#2887,1.);
#2889=CARTESIAN_POINT('',(-0.812800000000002,-1.88240602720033,4.54453016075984));
#2890=LINE('',#2889,#2888);
#2891=EDGE_CURVE('E660',#1320,#1240,#2890,.T.);
#2892=ORIENTED_EDGE('',*,*,#2891,.T.);
#2893=ORIENTED_EDGE('',*,*,#1241,.T.);
#2894=ORIENTED_EDGE('',*,*,#73,.F.);
#2895=EDGE_LOOP('',(#2886,#2892,#2893,#2894));
#2896=FACE_BOUND('',#2895,.T.);
#2897=ADVANCED_FACE('F1373',(#2896),#2885,.F.);
#2898=CARTESIAN_POINT('',(-0.812800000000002,-1.14830934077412,4.78305263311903));
#2899=DIRECTION('',(0.,0.899999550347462,0.435890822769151));
#2900=DIRECTION('',(0.,-0.435890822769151,0.899999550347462));
#2901=AXIS2_PLACEMENT_3D('',#2898,#2899,#2900);
#2902=PLANE('',#2901);
#2903=ORIENTED_EDGE('',*,*,#1256,.T.);
#2904=DIRECTION('',(1.,0.,0.));
#2905=VECTOR('',#2904,1.);
#2906=CARTESIAN_POINT('',(-0.812800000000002,-1.14830934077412,4.78305263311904));
#2907=LINE('',#2906,#2905);
#2908=EDGE_CURVE('E668',#1311,#1249,#2907,.T.);
#2909=ORIENTED_EDGE('',*,*,#2908,.F.);
#2910=ORIENTED_EDGE('',*,*,#1312,.F.);
#2911=ORIENTED_EDGE('',*,*,#56,.F.);
#2912=EDGE_LOOP('',(#2903,#2909,#2910,#2911));
#2913=FACE_BOUND('',#2912,.T.);
#2914=ADVANCED_FACE('F1308',(#2913),#2902,.F.);
#2915=CARTESIAN_POINT('',(-0.812800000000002,0.,0.));
#2916=DIRECTION('',(1.,0.,0.));
#2917=DIRECTION('',(0.,0.,-1.));
#2918=AXIS2_PLACEMENT_3D('',#2915,#2916,#2917);
#2919=CYLINDRICAL_SURFACE('',#2918,4.918964);
#2920=ORIENTED_EDGE('',*,*,#1250,.T.);
#2921=ORIENTED_EDGE('',*,*,#2891,.F.);
#2922=ORIENTED_EDGE('',*,*,#1321,.F.);
#2923=ORIENTED_EDGE('',*,*,#2908,.T.);
#2924=EDGE_LOOP('',(#2920,#2921,#2922,#2923));
#2925=FACE_BOUND('',#2924,.T.);
#2926=ADVANCED_FACE('F2009',(#2925),#2919,.F.);
#2927=CARTESIAN_POINT('',(-0.812800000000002,1.14830934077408,4.78305263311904));
#2928=DIRECTION('',(0.,-0.899999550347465,0.435890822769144));
#2929=DIRECTION('',(0.,-0.435890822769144,-0.899999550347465));
#2930=AXIS2_PLACEMENT_3D('',#2927,#2928,#2929);
#2931=PLANE('',#2930);
#2932=ORIENTED_EDGE('',*,*,#1303,.F.);
#2933=DIRECTION('',(1.,0.,0.));
#2934=VECTOR('',#2933,1.);
#2935=CARTESIAN_POINT('',(-0.812800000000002,1.14830934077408,4.78305263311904));
#2936=LINE('',#2935,#2934);
#2937=EDGE_CURVE('E632',#1296,#1024,#2936,.T.);
#2938=ORIENTED_EDGE('',*,*,#2937,.T.);
#2939=ORIENTED_EDGE('',*,*,#1025,.T.);
#2940=ORIENTED_EDGE('',*,*,#41,.F.);
#2941=EDGE_LOOP('',(#2932,#2938,#2939,#2940));
#2942=FACE_BOUND('',#2941,.T.);
#2943=ADVANCED_FACE('F644',(#2942),#2931,.F.);
#2944=CARTESIAN_POINT('',(-0.812800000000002,1.8824060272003,4.54453016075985));
#2945=DIRECTION('',(0.,0.984325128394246,-0.176363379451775));
#2946=DIRECTION('',(0.,0.176363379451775,0.984325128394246));
#2947=AXIS2_PLACEMENT_3D('',#2944,#2945,#2946);
#2948=PLANE('',#2947);
#2949=ORIENTED_EDGE('',*,*,#1040,.T.);
#2950=DIRECTION('',(1.,0.,0.));
#2951=VECTOR('',#2950,1.);
#2952=CARTESIAN_POINT('',(-0.812800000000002,1.8824060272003,4.54453016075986));
#2953=LINE('',#2952,#2951);
#2954=EDGE_CURVE('E640',#1294,#1033,#2953,.T.);
#2955=ORIENTED_EDGE('',*,*,#2954,.F.);
#2956=ORIENTED_EDGE('',*,*,#1526,.F.);
#2957=ORIENTED_EDGE('',*,*,#262,.F.);
#2958=EDGE_LOOP('',(#2949,#2955,#2956,#2957));
#2959=FACE_BOUND('',#2958,.T.);
#2960=ADVANCED_FACE('F2026',(#2959),#2948,.F.);
#2961=CARTESIAN_POINT('',(-0.812800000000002,0.,0.));
#2962=DIRECTION('',(1.,0.,0.));
#2963=DIRECTION('',(0.,0.,-1.));
#2964=AXIS2_PLACEMENT_3D('',#2961,#2962,#2963);
#2965=CYLINDRICAL_SURFACE('',#2964,4.918964);
#2966=ORIENTED_EDGE('',*,*,#1034,.T.);
#2967=ORIENTED_EDGE('',*,*,#2937,.F.);
#2968=ORIENTED_EDGE('',*,*,#1297,.F.);
#2969=ORIENTED_EDGE('',*,*,#2954,.T.);
#2970=EDGE_LOOP('',(#2966,#2967,#2968,#2969));
#2971=FACE_BOUND('',#2970,.T.);
#2972=ADVANCED_FACE('F634',(#2971),#2965,.F.);
#2973=CLOSED_SHELL('',(#60,#87,#114,#141,#168,#195,#222,#249,#276,#318,#345,#372,#399,#426,#453,
#480,#507,#534,#561,#588,#615,#642,#669,#1260,#1282,#1868,#1885,#1902,#1914,#1931,#1948,#1960,
#1977,#1994,#2006,#2023,#2040,#2052,#2069,#2086,#2098,#2115,#2132,#2144,#2161,#2178,#2190,#2207,
#2224,#2236,#2253,#2270,#2282,#2299,#2316,#2328,#2345,#2362,#2374,#2391,#2408,#2420,#2437,#2454,
#2466,#2483,#2500,#2512,#2529,#2546,#2558,#2575,#2592,#2604,#2621,#2638,#2650,#2667,#2684,#2696,
#2713,#2730,#2742,#2759,#2776,#2788,#2805,#2822,#2834,#2851,#2868,#2880,#2897,#2914,#2926,#2943,
#2960,#2972));
#2974=MANIFOLD_SOLID_BREP('B2',#2973);
#2975=ADVANCED_BREP_SHAPE_REPRESENTATION('',(#18,#2974),#14);
#2976=SHAPE_DEFINITION_REPRESENTATION(#9,#2975);
ENDSEC;
END-ISO-10303-21;
